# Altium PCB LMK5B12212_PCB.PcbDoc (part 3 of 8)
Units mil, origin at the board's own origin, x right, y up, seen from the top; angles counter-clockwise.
Board outline 7000 x 9161 mil, 8 copper layers (L1-Top Layer (GTL), L2-GND Plane (GP1), L3-Mid-Layer 2 (G1), L4-Mid-Layer 3 (G2), L5-Mid-Layer 4 (G3), L6-Mid-Layer 5 (G4), L7-Mid-Layer 6 (G5), L8-Bottom Layer (GBL)), stack 61.2 mil thick; 469 components, 264 nets, 1268 pads, 1812 vias.

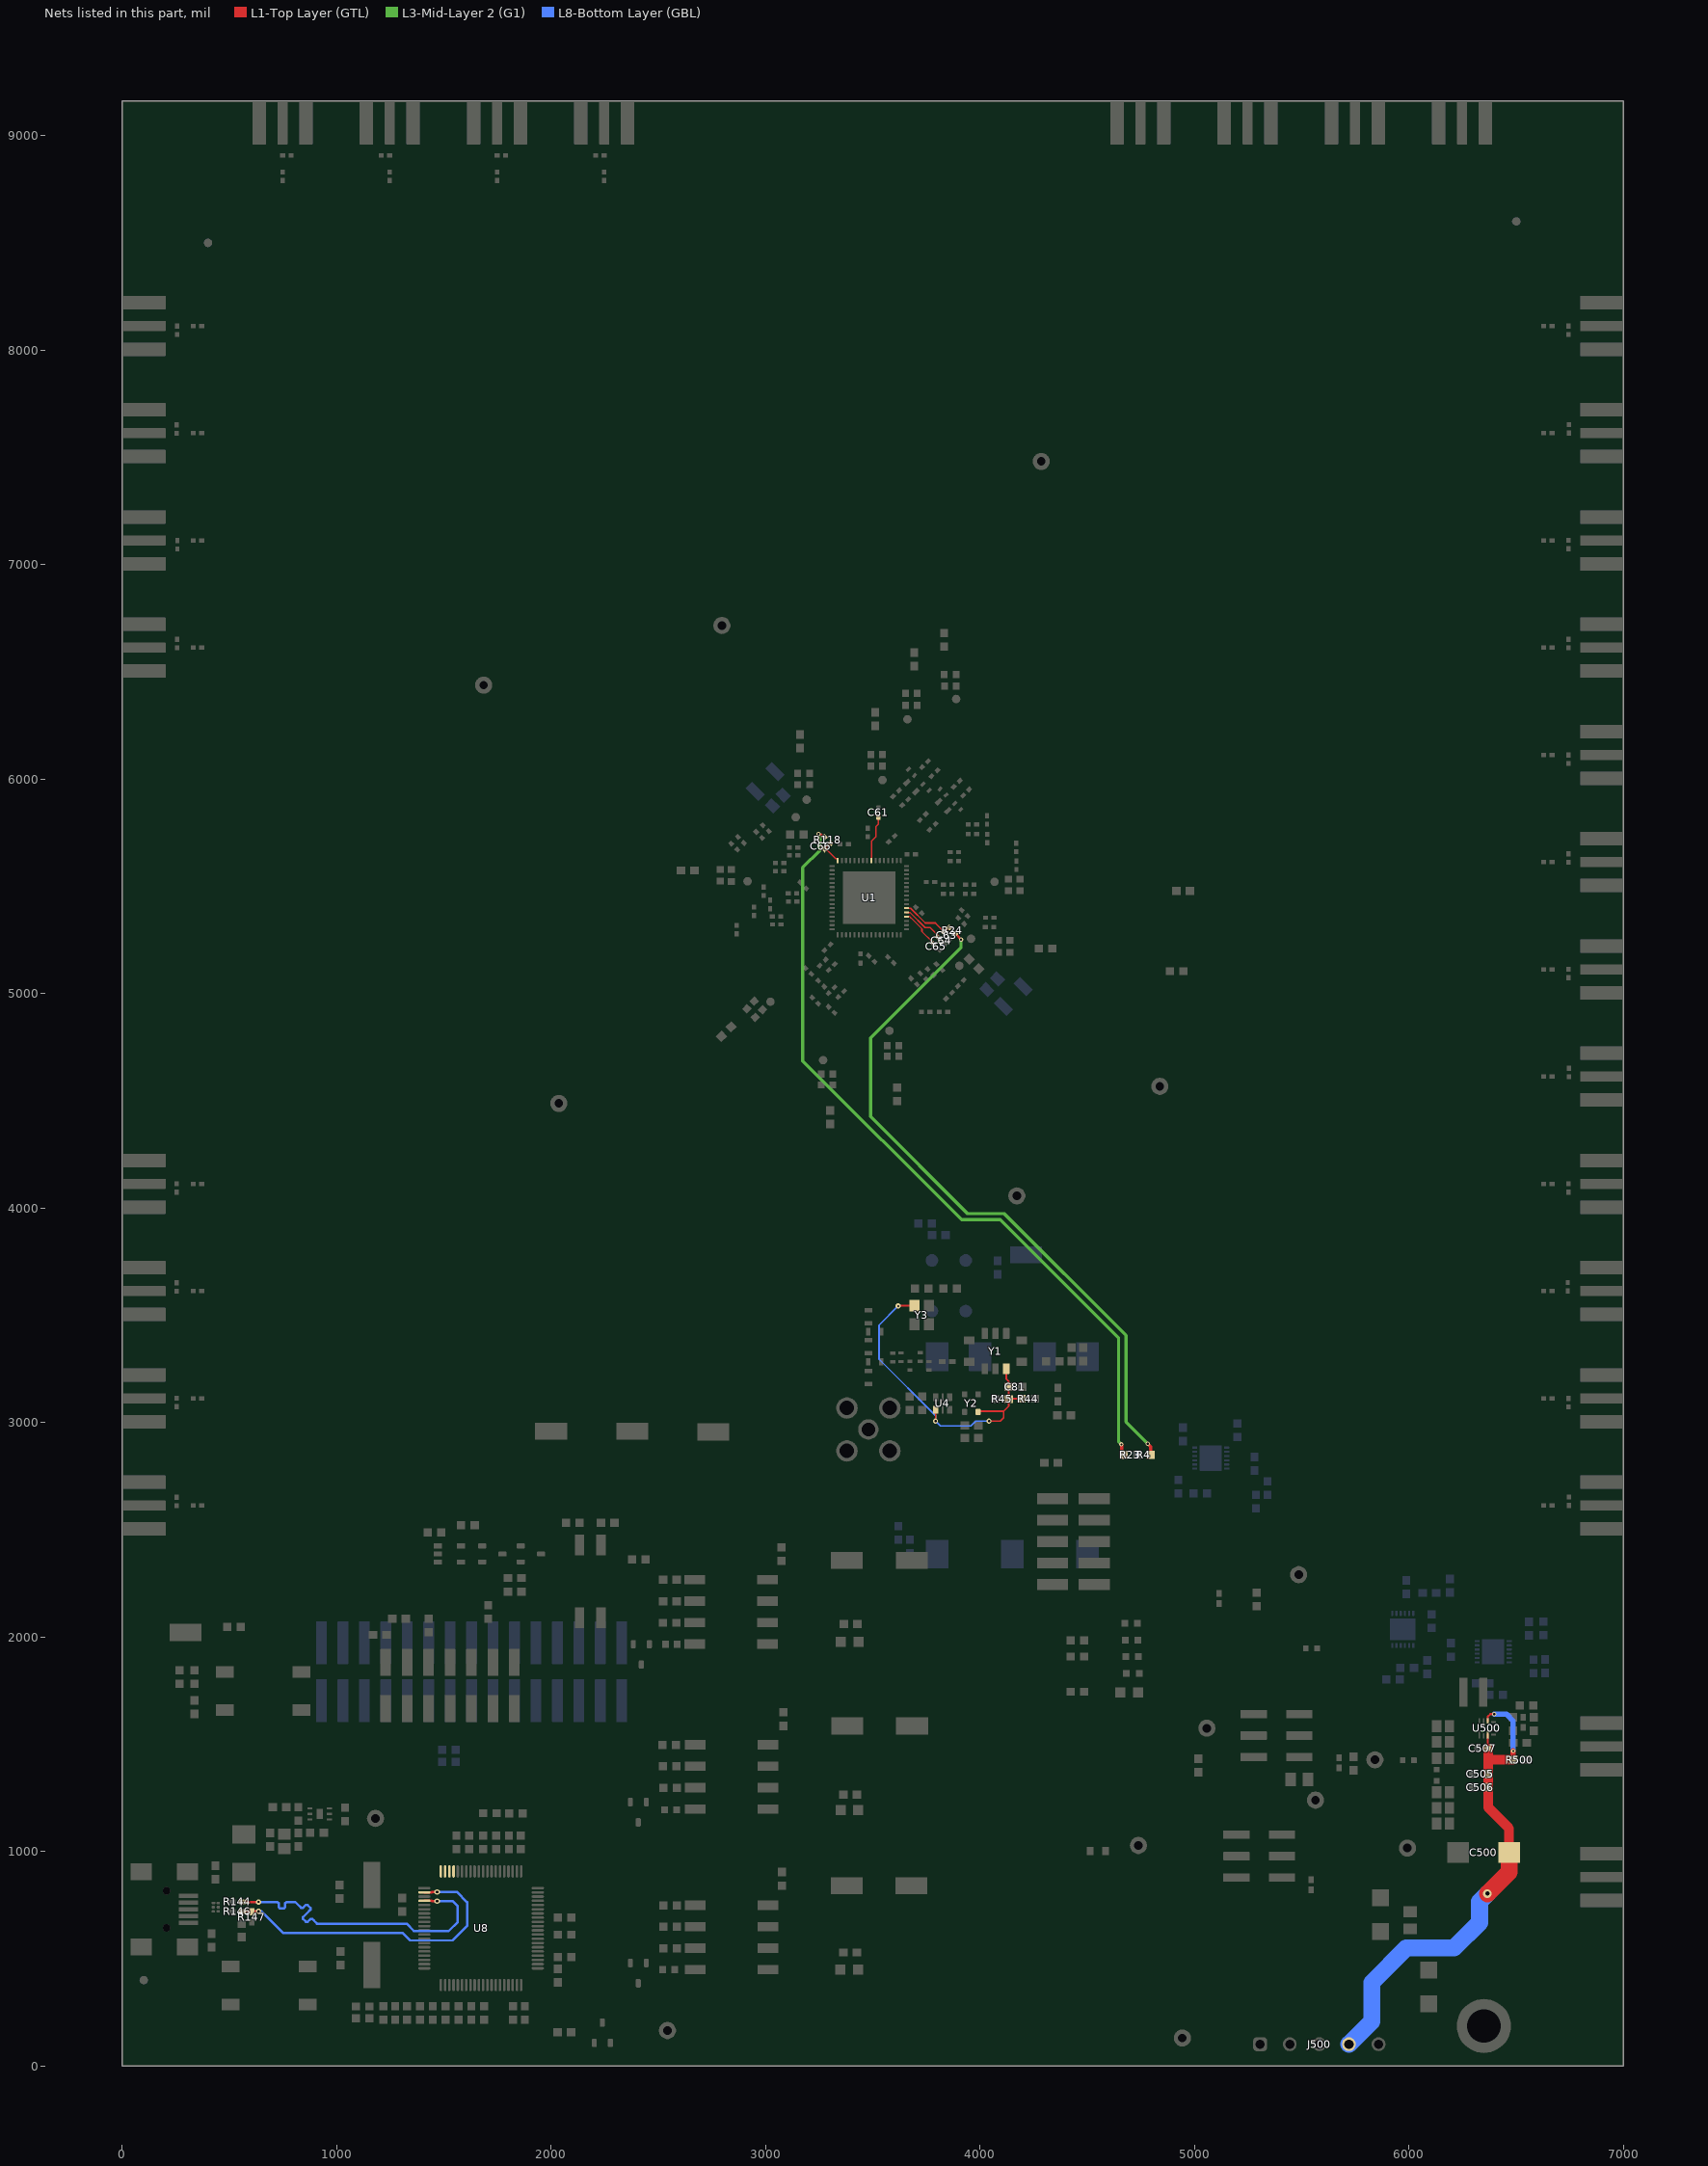
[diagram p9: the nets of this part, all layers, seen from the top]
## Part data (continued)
R144 R146: library part CMP-0026908-3, "RES, 33, 5%, 0.063 W, AEC-Q200 Grade 0, 0402", Manufacturer=Vishay-Dale, PartNumber=CRCW040233R0JNED, Power_W=63mW, Supplier Part Number 1=541-33JCT-ND, TempCo="200 ppm/C", Tolerance_%=5%, Value2=0.063W, Value_Code=33R0, ValueDisplayed=33
R145 R148 R165: library part CMP-0025786-4, "RES, 33 k, 5%, 0.1 W, AEC-Q200 Grade 0, 0603", Manufacturer=Vishay-Dale, PartNumber=CRCW060333K0JNEA, Power_W=100mW, Supplier Part Number 1=541-33KGCT-ND, TempCo="200 ppm/C", Tolerance_%=5%, Value2=0.1W, Value_Code=33k0, ValueDisplayed=33k
R147: library part CMP-0026856-5, "RES, 1.5 k, 5%, 0.063 W, AEC-Q200 Grade 0, 0402", Manufacturer=Vishay-Dale, PartNumber=CRCW04021K50JNED, Power_W=63mW, Supplier Part Number 1=541-1.5KJCT-ND, TempCo="200 ppm/C", Tolerance_%=5%, Value2=0.063W, Value_Code=1k50, ValueDisplayed=1.5k
R149: library part CMP-0025738-4, "RES, 1.2 M, 5%, 0.1 W, AEC-Q200 Grade 0, 0603", Manufacturer=Vishay-Dale, PartNumber=CRCW06031M20JNEA, Power_W=100mW, Supplier Part Number 1=541-1.2MGCT-ND, TempCo="200 ppm/C", Tolerance_%=5%, Value2=0.1W, Value_Code=1M20, ValueDisplayed=1.2M
R159 R160: library part CMP-0025729-4, "RES, 1.0 k, 5%, 0.1 W, AEC-Q200 Grade 0, 0603", Manufacturer=Vishay-Dale, Power_W=100mW, Supplier Part Number 1=541-1.0KGCT-ND, TempCo="200 ppm/C", Tolerance_%=5%, Value2=0.1W, Value_Code=1k00, ValueDisplayed=1.0k
R161 R162 R166: library part CMP-0025823-4, "RES, 510, 5%, 0.1 W, AEC-Q200 Grade 0, 0603", Manufacturer=Vishay-Dale, PartNumber=CRCW0603510RJNEA, Power_W=100mW, Supplier Part Number 1=541-510GCT-ND, TempCo="200 ppm/C", Tolerance_%=5%, Value2=0.1W, Value_Code=510R, ValueDisplayed=510
R201 R202 R203: library part CMP-0025814-4, "RES, 47 k, 5%, 0.1 W, AEC-Q200 Grade 0, 0603", Manufacturer=Vishay-Dale, PartNumber=CRCW060347K0JNEA, Power_W=100mW, Supplier Part Number 1=541-47KGCT-ND, TempCo="200 ppm/C", Tolerance_%=5%, Value2=0.1W, Value_Code=47k0, ValueDisplayed=47k
R206 R207 R208 R209 R210 R211: library part CMP-0025885-5, "RES, 0, 5%, 0.1 W, 0603", Manufacturer=Yageo, Power_W=100mW, Supplier Part Number 1=311-0.0GRCT-ND, TempCo="200 ppm/C", Tolerance_%=5%, Value2=0.1W, Value_Code=0000, ValueDisplayed=0
R501: library part CMP-0023576-3, "RES, 5.60 k, 0.1%, 0.1 W, 0603", Manufacturer="Susumu Co Ltd", Power_W=100mW, Supplier Part Number 1=RG16P5.6KBCT-ND, TempCo="25 ppm/C", Tolerance_%=0.1%, Value2=0.1W, Value_Code=5k60, ValueDisplayed=5.60k
R502: library part CMP-0022097-4, "RES, 18.2 k, 1%, 0.1 W, AEC-Q200 Grade 0, 0603", Manufacturer=Vishay-Dale, Power_W=100mW, Supplier Part Number 1=541-18.2KHCT-ND, TempCo="100 ppm/C", Tolerance_%=1%, Value2=0.1W, Value_Code=18k2, ValueDisplayed=18.2k
R504: library part CMP-0023914-3, "RES, 1.80 k, 0.1%, 0.1 W, 0603", Manufacturer="Yageo America", Power_W=100mW, TempCo="25 ppm/C", Tolerance_%=0.1%, Value2=0.1W, Value_Code=1k80, ValueDisplayed=1.80k
S1 S2 S4: library part CMP-0002176-2, "Switch, SPST 4 Pos, Top Actuated, SMT", CurrentRating_mA=100A, Manufacturer="CTS Electrocomponents", PartNumber=219-4LPST, Supplier Part Number 1=CT2194LPST-ND
S3: library part CMP-0002127-2, "Switch, Slide, SPST 2 poles, SMT", CurrentRating_mA=100A, Manufacturer="CTS Electrocomponents", PartNumber=219-2LPST, Supplier Part Number 1=CT2192LPST-ND
S5 S6: library part CMP-0002134-3, "Switch, Tactile, SPST-NO, 0.05A, 12V, SMT", CurrentRating_mA=50A, Manufacturer="TE Connectivity", PartNumber=FSM4JSMA, Supplier Part Number 1=450-1129-ND
SH1 SH2 SH4 SH5 SH6: library part CMP-0003623-3, "Shunt, 100mil, Gold plated, Black", Alternate Manufacturer=3M, Alternate PartNumber=969102-0000-DA, Manufacturer=Samtec, Supplier Part Number 1=SAM8858-ND
TP1 TP2 TP4 TP5 TP7 TP41 TP501: library part CMP-0055137-1, "Test Point, Miniature, Red, TH", Color=Red, Manufacturer=Keystone, PartNumber=5000, Supplier Part Number 1=36-5000-ND
TP8 TP9 TP10 TP11 TP12 TP13 TP14 TP15 TP16 TP18 TP28 TP29: library part CMP-0003825-1, "1mm Test Point, SMT", Manufacturer=Any, PartNumber=TP_SM_1MM
TP19 TP20 TP21 TP22 TP23 TP24 TP25 TP26: library part CMP-0055138-1, "Test Point, Miniature, Black, TH", Color=Black, Manufacturer=Keystone, PartNumber=5001, Supplier Part Number 1=36-5001-ND
TP30 TP31 TP32 TP33 TP34 TP35 TP36 TP37 TP38 TP39 TP40: library part CMP-0055162-1, "Test Point, Miniature, SMT", Manufacturer=Keystone, PartNumber=5019, Supplier Part Number 1=36-5019TR-ND
U1: library part CMP-0096725-1, "1-DPLL 2-APLL 2-IN 12-OUT Network Synchronizer with JESD204B/C and BAW for Wired Communications", Manufacturer="Texas Instruments", Max Frequency=800MHz, Max Supply Voltage=3.465V, Min Supply Voltage=3.135V, Operating Temperature Range="to +125°C", Part Number=LMK5C22212RGCR
U4: library part CMP-0078850-3, "CDC64XX-2520, DLF0006A (VSON-6)", Alternate Manufacturer="Texas Instruments"
U5: library part CMP-0052046-2, "Single 2-Input Exclusive-OR Gate, DBV0005A (SOT-23-5)", F @ Nom Voltage(Max)(Mhz)=150, Generic Part Number=SN74LVC1G86, ICC @ Nom Voltage(Max)(mA)=0.01, Manufacturer="Texas Instruments", Operating Temperature Range="-40 to 125 C", PartNumber=SN74LVC1G86DBVR, Rating=Catalog, tpd @ Nom Voltage(Max)(ns)=9.9,5.5,5,4, Voltage(Nom)(V)=1.8,2.5,3.3,5
U6: library part CMP-0066010-1, "150-mA Ultra-Low Noise LDO for RF and Analog Circuits Requires No Bypass Capacitor, NGF0006A (WSON-6)", Alternate Manufacturer="Texas Instruments"
U7: library part CMP-0043115-3, "4-Channel ESD Protection Array for High-Speed Data Interfaces, DRY0006A (USON-6)", Breakdown Voltage(Min)(V)=6, IO Capacitance(Typ)(pF)=1.6, IO Leakage Current(nA)=1, Manufacturer="Texas Instruments", Operating Temperature Range="-40 to 85 C", Rating=Catalog
U8: library part CMP-0038965-1, "25 MHz Mixed Signal Microcontroller with 128 KB Flash, 8192 B SRAM and 63 GPIOs, -40 to 85 degC, 80-pin QFP (PN), Green (RoHS & no Sb/Br)", Frequency(MHz)=25, Manufacturer="Texas Instruments", Temp Sensor=Yes
U9 U10 U11: library part CMP-0066007-2, "800-mA Ultra-Low-Noise, High-PSRR LDO, DNT0012B (WSON-12)", Alternate Manufacturer="Texas Instruments"
U500: library part CMP-0860321-2, "3A Low Noise and Low Ripple buck converter, RPU0010A (VQFN-10)", Alternate Manufacturer="Texas Instruments"
Y1: library part CMP-0093851-1, "SMD TCXO 7.0 * 5.0 48.000000MHz", Frequency_Fixed=48MHz, Frequency Stability=0.25ppm, Load Capacitance=15pF, Manufacturer=TXC, Max Supply Current=10mA, Max Supply Voltage=3.63V, Min Supply Voltage=2.97V, Operating Temperature Range="-40°C to +105°C"
Y2: library part CMP-0096255-1, "High-Performance BAW Oscillator, LVCMOS; <1ps, +/- 50ppm; 2.5V/3.3V, -40C to 105C and DLE package", Frequency Stability=50ppm, Frequency_Fixed=48MHz, Load Capacitance=30pF, Manufacturer="Texas Instruments", Max Supply Voltage=3.465V, Min Supply Voltage=2.375V, Operating Temperature Range="-40°C to +105°C", PartNumber=LMK6CE04800DDLF
Y3: library part CMP-0006115-3, "Crystal, Sealed Locked 50 MHz, 15pF, SMD", Frequency_Fixed=50MHz, Frequency Stability=+/-50ppm, Manufacturer="TXC Corporation", Supplier Part Number 1=887-1513-1-ND
Y4: library part CMP-0088752-1, "MERCURY+ 38.88MHz OCXO CMOS Oscillator 2.7 ~ 5V 4-SMD", Frequency_Fixed=38.88MHz, Frequency Stability=0.01ppm, Manufacturer=Rakon, Max Supply Voltage=5V, Min Supply Voltage=2.7V, Operating Temperature Range="-40°C to +95°C"
Y5: library part CMP-0088753-1, "STANDARD OCXO 10MHz Frequency", Frequency_Fixed=10MHz, Manufacturer=Rakon, Max Supply Voltage=3.465V, Min Supply Voltage=3.135V, Operating Temperature Range="-40°C to +85°C"
Y6: library part CMP-0004572-3, "Crystal, 24.000 MHz, 20pF, SMD", Frequency_Fixed=24MHz, Frequency Stability=+/-50ppm, Manufacturer="ECS Inc.", PartNumber=ECS-240-20-5PX-TR, Supplier Part Number 1=XC1255CT-ND
ZZ1: library part CMP-0003616-3
ZZ2: library part CMP-0077236-1
ZZ3: library part CMP-0077237-1
ZZ4: library part CMP-0077238-1
ZZ5 ZZ6 ZZ7: library part CMP-0003615-1, "This Assembly Note will show in the PcbDoc and associated outputs"

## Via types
v1: diameter 20, hole 10, L1-Top Layer (GTL) to L8-Bottom Layer (GBL), tented top, 987 vias
v2: diameter 30, hole 12, L1-Top Layer (GTL) to L8-Bottom Layer (GBL), 407 vias
v3: diameter 25, hole 12, L1-Top Layer (GTL) to L8-Bottom Layer (GBL), tented top, 163 vias
v4: diameter 30, hole 12, L1-Top Layer (GTL) to L8-Bottom Layer (GBL), tented top, 52 vias
v5: diameter 19.68, hole 7.87, L1-Top Layer (GTL) to L8-Bottom Layer (GBL), 47 vias
v6: diameter 20, hole 10, L1-Top Layer (GTL) to L8-Bottom Layer (GBL), 39 vias
v7: diameter 25, hole 10, L1-Top Layer (GTL) to L8-Bottom Layer (GBL), tented top, 35 vias
v8: diameter 25, hole 12, L1-Top Layer (GTL) to L8-Bottom Layer (GBL), 23 vias
v9: diameter 30, hole 10, L1-Top Layer (GTL) to L8-Bottom Layer (GBL), 10 vias
v10: diameter 40, hole 20, L1-Top Layer (GTL) to L8-Bottom Layer (GBL), 10 vias
v11: diameter 18, hole 10, L1-Top Layer (GTL) to L8-Bottom Layer (GBL), tented top, 8 vias
v12: diameter 20, hole 10, L1-Top Layer (GTL) to L8-Bottom Layer (GBL), tented both sides, 6 vias
v13: diameter 39.37, hole 19.68, L1-Top Layer (GTL) to L8-Bottom Layer (GBL), tented top, 6 vias
v14: diameter 50, hole 28, L1-Top Layer (GTL) to L8-Bottom Layer (GBL), 4 vias
v15: diameter 23, hole 10, L1-Top Layer (GTL) to L8-Bottom Layer (GBL), tented top, 4 vias
v16: diameter 25, hole 10, L1-Top Layer (GTL) to L8-Bottom Layer (GBL), 4 vias
v17: diameter 25, hole 12, L1-Top Layer (GTL) to L8-Bottom Layer (GBL), tented both sides, 3 vias
v18: diameter 20/0/0/0/0/0/20 (per signal layer), hole 10, L1-Top Layer (GTL) to L8-Bottom Layer (GBL), tented top, 2 vias
v19: diameter 30, hole 12, L1-Top Layer (GTL) to L8-Bottom Layer (GBL), tented both sides, 1 vias
v20: diameter 25, hole 10, L1-Top Layer (GTL) to L8-Bottom Layer (GBL), tented both sides, 1 vias

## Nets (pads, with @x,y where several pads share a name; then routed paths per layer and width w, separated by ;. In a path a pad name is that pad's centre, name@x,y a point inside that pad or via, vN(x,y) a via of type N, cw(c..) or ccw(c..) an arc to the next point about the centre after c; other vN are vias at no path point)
+12V: C500.1 C505.2 C506.2 C507.1 J500.4 R500.2 U500.1 U500.6 | length 2378.2
  L1-Top Layer (GTL) w10: U500.6@6367.34,1546.44 6367.34,1480.88 C507.1@6367.92,1480.3 ; U500.1@6367.34,1608.45 6367.34,1628.34 6379.3,1640.3 v6(6397.8,1640.3)
  L1-Top Layer (GTL) w25: R500.2@6485.8,1428.3 v12(6485.8,1468)
  L1-Top Layer (GTL) w45: C507.1@6368.22,1480 C505.2@6368.22,1360.5 C506.2@6368.22,1299.4 6368.22,1205.78 6466.69,1107.31 C500.1@6466.69,995.9 ; 6368.42,1427.1 R500.2@6484.6,1427.1
  L1-Top Layer (GTL) w80: v10(6365.6,803.2) 6466.69,904.29 C500.1@6466.69,995.9
  L8-Bottom Layer (GBL) w25: v6(6397.8,1640.3) 6453.4,1640.3 6485.8,1607.9 v12(6485.8,1468)
  L8-Bottom Layer (GBL) w80: J500.4@5719.7,101.2 5826.3,207.8 5826.3,388.7 5987.6,550 6210.1,550 6328.5,668.4 6328.5,766.1 v10(6365.6,803.2)
APLL1_LDO: R23.2 R118.1 | length 3690.2
  L1-Top Layer (GTL) w11: v6(3247.1,5744.1) 3248.82,5742.38 3256.28,5742.38 3268.94,5729.72 R118.1@3275.08,5729.72
  L1-Top Layer (GTL) w15: v6(4658.7,2897.7) 4659.66,2896.74 4659.66,2858.76 R23.2@4669.12,2849.3
  L3-Mid-Layer 2 (G1) w15: v6(3247.1,5744.1) 3247.1,5742.75 3253.81,5736.04 3253.81,5702.16 3254,5701.97 3254,5668.1 3173.35,5587.45 3173.35,4685.75 3914,3945.1 4094.3,3945.1 4646,3393.4 4646,2910.4 v6(4658.7,2897.7)
APLL2_LDO: R4.2 R24.1 | length 3267.9
  L1-Top Layer (GTL) w11: R24.1@3885.32,5276.77 3887.68,5276.77 3887.68,5276.07 3911,5252.75 v6(3911,5251.1)
  L1-Top Layer (GTL) w15: R24.1@3885.32,5276.77 R24.1@3885.32,5280.08 ; v6(4782.1,2900.7) 4795.1,2887.7 R4.2@4795.1,2849.3
  L3-Mid-Layer 2 (G1) w15: v6(3911,5251.1) 3911,5214.5 3489.05,4792.55 3489.05,4425.75 3941.05,3973.75 4111.85,3973.75 4680.2,3405.4 4680.2,3002.6 v6@4788.64,2894.16
C1PLL2: C63.1 R24.2 U1.22 | length 259
  L1-Top Layer (GTL) w8: U1.22@3656.38,5397.64 3657.1,5396.91 3676.29,5396.91 3744.4,5328.8 3791.24,5328.8 C63.1@3831.49,5288.55
  L1-Top Layer (GTL) w15: C63.1@3829.89,5286.81 3851.59,5308.51 3857.59,5308.51 R24.2@3858.98,5307.12
C2PLL2: C64.1 U1.21 | length 195.4
  L1-Top Layer (GTL) w7: U1.21@3656.38,5377.95 3672.8,5377.95 3743.31,5307.44 3767.26,5307.44 C64.1@3806.4,5268.3
C3PLL2: C65.1 U1.20 | length 177.8
  L1-Top Layer (GTL) w7: U1.20@3656.38,5358.27 3671.73,5358.27 3676.92,5353.08 3677.42,5353.08 3728.92,5301.59 3728.92,5288.86 C65.1@3777.73,5240.05
CDIG: C61.1 U1.40 | length 209.8
  L1-Top Layer (GTL) w7: U1.40@3492.99,5620.08 3492.99,5709.98 3515,5731.99 3515,5779.06 3526.25,5790.31 C61.1@3526.25,5816.13
CPLL1: C66.1 R118.2 U1.48 | length 123.7
  L1-Top Layer (GTL) w7: C66.1@3280.59,5675 3327.4,5628.19 3334.29,5628.19 3335.51,5626.97 U1.48@3335.51,5620.08
  L1-Top Layer (GTL) w10: C66.1@3272.88,5673.1 3277.06,5677.28 3278.31,5677.28 R118.2@3302.92,5701.88
D_N: R144.1 U8.64 | length 1464.2
  L1-Top Layer (GTL) w11: R144.1@559.62,765 580.87,765 581.37,764.5 v16(635,764.5) ; U8.64@1407.95,769.8 1441.99,769.8 1444.3,767.49 v3(1468,767.49)
  L8-Bottom Layer (GBL) w11: v16(635,764.5) 713,764.5 722.8,764.5 729,758.3 729,740.35 735.2,734.15 753.8,734.15 760,740.35 760,758.3 766.2,764.5 791,764.5 806.5,764.5 816.28,754.72 833.82,737.18 842.58,737.18 855.28,749.88 864.05,749.88 877.2,736.73 877.2,727.96 860.12,710.88 843.04,693.8 843.04,685.03 856.19,671.88 864.96,671.88 877.66,684.58 886.42,684.58 893,678 908,663 1326,663 1360,629 1522,629 1564,671 1564,745 1541.51,767.49 v3(1468,767.49)
D_P: R146.1 R147.2 U8.62 | length 1464.2
  L1-Top Layer (GTL) w11: R146.1@559.62,720 580.87,720 581.37,720.5 604,720.5 v20(635,720.5) ; U8.62@1407.95,809.17 1441.99,809.17 1444.3,811.49 v3(1468,811.49)
  L8-Bottom Layer (GBL) w11: v20(635,720.5) 649.5,720.5 751,619 1307.77,619 1341.77,585 1540.23,585 1608,652.77 1608,763.23 1559.74,811.49 v3(1468,811.49)
EN_XO: C81.1 R44.2 R45.1 U4.1 Y1.8 Y2.1 Y3.1 | length 1568
  L1-Top Layer (GTL) w8: v7(3618.41,3542.53) 3620.23,3544.35 Y3.1@3693.86,3544.35 ; v15(3792.57,3006.56) 3792.57,3006.24 U4.1@3792.57,3059.17 ; Y2.1@3989.9,3052.51 4109.38,3052.51 ; v15(4041.79,3006.24) 4093.21,3006.24 4109.38,3022.41 4109.38,3052.51 ; Y1.8@4121.72,3244.08 4121.72,3204.42 4132.86,3193.28 R45.1@4132.86,3110.68 ; R44.2@4192.86,3110.68 4135.18,3110.68 R45.1@4133.43,3108.93 4133.43,3076.56 4109.38,3052.51
  L8-Bottom Layer (GBL) w8: v7(3618.41,3542.53) 3529,3453.12 3529,3295.09 3792.57,3031.52 v15(3792.57,3006.56) 3792.57,3006.24 3814.81,2984 3957.24,2984 3979.48,3006.24 v15(4041.79,3006.24)
EXT3.3V_EN: U8.59
EXT3.3V_FAULT: U8.60
EXT5V_EN: U8.57
EXT5V_FAULT: U8.58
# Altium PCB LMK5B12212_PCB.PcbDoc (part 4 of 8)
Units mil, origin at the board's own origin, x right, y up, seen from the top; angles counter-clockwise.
Board outline 7000 x 9161 mil, 8 copper layers (L1-Top Layer (GTL), L2-GND Plane (GP1), L3-Mid-Layer 2 (G1), L4-Mid-Layer 3 (G2), L5-Mid-Layer 4 (G3), L6-Mid-Layer 5 (G4), L7-Mid-Layer 6 (G5), L8-Bottom Layer (GBL)), stack 61.2 mil thick; 469 components, 264 nets, 1268 pads, 1812 vias.

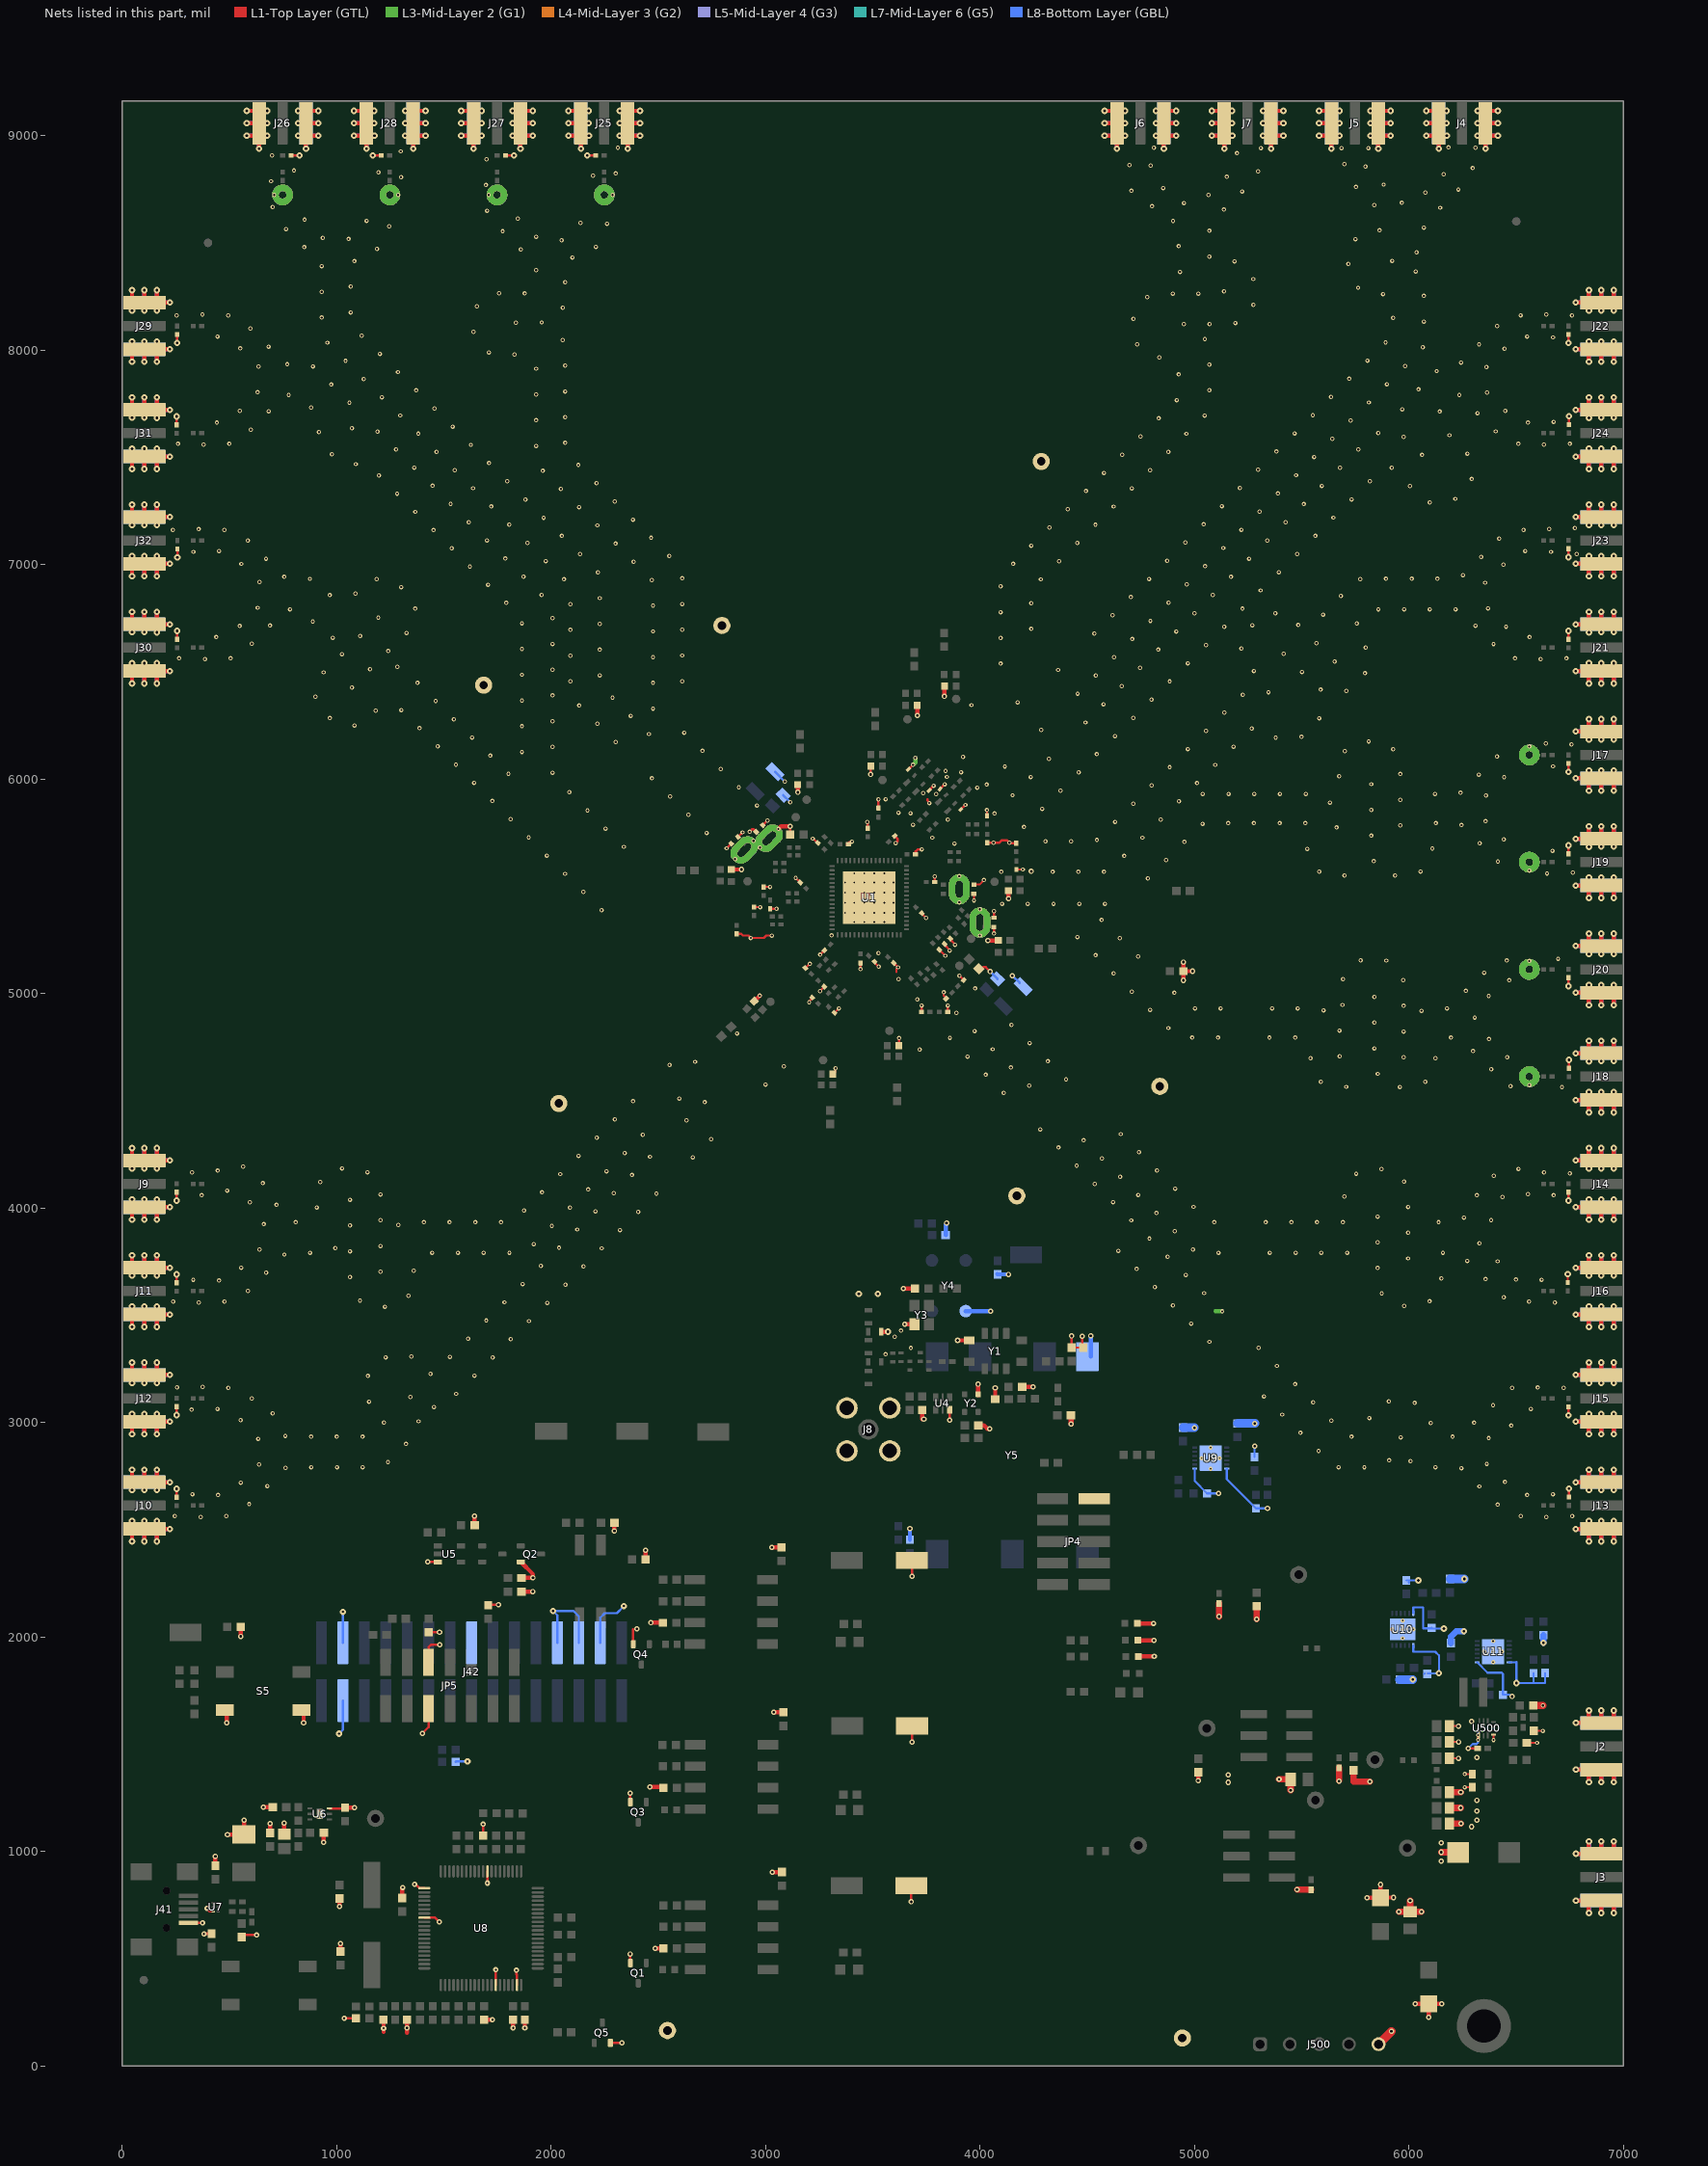
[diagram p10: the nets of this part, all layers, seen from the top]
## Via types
v1: diameter 20, hole 10, L1-Top Layer (GTL) to L8-Bottom Layer (GBL), tented top, 987 vias
v2: diameter 30, hole 12, L1-Top Layer (GTL) to L8-Bottom Layer (GBL), 407 vias
v3: diameter 25, hole 12, L1-Top Layer (GTL) to L8-Bottom Layer (GBL), tented top, 163 vias
v4: diameter 30, hole 12, L1-Top Layer (GTL) to L8-Bottom Layer (GBL), tented top, 52 vias
v5: diameter 19.68, hole 7.87, L1-Top Layer (GTL) to L8-Bottom Layer (GBL), 47 vias
v6: diameter 20, hole 10, L1-Top Layer (GTL) to L8-Bottom Layer (GBL), 39 vias
v7: diameter 25, hole 10, L1-Top Layer (GTL) to L8-Bottom Layer (GBL), tented top, 35 vias
v8: diameter 25, hole 12, L1-Top Layer (GTL) to L8-Bottom Layer (GBL), 23 vias
v9: diameter 30, hole 10, L1-Top Layer (GTL) to L8-Bottom Layer (GBL), 10 vias
v10: diameter 40, hole 20, L1-Top Layer (GTL) to L8-Bottom Layer (GBL), 10 vias
v11: diameter 18, hole 10, L1-Top Layer (GTL) to L8-Bottom Layer (GBL), tented top, 8 vias
v12: diameter 20, hole 10, L1-Top Layer (GTL) to L8-Bottom Layer (GBL), tented both sides, 6 vias
v13: diameter 39.37, hole 19.68, L1-Top Layer (GTL) to L8-Bottom Layer (GBL), tented top, 6 vias
v14: diameter 50, hole 28, L1-Top Layer (GTL) to L8-Bottom Layer (GBL), 4 vias
v15: diameter 23, hole 10, L1-Top Layer (GTL) to L8-Bottom Layer (GBL), tented top, 4 vias
v16: diameter 25, hole 10, L1-Top Layer (GTL) to L8-Bottom Layer (GBL), 4 vias
v17: diameter 25, hole 12, L1-Top Layer (GTL) to L8-Bottom Layer (GBL), tented both sides, 3 vias
v18: diameter 20/0/0/0/0/0/20 (per signal layer), hole 10, L1-Top Layer (GTL) to L8-Bottom Layer (GBL), tented top, 2 vias
v19: diameter 30, hole 12, L1-Top Layer (GTL) to L8-Bottom Layer (GBL), tented both sides, 1 vias
v20: diameter 25, hole 10, L1-Top Layer (GTL) to L8-Bottom Layer (GBL), tented both sides, 1 vias

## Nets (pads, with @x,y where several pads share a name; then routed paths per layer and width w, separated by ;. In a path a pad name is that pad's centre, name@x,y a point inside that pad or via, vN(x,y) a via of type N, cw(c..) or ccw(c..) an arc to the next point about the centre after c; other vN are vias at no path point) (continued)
GND: C1.2 C2.2 C3.2 C6.1 C7.2 C8.2 C9.2 C10.2 C13.2 C21.1 C22.2 C23.2 C24.2 C27.2 C29.2 C30.1 C32.2 C33.1 C35.2 C36.1 C38.2 C39.1 C41.2 C42.1 C44.2 C45.1 C47.2 C48.1 C50.2 C51.1 C53.2 C54.1 C59.2 C60.1 C61.2 C63.2 C64.2 C65.2 C66.2 C72.2 C73.1 C74.2 C75.2 C76.1 C77.2 C78.2 C79.1 C80.2 C81.2 C82.2 C83.2 C84.2 C85.2 C86.2 C87.2 C88.2 C89.1 C90.2 C91.2 C92.2 C93.2 C94.2 C95.2 C96.2 C97.2 C129.1 C130.2 C131.2 C132.1 C133.1 C134.1 C135.2 C136.2 C137.1 C138.1 C139.2 C140.1 C141.1 C142.1 C143.1 C144.1 C154.2 C155.2 C156.2 C500.2 C501.2 C502.2 C503.2 C504.2 C505.1 C506.1 C507.2 C508.2 C509.2 C510.2 C512.2 C513.2 C514.2 C515.2 C516.2 D1.2 D2.2 D3.2 D4.2 D5.2 D11.2 J2.2 J2.3 J2.4 J2.5 J3.2 J3.3 J3.4 J3.5 J4.2 J4.3 J4.4 J4.5 J5.2 J5.3 J5.4 J5.5 J6.2 J6.3 J6.4 J6.5 J7.2 J7.3 J7.4 J7.5 J8.2 J8.3 J8.4 J8.5 J9.2 J9.3 J9.4 J9.5 J10.2 J10.3 J10.4 J10.5 J11.2 J11.3 J11.4 J11.5 J12.2 J12.3 J12.4 J12.5 J13.2 J13.3 J13.4 J13.5 J14.2 J14.3 J14.4 J14.5 J15.2 J15.3 J15.4 J15.5 J16.2 J16.3 J16.4 J16.5 J17.2 J17.3 J17.4 J17.5 J18.2 J18.3 J18.4 J18.5 J19.2 J19.3 J19.4 J19.5 J20.2 J20.3 J20.4 J20.5 J21.2 J21.3 J21.4 J21.5 J22.2 J22.3 J22.4 J22.5 J23.2 J23.3 J23.4 J23.5 J24.2 J24.3 J24.4 J24.5 J25.2 J25.3 J25.4 J25.5 J26.2 J26.3 J26.4 J26.5 J27.2 J27.3 J27.4 J27.5 J28.2 J28.3 J28.4 J28.5 J29.2 J29.3 J29.4 J29.5 J30.2 J30.3 J30.4 J30.5 J31.2 J31.3 J31.4 J31.5 J32.2 J32.3 J32.4 J32.5 J41.5 J42.4 J42.6 J42.8 J42.16 J42.27 J42.28 J500.5 JP4.9 JP5.A03 JP5.B03 Q1.2 Q2.2 Q3.2 Q4.2 Q5.2 R2.1 R5.1 R9.1 R28.1 R32.1 R35.1 R39.1 R42.1 R45.2 R53.1 R62.1 R65.1 R69.1 R72.1 R78.1 R79.1 R82.1 R85.1 R86.1 R88.1 R90.1 R92.1 R94.1 R96.1 R99.1 R101.1 R103.1 R105.1 R109.1 R111.1 R113.1 R115.1 R117.1 R119.1 R121.1 R122.1 R125.1 R127.1 R148.2 R149.1 R167.2 R168.2 R169.2 R170.2 R171.2 R172.2 R173.2 R174.2 R175.2 R176.2 R177.2 R178.2 R179.2 R180.2 R181.2 R182.2 R183.2 R184.2 R185.2 R186.2 R187.2 R188.2 R204.2 R205.2 R502.1 R504.1 S5.3 S5.4 TP19.1 TP20.1 TP21.1 TP22.1 TP23.1 TP24.1 TP25.1 TP26.1 TP32.1 TP35.1 TP39.1 U1.65 U4.3 U5.3 U6.3 U6.7 U7.3 U8.14 U8.19 U8.49 U8.61 U8.68 U9.6 U9.7 U9.13 U10.6 U10.7 U10.13 U11.6 U11.7 U11.13 U500.4 U500.7 Y1.4 Y2.2 Y3.2 Y4.2 Y5.7 | length 75760.6
  L1-Top Layer (GTL) w10: v7(396,735) 396,730 405.68,720.32 U7.3@424.19,720.32 ; R186.2@2864,5278 2886,5278 2894,5270 2919.46,5270 v1(2930.46,5259) 2960,5259 2992,5259 3003,5270 v1(3029,5270) ; R188.2@2944.73,5402.71 v1(2974.27,5402.71) ; R185.2@2991.21,5497 v1(3020.75,5497) ; R187.2@3021,5395 v1(3050.54,5395) ; v1(3139.94,5538.93) C51.1@3161.14,5517.73 ; v1(3203,4958.8) 3204.91,4960.71 3204.91,4965.66 3216.86,4977.61 R170.2@3216.86,4981.14 ; v1(3219.2,5722.1) 3221.91,5722.1 3237.28,5706.73 C66.2@3239.25,5706.73 ; v1(3253.64,5010.36) R169.2@3273.14,5031.86 ; v1(3254.4,5181.04) C33.1@3274.58,5201.22 ; R168.2@3321.14,4909.86 v1(3342.03,4930.75) ; C60.1@3379.69,5695.4 3380.48,5695.4 3391.37,5706.29 3400.59,5706.29 v1(3402.5,5708.2) ; C3.2@3442.3,5143.3 3442.5,5143.1 3442.5,5113.7 v6(3442.7,5113.5) ; v1(3474.04,5799.47) 3476.04,5797.47 C42.1@3476.04,5770.83 ; C48.1@3506.18,5146.28 v1(3527.04,5125.42) ; C39.1@3597.4,5142.27 v1@3616.66,5123.01 ; 3610,5101 3610,5114.35 v1(3617.66,5122.01) ; C54.1@3727,5373.31 3747.89,5352.42 v1(3747.89,5352.18) ; 3754.5,5904.9 3754.5,5899.21 3763,5890.71 v1(3763,5888) ; C45.1@3788.61,5519.89 v1(3788.61,5546.18) ; C65.2@3813.99,5199.91 v1(3837.89,5176.01) ; v1(3830.4,5005.51) 3830.5,5005.41 3830.5,4989.1 3841.16,4978.44 R174.2@3841.16,4976.06 ; v3(3857.53,3011) U4.3@3857.53,3059.17 ; v1(3971.41,5434.16) R204.2@3971.41,5463.49 ; R176.2@3972,5508 3997,5508 v1(4018,5529) ; R178.2@4032,5829 v12(4032,5855) ; v1(4136.82,5702.51) 4138.64,5700.69 R205.2@4168,5700.69 ; R179.2@4169,5578.31 v1(4199.02,5578.31) ; C80.2@4426.24,3349.13 C80.2@4426.24,3349.38 ; v3(4426.24,3403.18) C80.2@4426.24,3349.38 ; v3(4475.99,3402.56) C79.1@4475.99,3349.38 ; C79.1@4480.99,3349.38 C79.1@4475.99,3349.38 ; C501.2@6185.33,1584.4 C501.2@6188.03,1584.4 v8(6230.3,1584.4) ; C503.2@6188.03,1434.1 v8(6230.3,1434.1) ; C502.2@6188.03,1510.6 v8(6230.7,1510.6) ; v6(6259.4,1299.4) C506.1@6295.38,1299.4 ; v6(6259.8,1360.5) C505.1@6295.38,1360.5 ; v17@6276.5,1480.3 C507.2@6320.68,1480.3 ; v6(6322.1,1520.3) v6(6322.1,1542.3) ; v12(6393.92,1519.22) U500.7@6393.92,1544.47 ; C512.2@6549.1,1506.3 v6(6596.7,1506.3) ; R504.1@6581.9,1561.9 v12(6623.8,1561.9) ; C80.2@4426.24,3349.38 C79.1@4475.99,3349.38
  L1-Top Layer (GTL) w11: R79.1@253,2652 v4(253,2690.5) ; v4(254,3034.5) R85.1@254,3073 ; R82.1@254,3652 v4(254,3690.5) ; v4(254,4034.5) R78.1@254,4073 ; R125.1@254,7652 v4(254,7690.5) ; R122.1@255,6652 v4(255,6690.5) ; v4(255,8033.5) R121.1@255,8072 ; v4(257,7033.5) R127.1@257,7072 ; 577.5,610 v7(626,610) ; R115.1@788,8907 v4(826.5,8907) ; U6.3@965.78,1200.18 1034.67,1200.18 C130.2@1039,1204.51 ; v7(1034.71,221.85) C139.2@1089.72,221.85 ; v4(1168.5,8907) R119.1@1207,8907 ; v3(1399.5,1550.7) 1428.36,1579.56 JP5.A03@1428.36,1665.92 ; v3(1424.5,2349.5) U5.3@1471.28,2349.5 ; JP5.B03@1428.36,1880.88 1428.36,1952.36 1439,1963 v3(1480,1963) ; C92.2@1429.04,2022.18 v3(1479.28,2022.18) ; C93.2@1706,2150.43 v3(1753.79,2150.43) ; R117.1@1788,8907 v4(1826.5,8907) ; v4(2168.5,8907) R113.1@2207,8907 ; Q5.2@2275.8,107.08 v3(2329.92,107.08) ; Q1.2@2368.68,479.73 v3(2368.68,521.67) ; Q3.2@2368.69,1230.06 v3(2368.69,1272) ; 2381.1,2036.3 2382,2035.4 2382,1966.95 Q4.2@2382.91,1966.04 ; v1(2818.13,5677.07) R182.2@2839.69,5698.63 ; R184.2@2870.81,5729.74 v1(2892.37,5751.3) ; v1(2924.96,5753.88) 2936.47,5765.4 2943.93,5765.4 R183.2@2955.45,5753.88 ; R181.2@2986.56,5785 v1(3008.12,5806.56) ; C75.2@3114.27,5741.54 v3(3114.27,5779.72) ; R167.2@3184.86,5119.14 v1(3206.77,5138.06) ; C38.2@3313.65,4623.46 3324.28,4634.09 3324.28,4649.58 v1(3326,4651.3) ; v3(3489.58,6021.24) C41.2@3489.58,6060.78 ; C61.2@3526.25,5871.25 v1(3526.25,5905.61) ; C36.1@3601.6,5734.83 3614.61,5721.82 3614.61,5709.51 v1(3606.81,5701.7) ; C47.2@3621.92,4756.58 v1(3621.92,4792.04) ; R35.1@3665.53,6044.9 v1(3687.09,6066.46) ; v3(3679,765) TP32.1@3679,840 ; v3(3682,2282) TP39.1@3682,2357 ; v3(3683,1510) TP35.1@3683,1585 ; C30.1@3699.03,5649.19 3699.03,5661.59 3709.24,5671.81 v1@3728.03,5671.81 ; R171.2@3727.02,4914.81 v1(3727.02,4944.19) ; R39.1@3761.75,5947.25 v1(3783.31,5968.81) ; R32.1@3813.05,5953.9 v1(3834.61,5975.46) ; C64.2@3835.9,5232.64 3835.9,5225.03 3858,5202.94 v1(3858,5200.5) ; R173.2@3849.55,4914.64 v1(3849.55,4944.02) ; C63.2@3867.2,5253.56 3867.2,5245.33 3883,5229.54 v1(3883,5227.1) ; v1(3903.68,5082.9) R172.2@3924.05,5062.53 ; R28.1@3909.77,5857.94 v1(3931.33,5879.5) ; 4014.19,5123.38 4025.9,5123.38 v3(4047.22,5102.07) ; R180.2@4034,5703 v1(4063,5702.63) 4088.63,5702.63 4101,5715 4124.33,5715 v1(4136.82,5702.51) ; v1(4064.49,5279.75) R175.2@4064.49,5309.45 ; R177.2@4064.82,5353.81 v1(4064.82,5383.51) ; R92.1@6740,3653 v4(6740,3691.5) ; R99.1@6743,5652 v4(6743,5690.5) ; R103.1@6743,6652 v4(6743,6690.5) ; v4(6743,8033.5) R105.1@6743,8072 ; v4(6744,3033.5) R90.1@6744,3072 ; v4(6744,4034.5) R88.1@6744,4073 ; v4(6744,5034.5) R101.1@6744,5073 ; v4(6744,6033.5) R94.1@6744,6072 ; v4(6744,7034.5) R109.1@6744,7073 ; R86.1@6745,2653 v4(6745,2691.5) ; R96.1@6745,4652 v4(6745,4690.5) ; R111.1@6745,7653 v4(6745,7691.5)
  L1-Top Layer (GTL) w12: J41.5@308.36,667.01 v7(373.99,667.01) ; v7(381,615) 382.5,616.5 R148.2@416,616.5 ; v7@1367.71,846.85 1385.7,828.86 U8.61@1407.95,828.86 ; U8.68@1407.95,691.06 1458.5,691.06 v7(1477.71,671.85) ; C144.1@1682.71,1073.35 v7(1682.71,1126.85) ; U8.49@1702.24,906.61 v7(1702.24,852.32) v7@1702.71,851.85 ; U8.14@1741.61,377.09 v7@1741.61,448 ; v7(1838,446) 1838,426.56 1840.03,424.53 U8.19@1840.03,377.09
  L1-Top Layer (GTL) w20: v2(45.56,2445.57) J10.2@45.56,2503.44 ; v2@45.56,2542.7 v2(45.56,2540.45) J10.2@45.56,2503.44 ; v2@45.56,2682.3 v2(45.56,2684.55) J10.3@45.56,2721.56 ; v2(45.56,2779.43) J10.3@45.56,2721.56 ; v2(45.56,2945.57) J12.2@45.56,3003.44 ; v2@45.56,3042.7 v2(45.56,3040.45) J12.2@45.56,3003.44 ; v2@45.56,3182.3 v2(45.56,3184.55) J12.3@45.56,3221.56 ; v2(45.56,3279.43) J12.3@45.56,3221.56 ; v2(45.56,3445.57) J11.2@45.56,3503.44 ; v2@45.56,3542.7 v2(45.56,3540.45) J11.2@45.56,3503.44 ; v2@45.56,3682.3 v2(45.56,3684.55) J11.3@45.56,3721.56 ; v2(45.56,3779.43) J11.3@45.56,3721.56 ; v2(45.56,3945.57) J9.2@45.56,4003.44 ; v2@45.56,4042.7 v2(45.56,4040.45) J9.2@45.56,4003.44 ; v2@45.56,4182.3 v2(45.56,4184.55) J9.3@45.56,4221.56 ; v2(45.56,4279.43) J9.3@45.56,4221.56 ; v2(45.56,6445.57) J30.2@45.56,6503.44 ; v2@45.56,6542.7 v2(45.56,6540.45) J30.2@45.56,6503.44 ; v2@45.56,6682.3 v2(45.56,6684.55) J30.3@45.56,6721.56 ; v2(45.56,6779.43) J30.3@45.56,6721.56 ; v2(45.56,6945.57) J32.2@45.56,7003.44 ; v2@45.56,7042.7 v2(45.56,7040.45) J32.2@45.56,7003.44 ; v2@45.56,7182.3 v2(45.56,7184.55) J32.3@45.56,7221.56 ; v2(45.56,7279.43) J32.3@45.56,7221.56 ; v2(45.56,7445.57) J31.2@45.56,7503.44 ; v2@45.56,7542.7 v2(45.56,7540.45) J31.2@45.56,7503.44 ; v2@45.56,7682.3 v2(45.56,7684.55) J31.3@45.56,7721.56 ; v2(45.56,7779.43) J31.3@45.56,7721.56 ; v2(45.56,7945.57) J29.2@45.56,8003.44 ; v2@45.56,8042.7 v2(45.56,8040.45) J29.2@45.56,8003.44 ; v2@45.56,8182.3 v2(45.56,8184.55) J29.3@45.56,8221.56 ; v2(45.56,8279.43) J29.3@45.56,8221.56 ; v2(103.43,2445.57) J10.2@103.43,2503.44 ; v2@103.43,2542.7 v2(103.43,2540.45) J10.2@103.43,2503.44 ; v2@103.43,2682.3 v2(103.43,2684.55) J10.3@103.43,2721.56 ; v2(103.43,2779.43) J10.3@103.43,2721.56 ; v2(103.43,2945.57) J12.2@103.43,3003.44 ; v2@103.43,3042.7 v2(103.43,3040.45) J12.2@103.43,3003.44 ; v2@103.43,3182.3 v2(103.43,3184.55) J12.3@103.43,3221.56 ; v2(103.43,3279.43) J12.3@103.43,3221.56 ; v2(103.43,3445.57) J11.2@103.43,3503.44 ; v2@103.43,3542.7 v2(103.43,3540.45) J11.2@103.43,3503.44 ; v2@103.43,3682.3 v2(103.43,3684.55) J11.3@103.43,3721.56 ; v2(103.43,3779.43) J11.3@103.43,3721.56 ; v2(103.43,3945.57) J9.2@103.43,4003.44 ; v2@103.43,4042.7 v2(103.43,4040.45) J9.2@103.43,4003.44 ; v2@103.43,4182.3 v2(103.43,4184.55) J9.3@103.43,4221.56 ; v2(103.43,4279.43) J9.3@103.43,4221.56 ; v2(103.43,6445.57) J30.2@103.43,6503.44 ; v2@103.43,6542.7 v2(103.43,6540.45) J30.2@103.43,6503.44 ; v2@103.43,6682.3 v2(103.43,6684.55) J30.3@103.43,6721.56 ; v2(103.43,6779.43) J30.3@103.43,6721.56 ; v2(103.43,6945.57) J32.2@103.43,7003.44 ; v2@103.43,7042.7 v2(103.43,7040.45) J32.2@103.43,7003.44 ; v2@103.43,7182.3 v2(103.43,7184.55) J32.3@103.43,7221.56 ; v2(103.43,7279.43) J32.3@103.43,7221.56 ; v2(103.43,7445.57) J31.2@103.43,7503.44 ; v2@103.43,7542.7 v2(103.43,7540.45) J31.2@103.43,7503.44 ; v2@103.43,7682.3 v2(103.43,7684.55) J31.3@103.43,7721.56 ; v2(103.43,7779.43) J31.3@103.43,7721.56 ; v2(103.43,7945.57) J29.2@103.43,8003.44 ; v2@103.43,8042.7 v2(103.43,8040.45) J29.2@103.43,8003.44 ; v2@103.43,8182.3 v2(103.43,8184.55) J29.3@103.43,8221.56 ; v2(103.43,8279.43) J29.3@103.43,8221.56 ; v2@161,2543 v2(161,2540.75) 161,2503.74 J10.2@161.3,2503.44 ; v2@161,2682 v2(161,2684.25) 161,2721.26 J10.3@161.3,2721.56 ; v2@161,3043 v2(161,3040.75) 161,3003.74 J12.2@161.3,3003.44 ; v2@161,3182 v2(161,3184.25) 161,3221.26 J12.3@161.3,3221.56 ; v2@161,3543 v2(161,3540.75) 161,3503.74 J11.2@161.3,3503.44 ; v2@161,3682 v2(161,3684.25) 161,3721.26 J11.3@161.3,3721.56 ; v2@161,4043 v2(161,4040.75) 161,4003.74 J9.2@161.3,4003.44 ; v2@161,4182 v2(161,4184.25) 161,4221.26 J9.3@161.3,4221.56 ; v2@161,6543 v2(161,6540.75) 161,6503.74 J30.2@161.3,6503.44 ; v2@161,6682 v2(161,6684.25) 161,6721.26 J30.3@161.3,6721.56 ; v2@161,7043 v2(161,7040.75) 161,7003.74 J32.2@161.3,7003.44 ; v2@161,7182 v2(161,7184.25) 161,7221.26 J32.3@161.3,7221.56 ; v2@161,7543 v2(161,7540.75) 161,7503.74 J31.2@161.3,7503.44 ; v2@161,7682 v2(161,7684.25) 161,7721.26 J31.3@161.3,7721.56 ; v2@161,8043 v2(161,8040.75) 161,8003.74 J29.2@161.3,8003.44 ; v2@161,8182 v2(161,8184.25) 161,8221.26 J29.3@161.3,8221.56 ; v2(161.3,2445.57) J10.2@161.3,2503.44 ; v2(161.3,2779.43) J10.3@161.3,2721.56 ; v2(161.3,2945.57) J12.2@161.3,3003.44 ; v2(161.3,3279.43) J12.3@161.3,3221.56 ; v2(161.3,3445.57) J11.2@161.3,3503.44 ; v2(161.3,3779.43) J11.3@161.3,3721.56 ; v2(161.3,3945.57) J9.2@161.3,4003.44 ; v2(161.3,4279.43) J9.3@161.3,4221.56 ; v2(161.3,6445.57) J30.2@161.3,6503.44 ; v2(161.3,6779.43) J30.3@161.3,6721.56 ; v2(161.3,6945.57) J32.2@161.3,7003.44 ; v2(161.3,7279.43) J32.3@161.3,7221.56 ; v2(161.3,7445.57) J31.2@161.3,7503.44 ; v2(161.3,7779.43) J31.3@161.3,7721.56 ; v2(161.3,7945.57) J29.2@161.3,8003.44 ; v2(161.3,8279.43) J29.3@161.3,8221.56 ; J10.2@163.5,2503.44 v2(221.37,2503.44) ; J10.3@163.5,2721.56 v2(221.37,2721.56) ; J12.2@163.5,3003.44 v2(221.37,3003.44) ; J12.3@163.5,3221.56 v2(221.37,3221.56) ; J11.2@163.5,3503.44 v2(221.37,3503.44) ; J11.3@163.5,3721.56 v2(221.37,3721.56) ; J9.2@163.5,4003.44 v2(221.37,4003.44) ; J9.3@163.5,4221.56 v2(221.37,4221.56) ; J30.2@163.5,6503.44 v2(221.37,6503.44) ; J30.3@163.5,6721.56 v2(221.37,6721.56) ; J32.2@163.5,7003.44 v2(221.37,7003.44) ; J32.3@163.5,7221.56 v2(221.37,7221.56) ; J31.2@163.5,7503.44 v2(221.37,7503.44) ; J31.3@163.5,7721.56 v2(221.37,7721.56) ; J29.2@163.5,8003.44 v4(221.37,8003.44) ; J29.3@163.5,8221.56 v2(221.37,8221.56) ; C133.1@434.1,933.29 v3(434.1,977.79) ; S5.3@477.76,1659.56 487.29,1650.02 v3(487.29,1600.29) v3@487.29,1597.79 ; v3@486.89,1597.79 v3@486.89,1598.19 ; v3(490.66,1078.66) D11.2@567.86,1078.66 v3(567.86,1145.86) ; v3(552.66,2002.75) C96.2@552.66,2047.25 ; v2(580.57,8999.7) J26.2@638.44,8999.7 ; v2(580.57,9057.57) J26.2@638.44,9057.57 ; v2(580.57,9115.44) J26.2@638.44,9115.44 ; v2(638.44,8939.63) J26.2@638.44,8997.5 ; v3(657.75,1207) C132.1@701.5,1207 ; v2@677.7,9057.57 v2(675.45,9057.57) J26.2@638.44,9057.57 ; v2@677.7,9115.44 v2(675.45,9115.44) J26.2@638.44,9115.44 ; v2@678,9000 v2(675.75,9000) 638.74,9000 J26.2@638.44,8999.7 ; C134.1@689.47,1085.72 v3(689.47,1129.47) ; C131.2@755.13,1079.94 v3(755.13,1131.87) ; v2@817,9000 v2(819.25,9000) 856.26,9000 J26.3@856.56,8999.7 ; v2@817.3,9057.57 v2(819.55,9057.57) J26.3@856.56,9057.57 ; v2@817.3,9115.44 v2(819.55,9115.44) J26.3@856.56,9115.44 ; S5.4@836.02,1659.56 845.56,1650.02 845.56,1603.6 v3@848.47,1600.69 ; v2(856.56,8939.63) J26.3@856.56,8997.5 ; v2(914.43,8999.7) J26.3@856.56,8999.7 ; v2(914.43,9057.57) J26.3@856.56,9057.57 ; v2(914.43,9115.44) J26.3@856.56,9115.44 ; v3(939.46,1042.87) C129.1@939.46,1086.62 ; v7(1012.71,743) C135.2@1012.71,780.35 ; C136.2@1017.71,533.35 v7(1017.71,570.7) ; C130.2@1039,1204.51 v3(1082.75,1204.51) ; v2(1080.57,8999.7) J28.2@1138.44,8999.7 ; v2(1080.57,9057.57) J28.2@1138.44,9057.57 ; v2(1080.57,9115.44) J28.2@1138.44,9115.44 ; v2(1138.44,8939.63) J28.2@1138.44,8997.5 ; v2@1177.7,9057.57 v2(1175.45,9057.57) J28.2@1138.44,9057.57 ; v2@1177.7,9115.44 v2(1175.45,9115.44) J28.2@1138.44,9115.44 ; v2@1178,9000 v2(1175.75,9000) 1138.74,9000 J28.2@1138.44,8999.7 ; C137.1@1217.71,213.35 C137.1@1218.71,214.35 ; C137.1@1217.71,215.35 C137.1@1218.71,214.35 ; 1218.71,158 v7(1218.71,175.77) C137.1@1218.71,214.35 ; C140.1@1305.71,782.35 1305.71,829.85 v7(1307.71,831.85) ; v2@1317,9000 v2(1319.25,9000) 1356.26,9000 J28.3@1356.56,8999.7 ; v2@1317.3,9057.57 v2(1319.55,9057.57) J28.3@1356.56,9057.57 ; v2@1317.3,9115.44 v2(1319.55,9115.44) J28.3@1356.56,9115.44 ; C138.1@1326.71,214.35 C138.1@1327.71,215.35 v7(1327.71,176.77) 1327.71,155 ; v2(1356.56,8939.63) J28.3@1356.56,8997.5 ; v2(1414.43,8999.7) J28.3@1356.56,8999.7 ; v2(1414.43,9057.57) J28.3@1356.56,9057.57 ; v2(1414.43,9115.44) J28.3@1356.56,9115.44 ; v2(1580.57,8999.7) J27.2@1638.44,8999.7 ; v2(1580.57,9057.57) J27.2@1638.44,9057.57 ; v2(1580.57,9115.44) J27.2@1638.44,9115.44 ; v2(1638.44,8939.63) J27.2@1638.44,8997.5 ; C89.1@1642.82,2520.22 v3(1642.82,2564.18) ; v2@1677.7,9057.57 v2(1675.45,9057.57) J27.2@1638.44,9057.57 ; v2@1677.7,9115.44 v2(1675.45,9115.44) J27.2@1638.44,9115.44 ; v2@1678,9000 v2(1675.75,9000) 1638.74,9000 J27.2@1638.44,8999.7 ; C142.1@1687.71,215.35 v7(1726.29,215.35) ; v2@1817,9000 v2(1819.25,9000) 1856.26,9000 J27.3@1856.56,8999.7 ; v2@1817.3,9057.57 v2(1819.55,9057.57) J27.3@1856.56,9057.57 ; v2@1817.3,9115.44 v2(1819.55,9115.44) J27.3@1856.56,9115.44 ; v7(1822.71,176.77) C143.1@1822.71,215.35 ; v2(1856.56,8939.63) J27.3@1856.56,8997.5 ; Q2.2@1858.17,2349.5 1915.05,2292.61 v3(1915.05,2276.57) 1862.4,2276.57 C90.2@1862.03,2276.2 ; R62.1@1862.03,2211.2 1862.4,2211.57 v3(1914.05,2211.56) ; v7(1877.05,176.77) C141.1@1877.05,215.35 ; v2(1914.43,8999.7) J27.3@1856.56,8999.7 ; v2(1914.43,9057.57) J27.3@1856.56,9057.57 ; v2(1914.43,9115.44) J27.3@1856.56,9115.44 ; v2(2080.57,8999.7) 2138.44,8999.7 J25.2@2138.44,9057.57 ; v2(2080.57,9057.57) J25.2@2138.44,9057.57 ; v2(2080.57,9115.44) J25.2@2138.44,9115.44 ; v2(2138.44,8939.63) J25.2@2138.44,8997.5 ; J25.2@2138.74,9000 v2(2175.75,9000) v2@2178,9000 ; v2@2177.7,9057.57 v2(2175.45,9057.57) J25.2@2138.44,9057.57 ; v2@2177.7,9115.44 v2(2175.45,9115.44) J25.2@2138.44,9115.44 ; v3(2294.75,2493.21) R69.1@2294.75,2531.71 ; v2@2317,9000 v2(2319.25,9000) 2356.26,9000 J25.3@2356.56,8999.7 ; v2@2317.3,9057.57 v2(2319.55,9057.57) J25.3@2356.56,9057.57 ; v2@2317.3,9115.44 v2(2319.55,9115.44) J25.3@2356.56,9115.44 ; v2(2356.56,8939.63) J25.3@2356.56,8997.5 ; v2(2414.43,8999.7) J25.3@2356.56,8999.7 ; v2(2414.43,9057.57) J25.3@2356.56,9057.57 ; v2(2414.43,9115.44) J25.3@2356.56,9115.44 ; C94.2@2440.5,2361 v3(2440.5,2403.45) ; v3(2460.55,1300.6) 2517.99,1300.6 R65.1@2522.76,1295.82 ; v3(2464,2066) R72.1@2521.21,2066.05 ; v3(2485.01,548.55) R53.1@2523.52,548.55 ; C50.2@2840.69,5578.3 v3(2887.76,5578.3) ; C32.2@2946.81,4963.91 v1(2972.59,4989.69) ; v3(3029.5,2417.5) C95.2@3074,2417.5 ; v3(3031.5,903.5) C88.2@3076,903.5 ; v3(3038.5,1648.5) C91.2@3083,1648.5 ; v1(3059.48,5767.23) 3071.97,5779.72 v3(3114.27,5779.72) ; v3(3149.57,5938.03) C59.2@3149.57,5973.89 ; R42.1@3539,3423 v4(3570.1,3423) ; v3(3642.84,3624.84) C83.2@3696.14,3624.84 ; v7(3648.46,3457.73) Y3.2@3693.86,3457.73 ; v3(3706.73,6295.69) C35.2@3706.73,6344.14 ; v3@3729.54,3015.46 C87.2@3729.54,3058.21 ; v3(3833.61,6385.22) C29.2@3833.61,6433.67 ; v3(3894.97,3382.66) Y1.4@3946.72,3382.66 ; Y2.2@3989.9,3126.73 v3(3989.9,3178.48) ; C82.2@3991.36,2985.56 4018.44,2985.56 4034,2970 v3(4045,2970) ; v3(4036.32,5247.23) C53.2@4084.77,5247.23 ; R45.2@4070.43,3108.93 v3(4070.43,3160.68) ; v3(4133,5443.04) C44.2@4133,5478.47 ; C81.2@4195.69,3166.46 v3(4247.44,3166.46) ; v2(4580.57,8999.7) 4638.44,8999.7 J6.2@4638.44,9057.57 ; v2(4580.57,9057.57) J6.2@4638.44,9057.57 ; v2(4580.57,9115.44) J6.2@4638.44,9115.44 ; v2(4638.44,8939.63) J6.2@4638.44,8997.5 ; J6.2@4638.74,9000 v2(4675.75,9000) v2@4678,9000 ; v2@4677.7,9057.57 v2(4675.45,9057.57) J6.2@4638.44,9057.57 ; v2@4677.7,9115.44 v2(4675.45,9115.44) J6.2@4638.44,9115.44 ; D5.2@4734.4,2062.98 v7(4808.79,2062.98) ; D3.2@4736.22,1983.98 v7(4810.61,1983.98) ; D4.2@4737.54,1909.24 v7(4811.93,1909.24) ; v2@4817,9000 v2(4819.25,9000) 4856.26,9000 J6.3@4856.56,8999.7 ; v2@4817.3,9057.57 v2(4819.55,9057.57) J6.3@4856.56,9057.57 ; v2@4817.3,9115.44 v2(4819.55,9115.44) J6.3@4856.56,9115.44 ; v2(4856.56,8939.63) J6.3@4856.56,8997.5 ; v2(4914.43,8999.7) J6.3@4856.56,8999.7 ; v2(4914.43,9057.57) J6.3@4856.56,9057.57 ; v2(4914.43,9115.44) J6.3@4856.56,9115.44 ; v3(4947.5,5061.5) C6.1@4947.5,5104 ; v3(4947.5,5146.5) C6.1@4947.5,5104 ; v3(4990,5104) C6.1@4947.5,5104 ; v3@5017.76,1338.08 C21.1@5017.76,1369.18 ; v2(5080.57,8999.7) 5138.44,8999.7 J7.2@5138.44,9057.57 ; v2(5080.57,9057.57) J7.2@5138.44,9057.57 ; v2(5080.57,9115.44) J7.2@5138.44,9115.44 ; v2(5138.44,8939.63) J7.2@5138.44,8997.5 ; J7.2@5138.74,9000 v2(5175.75,9000) v2@5178,9000 ; v2@5177.7,9057.57 v2(5175.45,9057.57) J7.2@5138.44,9057.57 ; v2@5177.7,9115.44 v2(5175.45,9115.44) J7.2@5138.44,9115.44 ; v2@5317,9000 v2(5319.25,9000) 5356.26,9000 J7.3@5356.56,8999.7 ; v2@5317.3,9057.57 v2(5319.55,9057.57) J7.3@5356.56,9057.57 ; v2@5317.3,9115.44 v2(5319.55,9115.44) J7.3@5356.56,9115.44 ; v2(5356.56,8939.63) J7.3@5356.56,8997.5 ; v2(5414.43,8999.7) J7.3@5356.56,8999.7 ; v2(5414.43,9057.57) J7.3@5356.56,9057.57 ; v2(5414.43,9115.44) J7.3@5356.56,9115.44 ; v2(5580.57,8999.7) 5638.44,8999.7 J5.2@5638.44,9057.57 ; v2(5580.57,9057.57) J5.2@5638.44,9057.57 ; v2(5580.57,9115.44) J5.2@5638.44,9115.44 ; v2(5638.44,8939.63) J5.2@5638.44,8997.5 ; J5.2@5638.74,9000 v2(5675.75,9000) v2@5678,9000 ; v8(5673.9,1327) v8@5673.9,1329.2 ; v2@5677.7,9057.57 v2(5675.45,9057.57) J5.2@5638.44,9057.57 ; v2@5677.7,9115.44 v2(5675.45,9115.44) J5.2@5638.44,9115.44 ; v3(5804.66,783.72) D1.2@5866.47,783.72 D1.2@5866.47,785 ; v2@5817,9000 v2(5819.25,9000) 5856.26,9000 J5.3@5856.56,8999.7 ; v2@5817.3,9057.57 v2(5819.55,9057.57) J5.3@5856.56,9057.57 ; v2@5817.3,9115.44 v2(5819.55,9115.44) J5.3@5856.56,9115.44 ; v2(5856.56,8939.63) J5.3@5856.56,8997.5 ; D1.2@5866,785 D1.2@5866.47,785 ; v3(5866.47,845.53) D1.2@5866.47,785 ; v2(5914.43,8999.7) J5.3@5856.56,8999.7 ; v2(5914.43,9057.57) J5.3@5856.56,9057.57 ; v2(5914.43,9115.44) J5.3@5856.56,9115.44 ; v3(5927.81,785) D1.2@5866.47,785 ; v3(6029.53,288.86) D2.2@6091.34,288.86 ; v2(6080.57,8999.7) 6138.44,8999.7 J4.2@6138.44,9057.57 ; v2(6080.57,9057.57) J4.2@6138.44,9057.57 ; v2(6080.57,9115.44) J4.2@6138.44,9115.44 ; v3(6091.34,227.05) D2.2@6091.34,288.86 ; v2(6138.44,8939.63) J4.2@6138.44,8997.5 ; J4.2@6138.74,9000 v2(6175.75,9000) v2@6178,9000 ; v3(6153.15,288.86) D2.2@6091.34,288.86 ; v2@6177.7,9057.57 v2(6175.45,9057.57) J4.2@6138.44,9057.57 ; v2@6177.7,9115.44 v2(6175.45,9115.44) J4.2@6138.44,9115.44 ; v2@6317,9000 v2(6319.25,9000) 6356.26,9000 J4.3@6356.56,8999.7 ; v2@6317.3,9057.57 v2(6319.55,9057.57) J4.3@6356.56,9057.57 ; v2@6317.3,9115.44 v2(6319.55,9115.44) J4.3@6356.56,9115.44 ; v2(6356.56,8939.63) J4.3@6356.56,8997.5 ; v2(6414.43,8999.7) J4.3@6356.56,8999.7 ; v2(6414.43,9057.57) J4.3@6356.56,9057.57 ; v2(6414.43,9115.44) J4.3@6356.56,9115.44 ; v2(6777.83,2503.44) J13.3@6838.7,2503.44 ; v2(6777.83,2721.56) J13.2@6838.7,2721.56 ; v2(6777.83,3003.44) J15.3@6838.7,3003.44 ; v2(6777.83,3221.56) J15.2@6838.7,3221.56 ; v2(6777.83,3503.44) J16.3@6838.7,3503.44 ; v2(6777.83,3721.56) J16.2@6838.7,3721.56 ; v2(6777.83,4003.44) J14.3@6838.7,4003.44 ; v2(6777.83,4221.56) J14.2@6838.7,4221.56 ; v2(6777.83,4503.44) J18.3@6838.7,4503.44 ; v2(6777.83,4721.56) J18.2@6838.7,4721.56 ; v2(6777.83,5003.44) J20.3@6838.7,5003.44 ; v2(6777.83,5221.56) J20.2@6838.7,5221.56 ; v2(6777.83,5503.44) J19.3@6838.7,5503.44 ; v2(6777.83,5721.56) J19.2@6838.7,5721.56 ; v2(6777.83,6003.44) J17.3@6838.7,6003.44 ; v2(6777.83,6221.56) J17.2@6838.7,6221.56 ; v2(6777.83,6503.44) J21.3@6838.7,6503.44 ; v2(6777.83,6721.56) J21.2@6838.7,6721.56 ; v2(6777.83,7003.44) J23.3@6838.7,7003.44 ; v2(6777.83,7221.56) J23.2@6838.7,7221.56 ; v2(6777.83,7503.44) J24.3@6838.7,7503.44 ; v2(6777.83,7721.56) J24.2@6838.7,7721.56 ; v2(6777.83,8003.44) J22.3@6838.7,8003.44 ; v2(6777.83,8221.56) J22.2@6838.7,8221.56 ; v2(6778.63,770.94) J3.3@6836.5,770.94 ; v2(6778.63,989.06) J3.2@6836.5,989.06 ; v2(6778.63,1380.94) J2.3@6836.5,1380.94 ; v2(6778.63,1599.06) J2.2@6836.5,1599.06 ; v2(6838.7,713.07) 6838.7,770.94 J3.3@6896.57,770.94 ; v2(6838.7,1046.93) 6838.7,989.06 J3.2@6896.57,989.06 ; v2(6838.7,1323.07) 6838.7,1380.94 J2.3@6896.57,1380.94 ; v2(6838.7,1656.93) 6838.7,1599.06 J2.2@6896.57,1599.06 ; v2(6838.7,2445.57) J13.3@6838.7,2503.44 ; v2(6838.7,2779.43) J13.2@6838.7,2721.56 ; v2(6838.7,2945.57) J15.3@6838.7,3003.44 ; v2(6838.7,3279.43) J15.2@6838.7,3221.56 ; v2(6838.7,3445.57) J16.3@6838.7,3503.44 ; v2(6838.7,3779.43) J16.2@6838.7,3721.56 ; v2(6838.7,3945.57) J14.3@6838.7,4003.44 ; v2(6838.7,4279.43) J14.2@6838.7,4221.56 ; v2(6838.7,4445.57) J18.3@6838.7,4503.44 ; v2(6838.7,4779.43) J18.2@6838.7,4721.56 ; v2(6838.7,4945.57) J20.3@6838.7,5003.44 ; v2(6838.7,5279.43) J20.2@6838.7,5221.56 ; v2(6838.7,5445.57) J19.3@6838.7,5503.44 ; v2(6838.7,5779.43) J19.2@6838.7,5721.56 ; v2(6838.7,5945.57) J17.3@6838.7,6003.44 ; v2(6838.7,6279.43) J17.2@6838.7,6221.56 ; v2(6838.7,6445.57) J21.3@6838.7,6503.44 ; v2(6838.7,6779.43) J21.2@6838.7,6721.56 ; v2(6838.7,6945.57) J23.3@6838.7,7003.44 ; v2(6838.7,7279.43) J23.2@6838.7,7221.56 ; v2(6838.7,7445.57) J24.3@6838.7,7503.44 ; v2(6838.7,7779.43) J24.2@6838.7,7721.56 ; v2(6838.7,7945.57) J22.3@6838.7,8003.44 ; v2(6838.7,8279.43) J22.2@6838.7,8221.56 ; v2@6839,2543 v2(6839,2540.75) 6839,2503.74 J13.3@6838.7,2503.44 ; v2@6839,2682 v2(6839,2684.25) 6839,2721.26 J13.2@6838.7,2721.56 ; v2@6839,3043 v2(6839,3040.75) 6839,3003.74 J15.3@6838.7,3003.44 ; v2@6839,3182 v2(6839,3184.25) 6839,3221.26 J15.2@6838.7,3221.56 ; v2@6839,3543 v2(6839,3540.75) 6839,3503.74 J16.3@6838.7,3503.44 ; v2@6839,3682 v2(6839,3684.25) 6839,3721.26 J16.2@6838.7,3721.56 ; v2@6839,4043 v2(6839,4040.75) 6839,4003.74 J14.3@6838.7,4003.44 ; v2@6839,4182 v2(6839,4184.25) 6839,4221.26 J14.2@6838.7,4221.56 ; v2@6839,4543 v2(6839,4540.75) 6839,4503.74 J18.3@6838.7,4503.44 ; v2@6839,4682 v2(6839,4684.25) 6839,4721.26 J18.2@6838.7,4721.56 ; v2@6839,5043 v2(6839,5040.75) 6839,5003.74 J20.3@6838.7,5003.44 ; v2@6839,5182 v2(6839,5184.25) 6839,5221.26 J20.2@6838.7,5221.56 ; v2@6839,5543 v2(6839,5540.75) 6839,5503.74 J19.3@6838.7,5503.44 ; v2@6839,5682 v2(6839,5684.25) 6839,5721.26 J19.2@6838.7,5721.56 ; v2@6839,6043 v2(6839,6040.75) 6839,6003.74 J17.3@6838.7,6003.44 ; v2@6839,6182 v2(6839,6184.25) 6839,6221.26 J17.2@6838.7,6221.56 ; v2@6839,6543 v2(6839,6540.75) 6839,6503.74 J21.3@6838.7,6503.44 ; v2@6839,6682 v2(6839,6684.25) 6839,6721.26 J21.2@6838.7,6721.56 ; v2@6839,7043 v2(6839,7040.75) 6839,7003.74 J23.3@6838.7,7003.44 ; v2@6839,7182 v2(6839,7184.25) 6839,7221.26 J23.2@6838.7,7221.56 ; v2@6839,7543 v2(6839,7540.75) 6839,7503.74 J24.3@6838.7,7503.44 ; v2@6839,7682 v2(6839,7684.25) 6839,7721.26 J24.2@6838.7,7721.56 ; v2@6839,8043 v2(6839,8040.75) 6839,8003.74 J22.3@6838.7,8003.44 ; v2@6839,8182 v2(6839,8184.25) 6839,8221.26 J22.2@6838.7,8221.56 ; v2(6896.57,713.07) J3.3@6896.57,770.94 ; v2(6896.57,1046.93) J3.2@6896.57,989.06 ; v2(6896.57,1323.07) J2.3@6896.57,1380.94 ; v2(6896.57,1656.93) J2.2@6896.57,1599.06 ; v2(6896.57,2445.57) J13.3@6896.57,2503.44 ; v2@6896.57,2542.7 v2(6896.57,2540.45) J13.3@6896.57,2503.44 ; v2@6896.57,2682.3 v2(6896.57,2684.55) J13.2@6896.57,2721.56 ; v2(6896.57,2779.43) J13.2@6896.57,2721.56 ; v2(6896.57,2945.57) J15.3@6896.57,3003.44 ; v2@6896.57,3042.7 v2(6896.57,3040.45) J15.3@6896.57,3003.44 ; v2@6896.57,3182.3 v2(6896.57,3184.55) J15.2@6896.57,3221.56 ; v2(6896.57,3279.43) J15.2@6896.57,3221.56 ; v2(6896.57,3445.57) J16.3@6896.57,3503.44 ; v2@6896.57,3542.7 v2(6896.57,3540.45) J16.3@6896.57,3503.44 ; v2@6896.57,3682.3 v2(6896.57,3684.55) J16.2@6896.57,3721.56 ; v2(6896.57,3779.43) J16.2@6896.57,3721.56 ; v2(6896.57,3945.57) J14.3@6896.57,4003.44 ; v2@6896.57,4042.7 v2(6896.57,4040.45) J14.3@6896.57,4003.44 ; v2@6896.57,4182.3 v2(6896.57,4184.55) J14.2@6896.57,4221.56 ; v2(6896.57,4279.43) J14.2@6896.57,4221.56 ; v2(6896.57,4445.57) J18.3@6896.57,4503.44 ; v2@6896.57,4542.7 v2(6896.57,4540.45) J18.3@6896.57,4503.44 ; v2@6896.57,4682.3 v2(6896.57,4684.55) J18.2@6896.57,4721.56 ; v2(6896.57,4779.43) J18.2@6896.57,4721.56 ; v2(6896.57,4945.57) J20.3@6896.57,5003.44 ; v2@6896.57,5042.7 v2(6896.57,5040.45) J20.3@6896.57,5003.44 ; v2@6896.57,5182.3 v2(6896.57,5184.55) J20.2@6896.57,5221.56 ; v2(6896.57,5279.43) J20.2@6896.57,5221.56 ; v2(6896.57,5445.57) J19.3@6896.57,5503.44 ; v2@6896.57,5542.7 v2(6896.57,5540.45) J19.3@6896.57,5503.44 ; v2@6896.57,5682.3 v2(6896.57,5684.55) J19.2@6896.57,5721.56 ; v2(6896.57,5779.43) J19.2@6896.57,5721.56 ; v2(6896.57,5945.57) J17.3@6896.57,6003.44 ; v2@6896.57,6042.7 v2(6896.57,6040.45) J17.3@6896.57,6003.44 ; v2@6896.57,6182.3 v2(6896.57,6184.55) J17.2@6896.57,6221.56 ; v2(6896.57,6279.43) J17.2@6896.57,6221.56 ; v2(6896.57,6445.57) J21.3@6896.57,6503.44 ; v2@6896.57,6542.7 v2(6896.57,6540.45) J21.3@6896.57,6503.44 ; v2@6896.57,6682.3 v2(6896.57,6684.55) J21.2@6896.57,6721.56 ; v2(6896.57,6779.43) J21.2@6896.57,6721.56 ; v2(6896.57,6945.57) J23.3@6896.57,7003.44 ; v2@6896.57,7042.7 v2(6896.57,7040.45) J23.3@6896.57,7003.44 ; v2@6896.57,7182.3 v2(6896.57,7184.55) J23.2@6896.57,7221.56 ; v2(6896.57,7279.43) J23.2@6896.57,7221.56 ; v2(6896.57,7445.57) J24.3@6896.57,7503.44 ; v2@6896.57,7542.7 v2(6896.57,7540.45) J24.3@6896.57,7503.44 ; v2@6896.57,7682.3 v2(6896.57,7684.55) J24.2@6896.57,7721.56 ; v2(6896.57,7779.43) J24.2@6896.57,7721.56 ; v2(6896.57,7945.57) J22.3@6896.57,8003.44 ; v2@6896.57,8042.7 v2(6896.57,8040.45) J22.3@6896.57,8003.44 ; v2@6896.57,8182.3 v2(6896.57,8184.55) J22.2@6896.57,8221.56 ; v2(6896.57,8279.43) J22.2@6896.57,8221.56 ; v2(6954.44,713.07) 6954.44,770.94 J3.3@6896.57,770.94 ; v2(6954.44,1046.93) 6954.44,989.06 J3.2@6896.57,989.06 ; v2(6954.44,1323.07) 6954.44,1380.94 J2.3@6896.57,1380.94 ; v2(6954.44,1656.93) 6954.44,1599.06 J2.2@6896.57,1599.06 ; v2(6954.44,2445.57) J13.3@6954.44,2503.44 ; v2@6954.44,2542.7 v2(6954.44,2540.45) J13.3@6954.44,2503.44 ; v2@6954.44,2682.3 v2(6954.44,2684.55) J13.2@6954.44,2721.56 ; v2(6954.44,2779.43) J13.2@6954.44,2721.56 ; v2(6954.44,2945.57) J15.3@6954.44,3003.44 ; v2@6954.44,3042.7 v2(6954.44,3040.45) J15.3@6954.44,3003.44 ; v2@6954.44,3182.3 v2(6954.44,3184.55) J15.2@6954.44,3221.56 ; v2(6954.44,3279.43) J15.2@6954.44,3221.56 ; v2(6954.44,3445.57) J16.3@6954.44,3503.44 ; v2@6954.44,3542.7 v2(6954.44,3540.45) J16.3@6954.44,3503.44 ; v2@6954.44,3682.3 v2(6954.44,3684.55) J16.2@6954.44,3721.56 ; v2(6954.44,3779.43) J16.2@6954.44,3721.56 ; v2(6954.44,3945.57) J14.3@6954.44,4003.44 ; v2@6954.44,4042.7 v2(6954.44,4040.45) J14.3@6954.44,4003.44 ; v2@6954.44,4182.3 v2(6954.44,4184.55) J14.2@6954.44,4221.56 ; v2(6954.44,4279.43) J14.2@6954.44,4221.56 ; v2(6954.44,4445.57) J18.3@6954.44,4503.44 ; v2@6954.44,4542.7 v2(6954.44,4540.45) J18.3@6954.44,4503.44 ; v2@6954.44,4682.3 v2(6954.44,4684.55) J18.2@6954.44,4721.56 ; v2(6954.44,4779.43) J18.2@6954.44,4721.56 ; v2(6954.44,4945.57) J20.3@6954.44,5003.44 ; v2@6954.44,5042.7 v2(6954.44,5040.45) J20.3@6954.44,5003.44 ; v2@6954.44,5182.3 v2(6954.44,5184.55) J20.2@6954.44,5221.56 ; v2(6954.44,5279.43) J20.2@6954.44,5221.56 ; v2(6954.44,5445.57) J19.3@6954.44,5503.44 ; v2@6954.44,5542.7 v2(6954.44,5540.45) J19.3@6954.44,5503.44 ; v2@6954.44,5682.3 v2(6954.44,5684.55) J19.2@6954.44,5721.56 ; v2(6954.44,5779.43) J19.2@6954.44,5721.56 ; v2(6954.44,5945.57) J17.3@6954.44,6003.44 ; v2@6954.44,6042.7 v2(6954.44,6040.45) J17.3@6954.44,6003.44 ; v2@6954.44,6182.3 v2(6954.44,6184.55) J17.2@6954.44,6221.56 ; v2(6954.44,6279.43) J17.2@6954.44,6221.56 ; v2(6954.44,6445.57) J21.3@6954.44,6503.44 ; v2@6954.44,6542.7 v2(6954.44,6540.45) J21.3@6954.44,6503.44 ; v2@6954.44,6682.3 v2(6954.44,6684.55) J21.2@6954.44,6721.56 ; v2(6954.44,6779.43) J21.2@6954.44,6721.56 ; v2(6954.44,6945.57) J23.3@6954.44,7003.44 ; v2@6954.44,7042.7 v2(6954.44,7040.45) J23.3@6954.44,7003.44 ; v2@6954.44,7182.3 v2(6954.44,7184.55) J23.2@6954.44,7221.56 ; v2(6954.44,7279.43) J23.2@6954.44,7221.56 ; v2(6954.44,7445.57) J24.3@6954.44,7503.44 ; v2@6954.44,7542.7 v2(6954.44,7540.45) J24.3@6954.44,7503.44 ; v2@6954.44,7682.3 v2(6954.44,7684.55) J24.2@6954.44,7721.56 ; v2(6954.44,7779.43) J24.2@6954.44,7721.56 ; v2(6954.44,7945.57) J22.3@6954.44,8003.44 ; v2@6954.44,8042.7 v2(6954.44,8040.45) J22.3@6954.44,8003.44 ; v2@6954.44,8182.3 v2(6954.44,8184.55) J22.2@6954.44,8221.56 ; v2(6954.44,8279.43) J22.2@6954.44,8221.56 ; J10.2@45.56,2503.44 J10.2@103.43,2503.44 ; J10.3@45.56,2721.56 J10.3@103.43,2721.56 ; J12.2@45.56,3003.44 J12.2@103.43,3003.44 ; J12.3@45.56,3221.56 J12.3@103.43,3221.56 ; J11.2@45.56,3503.44 J11.2@103.43,3503.44 ; J11.3@45.56,3721.56 J11.3@103.43,3721.56 ; J9.2@45.56,4003.44 J9.2@103.43,4003.44 ; J9.3@45.56,4221.56 J9.3@103.43,4221.56 ; J30.2@45.56,6503.44 J30.2@103.43,6503.44 ; J30.3@45.56,6721.56 J30.3@103.43,6721.56 ; J32.2@45.56,7003.44 J32.2@103.43,7003.44 ; J32.3@45.56,7221.56 J32.3@103.43,7221.56 ; J31.2@45.56,7503.44 J31.2@103.43,7503.44 ; J31.3@45.56,7721.56 J31.3@103.43,7721.56 ; J29.2@45.56,8003.44 J29.2@103.43,8003.44 ; J29.3@45.56,8221.56 J29.3@103.43,8221.56 ; J10.2@103.43,2503.44 J10.2@161.3,2503.44 ; J10.3@103.43,2721.56 J10.3@161.3,2721.56 ; J12.2@103.43,3003.44 J12.2@161.3,3003.44 ; J12.3@103.43,3221.56 J12.3@161.3,3221.56 ; J11.2@103.43,3503.44 J11.2@161.3,3503.44 ; J11.3@103.43,3721.56 J11.3@161.3,3721.56 ; J9.2@103.43,4003.44 J9.2@161.3,4003.44 ; J9.3@103.43,4221.56 J9.3@161.3,4221.56 ; J30.2@103.43,6503.44 J30.2@161.3,6503.44 ; J30.3@103.43,6721.56 J30.3@161.3,6721.56 ; J32.2@103.43,7003.44 J32.2@161.3,7003.44 ; J32.3@103.43,7221.56 J32.3@161.3,7221.56 ; J31.2@103.43,7503.44 J31.2@161.3,7503.44 ; J31.3@103.43,7721.56 J31.3@161.3,7721.56 ; J29.2@103.43,8003.44 J29.2@161.3,8003.44 ; J29.3@103.43,8221.56 J29.3@161.3,8221.56 ; J26.2@638.44,8999.7 J26.2@638.44,9057.57 ; J26.2@638.44,9057.57 J26.2@638.44,9115.44 ; J26.3@856.56,8999.7 J26.3@856.56,9057.57 ; J26.3@856.56,9057.57 J26.3@856.56,9115.44 ; J28.2@1138.44,8999.7 J28.2@1138.44,9057.57 ; J28.2@1138.44,9057.57 J28.2@1138.44,9115.44 ; J28.3@1356.56,8999.7 J28.3@1356.56,9057.57 ; J28.3@1356.56,9057.57 J28.3@1356.56,9115.44 ; J27.2@1638.44,8999.7 J27.2@1638.44,9057.57 ; J27.2@1638.44,9057.57 J27.2@1638.44,9115.44 ; J27.3@1856.56,8999.7 J27.3@1856.56,9057.57 ; J27.3@1856.56,9057.57 J27.3@1856.56,9115.44 ; J25.2@2138.44,9057.57 J25.2@2138.44,9115.44 ; J25.3@2356.56,8999.7 J25.3@2356.56,9057.57 ; J25.3@2356.56,9057.57 J25.3@2356.56,9115.44 ; J6.2@4638.44,9057.57 J6.2@4638.44,9115.44 ; J6.3@4856.56,8999.7 J6.3@4856.56,9057.57 ; J6.3@4856.56,9057.57 J6.3@4856.56,9115.44 ; J7.2@5138.44,9057.57 J7.2@5138.44,9115.44 ; J7.3@5356.56,8999.7 J7.3@5356.56,9057.57 ; J7.3@5356.56,9057.57 J7.3@5356.56,9115.44 ; J5.2@5638.44,9057.57 J5.2@5638.44,9115.44 ; J5.3@5856.56,8999.7 J5.3@5856.56,9057.57 ; J5.3@5856.56,9057.57 J5.3@5856.56,9115.44 ; J4.2@6138.44,9057.57 J4.2@6138.44,9115.44 ; J4.3@6356.56,8999.7 J4.3@6356.56,9057.57 ; J4.3@6356.56,9057.57 J4.3@6356.56,9115.44 ; J13.3@6838.7,2503.44 J13.3@6896.57,2503.44 ; J13.2@6838.7,2721.56 J13.2@6896.57,2721.56 ; J15.3@6838.7,3003.44 J15.3@6896.57,3003.44 ; J15.2@6838.7,3221.56 J15.2@6896.57,3221.56 ; J16.3@6838.7,3503.44 J16.3@6896.57,3503.44 ; J16.2@6838.7,3721.56 J16.2@6896.57,3721.56 ; J14.3@6838.7,4003.44 J14.3@6896.57,4003.44 ; J14.2@6838.7,4221.56 J14.2@6896.57,4221.56 ; J18.3@6838.7,4503.44 J18.3@6896.57,4503.44 ; J18.2@6838.7,4721.56 J18.2@6896.57,4721.56 ; J20.3@6838.7,5003.44 J20.3@6896.57,5003.44 ; J20.2@6838.7,5221.56 J20.2@6896.57,5221.56 ; J19.3@6838.7,5503.44 J19.3@6896.57,5503.44 ; J19.2@6838.7,5721.56 J19.2@6896.57,5721.56 ; J17.3@6838.7,6003.44 J17.3@6896.57,6003.44 ; J17.2@6838.7,6221.56 J17.2@6896.57,6221.56 ; J21.3@6838.7,6503.44 J21.3@6896.57,6503.44 ; J21.2@6838.7,6721.56 J21.2@6896.57,6721.56 ; J23.3@6838.7,7003.44 J23.3@6896.57,7003.44 ; J23.2@6838.7,7221.56 J23.2@6896.57,7221.56 ; J24.3@6838.7,7503.44 J24.3@6896.57,7503.44 ; J24.2@6838.7,7721.56 J24.2@6896.57,7721.56 ; J22.3@6838.7,8003.44 J22.3@6896.57,8003.44 ; J22.2@6838.7,8221.56 J22.2@6896.57,8221.56 ; J13.3@6896.57,2503.44 J13.3@6954.44,2503.44 ; J13.2@6896.57,2721.56 J13.2@6954.44,2721.56 ; J15.3@6896.57,3003.44 J15.3@6954.44,3003.44 ; J15.2@6896.57,3221.56 J15.2@6954.44,3221.56 ; J16.3@6896.57,3503.44 J16.3@6954.44,3503.44 ; J16.2@6896.57,3721.56 J16.2@6954.44,3721.56 ; J14.3@6896.57,4003.44 J14.3@6954.44,4003.44 ; J14.2@6896.57,4221.56 J14.2@6954.44,4221.56 ; J18.3@6896.57,4503.44 J18.3@6954.44,4503.44 ; J18.2@6896.57,4721.56 J18.2@6954.44,4721.56 ; J20.3@6896.57,5003.44 J20.3@6954.44,5003.44 ; J20.2@6896.57,5221.56 J20.2@6954.44,5221.56 ; J19.3@6896.57,5503.44 J19.3@6954.44,5503.44 ; J19.2@6896.57,5721.56 J19.2@6954.44,5721.56 ; J17.3@6896.57,6003.44 J17.3@6954.44,6003.44 ; J17.2@6896.57,6221.56 J17.2@6954.44,6221.56 ; J21.3@6896.57,6503.44 J21.3@6954.44,6503.44 ; J21.2@6896.57,6721.56 J21.2@6954.44,6721.56 ; J23.3@6896.57,7003.44 J23.3@6954.44,7003.44 ; J23.2@6896.57,7221.56 J23.2@6954.44,7221.56 ; J24.3@6896.57,7503.44 J24.3@6954.44,7503.44 ; J24.2@6896.57,7721.56 J24.2@6954.44,7721.56 ; J22.3@6896.57,8003.44 J22.3@6954.44,8003.44 ; J22.2@6896.57,8221.56 J22.2@6954.44,8221.56
  L1-Top Layer (GTL) w25: v3(4423.76,2992.57) C78.2@4423.76,3032.57
  L1-Top Layer (GTL) w30: v8(5114.2,2095.3) C516.2@5114.2,2156.28 ; v8(5289.4,2082.4) C515.2@5289.4,2143.2 ; v7(5394.02,1336.34) C27.2@5448.12,1336.34 v3(5448.12,1284.22) ; v8@5477.88,821.78 C504.2@5543.6,821.78 ; v8@5673.9,1329.2 C514.2@5673.9,1389.48 ; C513.2@5740.8,1378.6 5740.8,1324.8 v8(5817,1324.8) ; v3(5953.08,718.49) C10.2@6005.2,718.49 ; v3(6005.2,770.61) C10.2@6005.2,718.49 ; v3(6057.32,718.49) C10.2@6005.2,718.49 ; v8(6150.2,996.3) C500.2@6228.51,995.9 ; C510.2@6188.03,1130 v8(6241.6,1130) ; C509.2@6188.03,1202.9 v8(6240.9,1202.9) ; C508.2@6188.03,1276.1 v8(6241.2,1276.1)
  L1-Top Layer (GTL) w35: R502.1@6579.5,1680.8 v12(6623.9,1680.8)
  L1-Top Layer (GTL) w40: J500.5@5857.7,101.2 v8(5917.9,161.4)
  L3-Mid-Layer 2 (G1) w20: v1(3687.09,6066.46) 3697.6,6076.97 v1(3697.6,6098.64) ; 5097.28,3518.08 v1(5128.91,3518.08)
  L3-Mid-Layer 2 (G1) w30: 780.5,8723.67 ccw(c747.5,8723.67) 780.5,8723.67 ; v6@1280.5,8723.67 ccw(c1247.5,8723.67) v6@1280.5,8723.67 ; 1780.5,8723.67 ccw(c1747.5,8723.67) 1780.5,8723.67 ; v6@2280.5,8723.67 ccw(c2247.5,8723.67) v6@2280.5,8723.67 ; 2861.3,5677.02 ccw(c2884.64,5653.69) 2907.97,5630.35 2939.08,5661.47 ccw(c2915.75,5684.8) 2892.42,5708.13 2861.3,5677.02 ; 2977.46,5731.87 ccw(c3000.79,5708.54) 3024.12,5685.21 3055.24,5716.32 ccw(c3031.9,5739.65) 3008.57,5762.99 2977.46,5731.87 ; 3869.84,5464.22 ccw(c3902.84,5464.22) 3935.84,5464.22 3935.84,5508.22 ccw(c3902.84,5508.22) 3869.84,5508.22 3869.84,5464.22 ; 3965.89,5309.45 ccw(c3998.89,5309.45) 4031.89,5309.45 4031.89,5353.45 ccw(c3998.89,5353.45) 3965.89,5353.45 3965.89,5309.45 ; 6593.67,4612.5 ccw(c6560.67,4612.5) 6593.67,4612.5 ; 6593.67,5112.5 ccw(c6560.67,5112.5) 6593.67,5112.5 ; 6593.67,5612.5 ccw(c6560.67,5612.5) 6593.67,5612.5 ; 6593.67,6112.5 ccw(c6560.67,6112.5) 6593.67,6112.5
  L4-Mid-Layer 3 (G2) w30: 780.5,8723.67 ccw(c747.5,8723.67) 780.5,8723.67 ; v6@1280.5,8723.67 ccw(c1247.5,8723.67) v6@1280.5,8723.67 ; 1780.5,8723.67 ccw(c1747.5,8723.67) 1780.5,8723.67 ; v6@2280.5,8723.67 ccw(c2247.5,8723.67) v6@2280.5,8723.67 ; 2861.3,5677.02 ccw(c2884.64,5653.69) 2907.97,5630.35 2939.08,5661.46 ccw(c2915.75,5684.8) 2892.42,5708.13 2861.3,5677.02 ; 2977.45,5731.87 ccw(c3000.79,5708.54) 3024.12,5685.2 3055.24,5716.32 ccw(c3031.9,5739.65) 3008.57,5762.99 2977.45,5731.87 ; 3869.84,5464.22 ccw(c3902.84,5464.22) 3935.84,5464.22 3935.84,5508.22 ccw(c3902.84,5508.22) 3869.84,5508.22 3869.84,5464.22 ; 3965.89,5309.45 ccw(c3998.89,5309.45) 4031.89,5309.45 4031.89,5353.45 ccw(c3998.89,5353.45) 3965.89,5353.45 3965.89,5309.45 ; 6593.67,4612.5 ccw(c6560.67,4612.5) 6593.67,4612.5 ; 6593.67,5112.5 ccw(c6560.67,5112.5) 6593.67,5112.5 ; 6593.67,5612.5 ccw(c6560.67,5612.5) 6593.67,5612.5 ; 6593.67,6112.5 ccw(c6560.67,6112.5) 6593.67,6112.5
  L5-Mid-Layer 4 (G3) w30: 780.5,8723.67 ccw(c747.5,8723.67) 780.5,8723.67 ; v6@1280.5,8723.67 ccw(c1247.5,8723.67) v6@1280.5,8723.67 ; 1780.5,8723.67 ccw(c1747.5,8723.67) 1780.5,8723.67 ; v6@2280.5,8723.67 ccw(c2247.5,8723.67) v6@2280.5,8723.67 ; 2861.3,5677.02 ccw(c2884.64,5653.69) 2907.97,5630.35 2939.08,5661.47 ccw(c2915.75,5684.8) 2892.42,5708.13 2861.3,5677.02 ; 2977.46,5731.87 ccw(c3000.79,5708.54) 3024.12,5685.21 3055.24,5716.32 ccw(c3031.9,5739.65) 3008.57,5762.99 2977.46,5731.87 ; 3869.84,5464.22 ccw(c3902.84,5464.22) 3935.84,5464.22 3935.84,5508.22 ccw(c3902.84,5508.22) 3869.84,5508.22 3869.84,5464.22 ; 3965.89,5309.45 ccw(c3998.89,5309.45) 4031.89,5309.45 4031.89,5353.45 ccw(c3998.89,5353.45) 3965.89,5353.45 3965.89,5309.45 ; 6593.67,4612.5 ccw(c6560.67,4612.5) 6593.67,4612.5 ; 6593.67,5112.5 ccw(c6560.67,5112.5) 6593.67,5112.5 ; 6593.67,5612.5 ccw(c6560.67,5612.5) 6593.67,5612.5 ; 6593.67,6112.5 ccw(c6560.67,6112.5) 6593.67,6112.5
  L7-Mid-Layer 6 (G5) w30: 780.5,8723.67 ccw(c747.5,8723.67) 780.5,8723.67 ; v6@1280.5,8723.67 ccw(c1247.5,8723.67) v6@1280.5,8723.67 ; 1780.5,8723.67 ccw(c1747.5,8723.67) 1780.5,8723.67 ; v6@2280.5,8723.67 ccw(c2247.5,8723.67) v6@2280.5,8723.67 ; 2861.3,5677.02 ccw(c2884.64,5653.69) 2907.97,5630.35 2939.08,5661.47 ccw(c2915.75,5684.8) 2892.42,5708.13 2861.3,5677.02 ; 2977.46,5731.87 ccw(c3000.79,5708.54) 3024.12,5685.21 3055.24,5716.32 ccw(c3031.9,5739.65) 3008.57,5762.99 2977.46,5731.87 ; 3869.84,5464.22 ccw(c3902.84,5464.22) 3935.84,5464.22 3935.84,5508.22 ccw(c3902.84,5508.22) 3869.84,5508.22 3869.84,5464.22 ; 3965.89,5309.45 ccw(c3998.89,5309.45) 4031.89,5309.45 4031.89,5353.45 ccw(c3998.89,5353.45) 3965.89,5353.45 3965.89,5309.45 ; 6593.67,4612.5 ccw(c6560.67,4612.5) 6593.67,4612.5 ; 6593.67,5112.5 ccw(c6560.67,5112.5) 6593.67,5112.5 ; 6593.67,5612.5 ccw(c6560.67,5612.5) 6593.67,5612.5 ; 6593.67,6112.5 ccw(c6560.67,6112.5) 6593.67,6112.5
  L8-Bottom Layer (GBL) w10: v9(1011,1549) 1029,1567 J42.27@1029,1702.96 ; J42.28@1029,1973.04 v9(1029,2117) ; C97.2@1554.5,1418 1556.2,1419.7 v9(1609.9,1419.7) ; J42.8@2029,1973.04 2029,2101 v9(2009,2121) 2104,2121 2129,2096 J42.6@2129,1973.04 ; J42.4@2229,1973.04 2229,2089.63 2250.37,2111 2306,2111 v9(2339,2144) ; v1(3747.89,5352.18) v1@3748.01,5352.06 ; U9.7@5000.26,2784.28 5000.26,2727.24 R9.1@5058.5,2669 v3@5111.99,2669 ; U9.6@5149.87,2784.28 5149.87,2735.64 C156.2@5286,2599.5 v3@5339.5,2599.5 ; C24.2@5280,2839.5 v3(5280,2889) ; C7.2@5987.2,2263.9 v4@6043.36,2263.9 ; C7.2@5999.36,2253.9 C7.2@5999.54,2253.72 ; U10.7@6020.16,1960.6 6020.16,1931.44 6122.16,1931.44 6139.54,1914.06 v4(6139.54,1830.72) R2.1@6087.7,1830.4 ; U10.6@6020.16,2110.2 6020.16,2137.36 6066.16,2137.36 6066.16,2040.44 6103.74,2040.44 C154.2@6105.2,2041.9 ; R2.1@6071.2,1827.9 R2.1@6073.7,1830.4 ; C154.2@6105.46,2038.72 v4(6162.54,2038.72) ; v17(6276.4,1480.4) 6296.8,1500.8 6313.9,1500.8 6322.1,1509 v6(6322.1,1520.3) ; U11.7@6317.4,1882.19 6366.18,1833.4 6432.2,1833.4 6437.7,1827.9 R5.1@6437.7,1730.4 6468.54,1730.4 6476.64,1722.3 v17(6480.7,1722.3) ; v6(6322.1,1542.3) v6(6322.1,1565.3) ; U11.6@6467,1882.19 6501.2,1882.4 v4(6500.54,1784.72) 6570.2,1784.4 6580.2,1784.4 ; C155.2@6580.2,1830.9 6580.2,1784.4 ; C13.2@6634.2,1831.9 6634.2,1784.4 6580.2,1784.4
  L8-Bottom Layer (GBL) w11: C77.2@3043.3,6034.29 v1(3089.17,5988.43) ; C76.1@3081.55,5925.14 v1(3114.99,5891.7) ; v3(4047.22,5102.07) C73.1@4081.26,5068.02 ; v3@4152.02,5082.02 C74.2@4184.62,5049.42
  L8-Bottom Layer (GBL) w15: v1@3687.09,6066.17 v1(3687.09,6066.46) ; v1@3783.31,5968.52 v1(3783.31,5968.81)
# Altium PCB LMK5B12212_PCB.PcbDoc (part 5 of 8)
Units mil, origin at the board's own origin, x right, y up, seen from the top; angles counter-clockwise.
Board outline 7000 x 9161 mil, 8 copper layers (L1-Top Layer (GTL), L2-GND Plane (GP1), L3-Mid-Layer 2 (G1), L4-Mid-Layer 3 (G2), L5-Mid-Layer 4 (G3), L6-Mid-Layer 5 (G4), L7-Mid-Layer 6 (G5), L8-Bottom Layer (GBL)), stack 61.2 mil thick; 469 components, 264 nets, 1268 pads, 1812 vias.

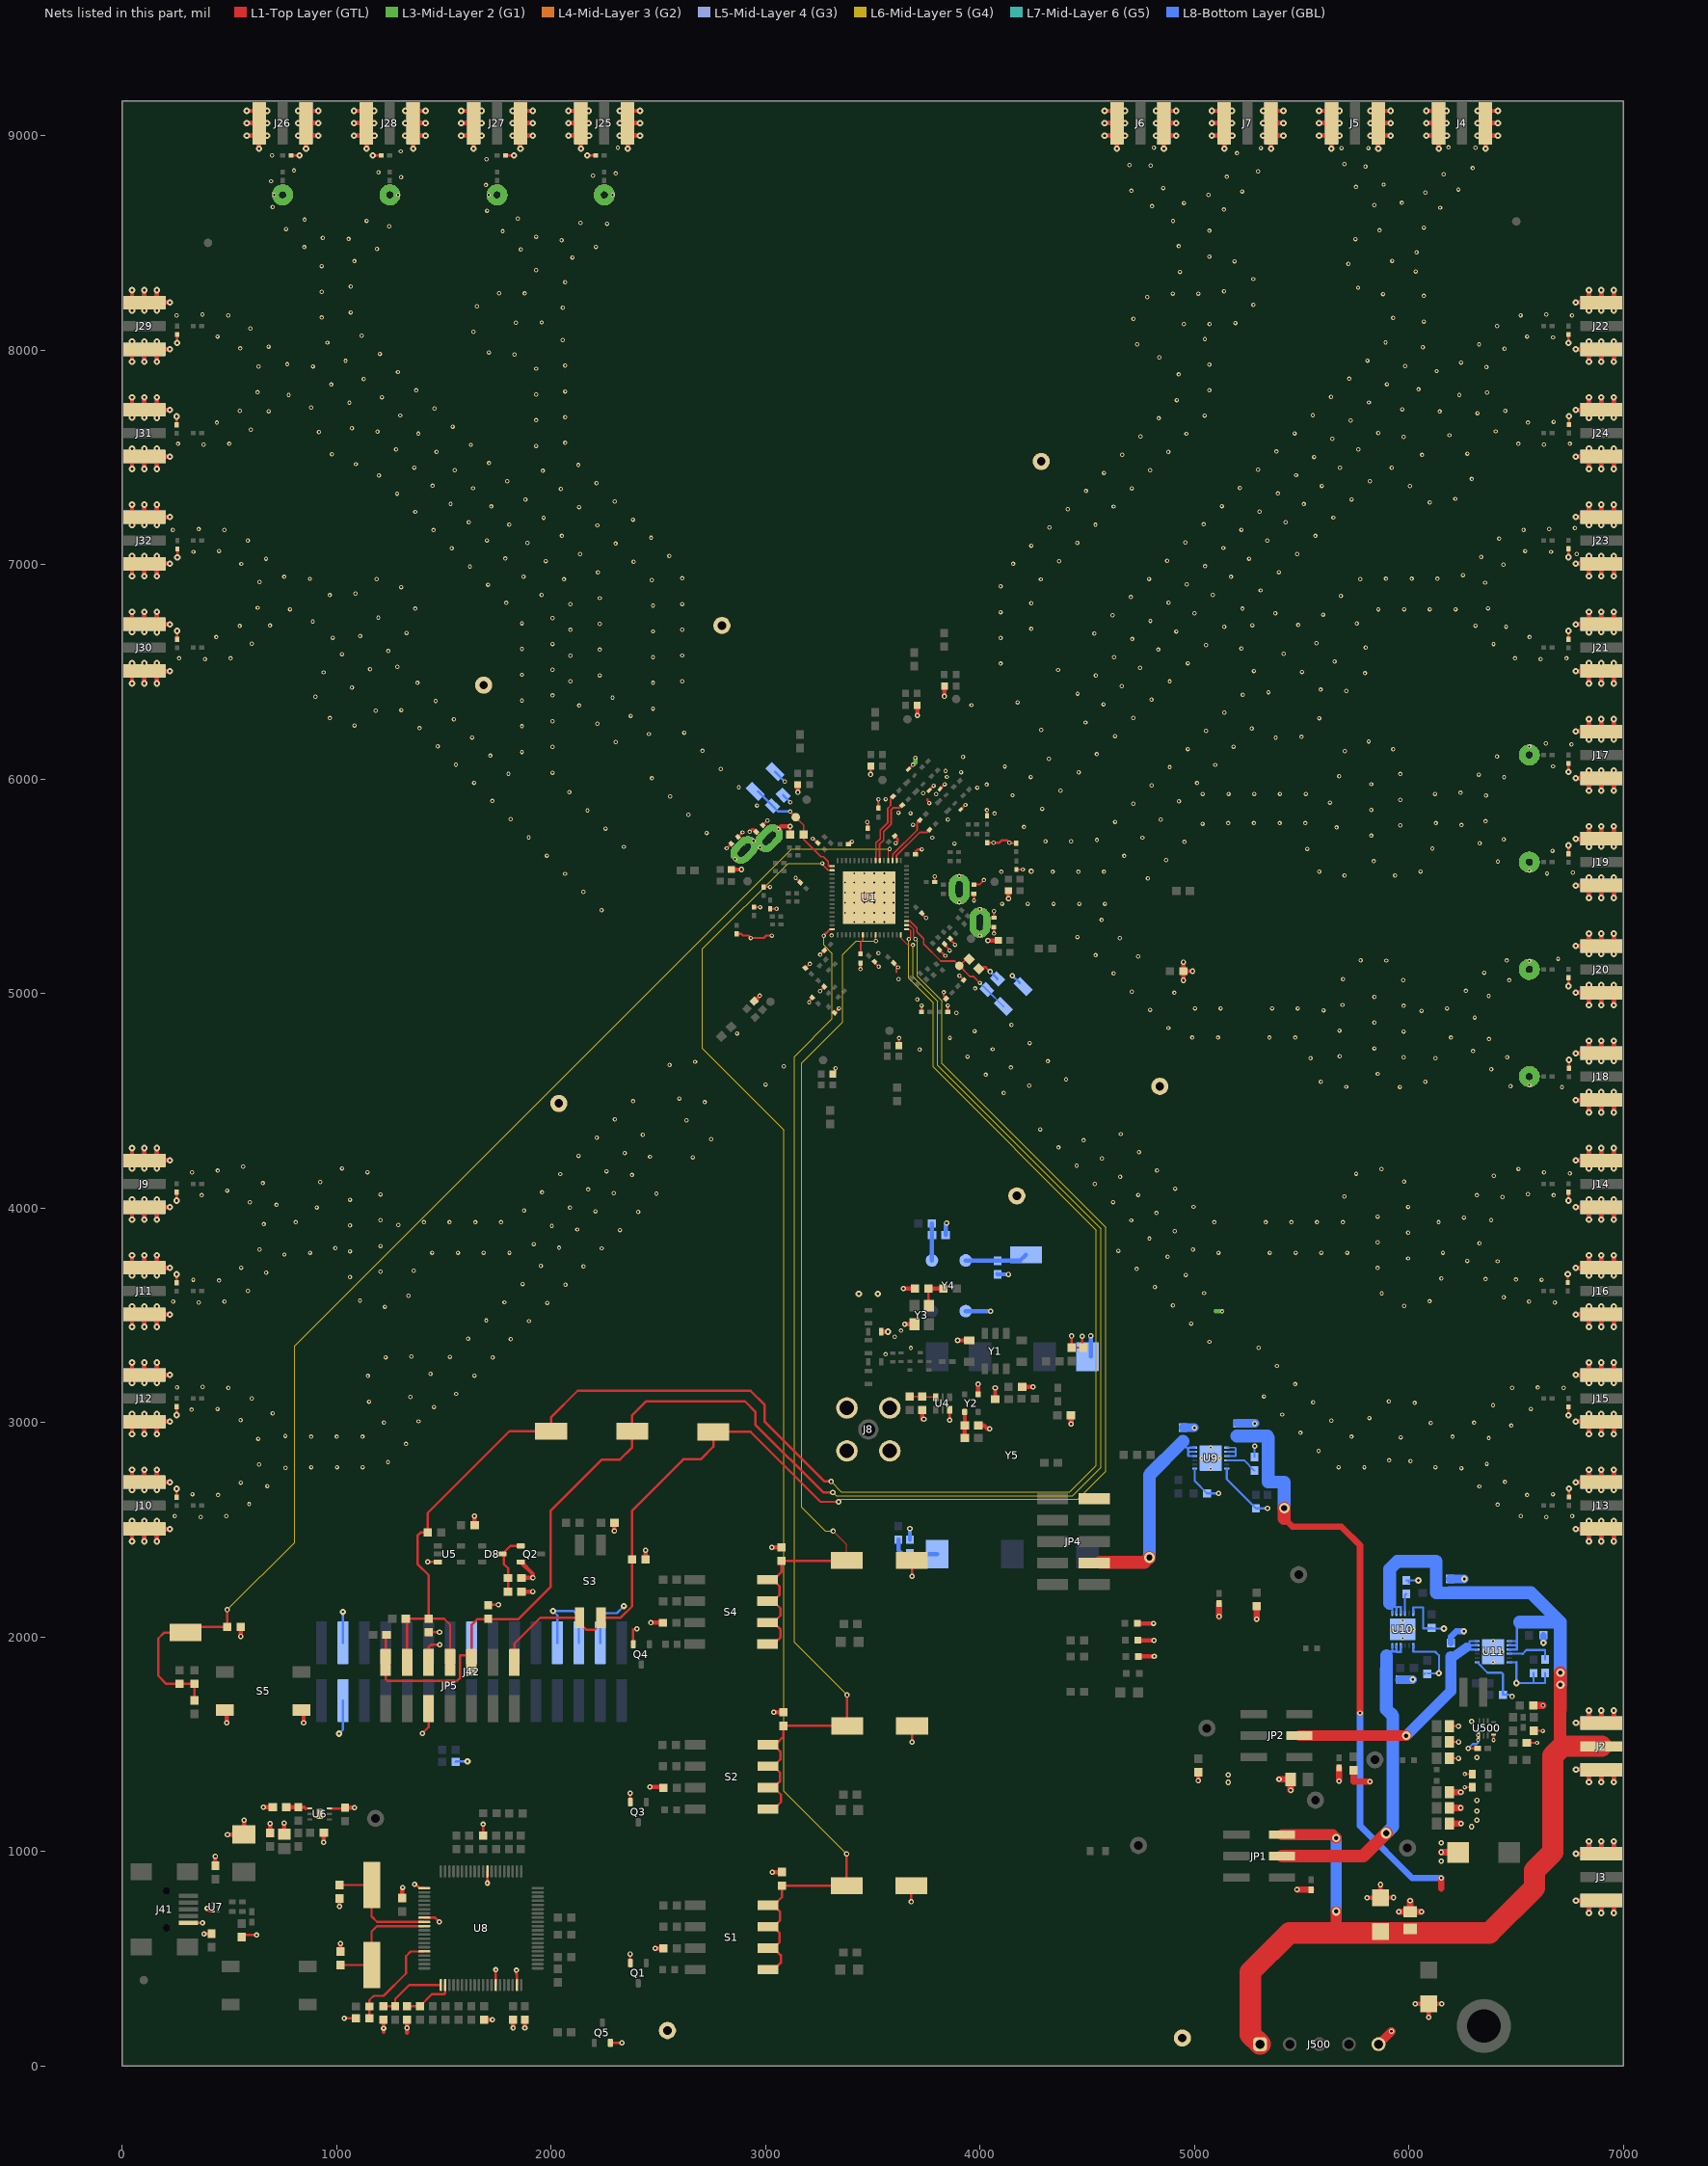
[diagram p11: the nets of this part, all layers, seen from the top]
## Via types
v1: diameter 20, hole 10, L1-Top Layer (GTL) to L8-Bottom Layer (GBL), tented top, 987 vias
v2: diameter 30, hole 12, L1-Top Layer (GTL) to L8-Bottom Layer (GBL), 407 vias
v3: diameter 25, hole 12, L1-Top Layer (GTL) to L8-Bottom Layer (GBL), tented top, 163 vias
v4: diameter 30, hole 12, L1-Top Layer (GTL) to L8-Bottom Layer (GBL), tented top, 52 vias
v5: diameter 19.68, hole 7.87, L1-Top Layer (GTL) to L8-Bottom Layer (GBL), 47 vias
v6: diameter 20, hole 10, L1-Top Layer (GTL) to L8-Bottom Layer (GBL), 39 vias
v7: diameter 25, hole 10, L1-Top Layer (GTL) to L8-Bottom Layer (GBL), tented top, 35 vias
v8: diameter 25, hole 12, L1-Top Layer (GTL) to L8-Bottom Layer (GBL), 23 vias
v9: diameter 30, hole 10, L1-Top Layer (GTL) to L8-Bottom Layer (GBL), 10 vias
v10: diameter 40, hole 20, L1-Top Layer (GTL) to L8-Bottom Layer (GBL), 10 vias
v11: diameter 18, hole 10, L1-Top Layer (GTL) to L8-Bottom Layer (GBL), tented top, 8 vias
v12: diameter 20, hole 10, L1-Top Layer (GTL) to L8-Bottom Layer (GBL), tented both sides, 6 vias
v13: diameter 39.37, hole 19.68, L1-Top Layer (GTL) to L8-Bottom Layer (GBL), tented top, 6 vias
v14: diameter 50, hole 28, L1-Top Layer (GTL) to L8-Bottom Layer (GBL), 4 vias
v15: diameter 23, hole 10, L1-Top Layer (GTL) to L8-Bottom Layer (GBL), tented top, 4 vias
v16: diameter 25, hole 10, L1-Top Layer (GTL) to L8-Bottom Layer (GBL), 4 vias
v17: diameter 25, hole 12, L1-Top Layer (GTL) to L8-Bottom Layer (GBL), tented both sides, 3 vias
v18: diameter 20/0/0/0/0/0/20 (per signal layer), hole 10, L1-Top Layer (GTL) to L8-Bottom Layer (GBL), tented top, 2 vias
v19: diameter 30, hole 12, L1-Top Layer (GTL) to L8-Bottom Layer (GBL), tented both sides, 1 vias
v20: diameter 25, hole 10, L1-Top Layer (GTL) to L8-Bottom Layer (GBL), tented both sides, 1 vias

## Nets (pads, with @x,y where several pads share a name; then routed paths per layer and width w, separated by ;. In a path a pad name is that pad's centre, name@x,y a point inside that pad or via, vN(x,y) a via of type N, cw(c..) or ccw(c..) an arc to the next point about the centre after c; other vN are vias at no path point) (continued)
GND: (continued)
  L8-Bottom Layer (GBL) w20: v2(45.56,2445.57) 45.56,2503.44 J10.4@103.43,2503.44 ; v2(45.56,2779.43) 45.56,2721.56 J10.5@103.43,2721.56 ; v2(45.56,2945.57) 45.56,3003.44 J12.4@103.43,3003.44 ; v2(45.56,3279.43) 45.56,3221.56 J12.5@103.43,3221.56 ; v2(45.56,3445.57) 45.56,3503.44 J11.4@103.43,3503.44 ; v2(45.56,3779.43) 45.56,3721.56 J11.5@103.43,3721.56 ; v2(45.56,3945.57) 45.56,4003.44 J9.4@103.43,4003.44 ; v2(45.56,4279.43) 45.56,4221.56 J9.5@103.43,4221.56 ; v2(45.56,6445.57) 45.56,6503.44 J30.4@103.43,6503.44 ; v2(45.56,6779.43) 45.56,6721.56 J30.5@103.43,6721.56 ; v2(45.56,6945.57) 45.56,7003.44 J32.4@103.43,7003.44 ; v2(45.56,7279.43) 45.56,7221.56 J32.5@103.43,7221.56 ; v2(45.56,7445.57) 45.56,7503.44 J31.4@103.43,7503.44 ; v2(45.56,7779.43) 45.56,7721.56 J31.5@103.43,7721.56 ; v2(45.56,7945.57) 45.56,8003.44 J29.4@103.43,8003.44 ; v2(45.56,8279.43) 45.56,8221.56 J29.5@103.43,8221.56 ; v2(103.43,2445.57) J10.4@103.43,2503.44 ; v2(103.43,2779.43) J10.5@103.43,2721.56 ; v2(103.43,2945.57) J12.4@103.43,3003.44 ; v2(103.43,3279.43) J12.5@103.43,3221.56 ; v2(103.43,3445.57) J11.4@103.43,3503.44 ; v2(103.43,3779.43) J11.5@103.43,3721.56 ; v2(103.43,3945.57) J9.4@103.43,4003.44 ; v2(103.43,4279.43) J9.5@103.43,4221.56 ; v2(103.43,6445.57) J30.4@103.43,6503.44 ; v2(103.43,6779.43) J30.5@103.43,6721.56 ; v2(103.43,6945.57) J32.4@103.43,7003.44 ; v2(103.43,7279.43) J32.5@103.43,7221.56 ; v2(103.43,7445.57) J31.4@103.43,7503.44 ; v2(103.43,7779.43) J31.5@103.43,7721.56 ; v2(103.43,7945.57) J29.4@103.43,8003.44 ; v2(103.43,8279.43) J29.5@103.43,8221.56 ; v2(161.3,2445.57) 161.3,2503.44 J10.4@103.43,2503.44 ; v2(161.3,2779.43) 161.3,2721.56 J10.5@103.43,2721.56 ; v2(161.3,2945.57) 161.3,3003.44 J12.4@103.43,3003.44 ; v2(161.3,3279.43) 161.3,3221.56 J12.5@103.43,3221.56 ; v2(161.3,3445.57) 161.3,3503.44 J11.4@103.43,3503.44 ; v2(161.3,3779.43) 161.3,3721.56 J11.5@103.43,3721.56 ; v2(161.3,3945.57) 161.3,4003.44 J9.4@103.43,4003.44 ; v2(161.3,4279.43) 161.3,4221.56 J9.5@103.43,4221.56 ; v2(161.3,6445.57) 161.3,6503.44 J30.4@103.43,6503.44 ; v2(161.3,6779.43) 161.3,6721.56 J30.5@103.43,6721.56 ; v2(161.3,6945.57) 161.3,7003.44 J32.4@103.43,7003.44 ; v2(161.3,7279.43) 161.3,7221.56 J32.5@103.43,7221.56 ; v2(161.3,7445.57) 161.3,7503.44 J31.4@103.43,7503.44 ; v2(161.3,7779.43) 161.3,7721.56 J31.5@103.43,7721.56 ; v2(161.3,7945.57) 161.3,8003.44 J29.4@103.43,8003.44 ; v2(161.3,8279.43) 161.3,8221.56 J29.5@103.43,8221.56 ; J10.4@161.5,2503.44 v2(221.37,2503.44) v2@222.37,2503.44 ; J10.5@161.5,2721.56 v2(221.37,2721.56) v2@222.37,2721.56 ; J12.4@161.5,3003.44 v2(221.37,3003.44) v2@222.37,3003.44 ; J12.5@161.5,3221.56 v2(221.37,3221.56) v2@222.37,3221.56 ; J11.4@161.5,3503.44 v2(221.37,3503.44) v2@222.37,3503.44 ; J11.5@161.5,3721.56 v2(221.37,3721.56) v2@222.37,3721.56 ; J9.4@161.5,4003.44 v2(221.37,4003.44) v2@222.37,4003.44 ; J9.5@161.5,4221.56 v2(221.37,4221.56) v2@222.37,4221.56 ; J30.4@161.5,6503.44 v2(221.37,6503.44) v2@222.37,6503.44 ; J30.5@161.5,6721.56 v2(221.37,6721.56) v2@222.37,6721.56 ; J32.4@161.5,7003.44 v2(221.37,7003.44) v2@222.37,7003.44 ; J32.5@161.5,7221.56 v2(221.37,7221.56) v2@222.37,7221.56 ; J31.4@161.5,7503.44 v2(221.37,7503.44) v2@222.37,7503.44 ; J31.5@161.5,7721.56 v2(221.37,7721.56) v2@222.37,7721.56 ; J29.4@161.5,8003.44 v4(221.37,8003.44) v4@222.37,8003.44 ; J29.5@161.5,8221.56 v2(221.37,8221.56) v2@222.37,8221.56 ; v2(580.57,8999.7) 638.44,8999.7 J26.4@638.44,9057.57 ; v2(580.57,9057.57) J26.4@638.44,9057.57 ; v2(580.57,9115.44) 638.44,9115.44 J26.4@638.44,9057.57 ; v2@638.44,8938.63 v2(638.44,8939.63) J26.4@638.44,8999.5 ; v2@856.56,8938.63 v2(856.56,8939.63) J26.5@856.56,8999.5 ; v2(914.43,8999.7) 856.56,8999.7 J26.5@856.56,9057.57 ; v2(914.43,9057.57) J26.5@856.56,9057.57 ; v2(914.43,9115.44) 856.56,9115.44 J26.5@856.56,9057.57 ; v2(1080.57,8999.7) 1138.44,8999.7 J28.4@1138.44,9057.57 ; v2(1080.57,9057.57) J28.4@1138.44,9057.57 ; v2(1080.57,9115.44) 1138.44,9115.44 J28.4@1138.44,9057.57 ; v2@1138.44,8938.63 v2(1138.44,8939.63) J28.4@1138.44,8999.5 ; v2@1356.56,8938.63 v2(1356.56,8939.63) J28.5@1356.56,8999.5 ; v2(1414.43,8999.7) 1356.56,8999.7 J28.5@1356.56,9057.57 ; v2(1414.43,9057.57) J28.5@1356.56,9057.57 ; v2(1414.43,9115.44) 1356.56,9115.44 J28.5@1356.56,9057.57 ; v2(1580.57,8999.7) 1638.44,8999.7 J27.4@1638.44,9057.57 ; v2(1580.57,9057.57) J27.4@1638.44,9057.57 ; v2(1580.57,9115.44) 1638.44,9115.44 J27.4@1638.44,9057.57 ; v2@1638.44,8938.63 v2(1638.44,8939.63) J27.4@1638.44,8999.5 ; v2@1856.56,8938.63 v2(1856.56,8939.63) J27.5@1856.56,8999.5 ; v2(1914.43,8999.7) 1856.56,8999.7 J27.5@1856.56,9057.57 ; v2(1914.43,9057.57) J27.5@1856.56,9057.57 ; v2(1914.43,9115.44) 1856.56,9115.44 J27.5@1856.56,9057.57 ; v2(2080.57,8999.7) 2138.44,8999.7 J25.4@2138.44,9057.57 ; v2(2080.57,9057.57) J25.4@2138.44,9057.57 ; v2(2080.57,9115.44) 2138.44,9115.44 J25.4@2138.44,9057.57 ; v2@2138.44,8938.63 v2(2138.44,8939.63) J25.4@2138.44,8999.5 ; v2@2356.56,8938.63 v2(2356.56,8939.63) J25.5@2356.56,8999.5 ; v2(2414.43,8999.7) 2356.56,8999.7 J25.5@2356.56,9057.57 ; v2(2414.43,9057.57) J25.5@2356.56,9057.57 ; v2(2414.43,9115.44) 2356.56,9115.44 J25.5@2356.56,9057.57 ; C85.2@3672.72,2454 v3(3672.72,2505) ; C84.2@3839.05,3873.81 3839.05,3924.19 3843.7,3928.85 v3(3843.7,3930.2) ; Y4.2@3932.95,3519.25 v3(4048.75,3519.25) ; C86.2@4081.38,3690.79 4081.58,3690.6 4132.3,3690.6 v3(4132.5,3690.4) ; Y5.7@4515.56,3306.88 v3(4515.56,3404.44) ; v2(4580.57,8999.7) 4638.44,8999.7 J6.4@4638.44,9057.57 ; v2(4580.57,9057.57) J6.4@4638.44,9057.57 ; v2(4580.57,9115.44) 4638.44,9115.44 J6.4@4638.44,9057.57 ; v2@4638.44,8938.63 v2(4638.44,8939.63) J6.4@4638.44,8999.5 ; v2@4856.56,8938.63 v2(4856.56,8939.63) J6.5@4856.56,8999.5 ; v2(4914.43,8999.7) 4856.56,8999.7 J6.5@4856.56,9057.57 ; v2(4914.43,9057.57) J6.5@4856.56,9057.57 ; v2(4914.43,9115.44) 4856.56,9115.44 J6.5@4856.56,9057.57 ; v2(5080.57,8999.7) 5138.44,8999.7 J7.4@5138.44,9057.57 ; v2(5080.57,9057.57) J7.4@5138.44,9057.57 ; v2(5080.57,9115.44) 5138.44,9115.44 J7.4@5138.44,9057.57 ; v2@5138.44,8938.63 v2(5138.44,8939.63) J7.4@5138.44,8999.5 ; v2@5356.56,8938.63 v2(5356.56,8939.63) J7.5@5356.56,8999.5 ; v2(5414.43,8999.7) 5356.56,8999.7 J7.5@5356.56,9057.57 ; v2(5414.43,9057.57) J7.5@5356.56,9057.57 ; v2(5414.43,9115.44) 5356.56,9115.44 J7.5@5356.56,9057.57 ; v2(5580.57,8999.7) 5638.44,8999.7 J5.4@5638.44,9057.57 ; v2(5580.57,9057.57) J5.4@5638.44,9057.57 ; v2(5580.57,9115.44) 5638.44,9115.44 J5.4@5638.44,9057.57 ; v2@5638.44,8938.63 v2(5638.44,8939.63) J5.4@5638.44,8999.5 ; v2@5856.56,8938.63 v2(5856.56,8939.63) J5.5@5856.56,8999.5 ; v2(5914.43,8999.7) 5856.56,8999.7 J5.5@5856.56,9057.57 ; v2(5914.43,9057.57) J5.5@5856.56,9057.57 ; v2(5914.43,9115.44) 5856.56,9115.44 J5.5@5856.56,9057.57 ; v2(6080.57,8999.7) 6138.44,8999.7 J4.4@6138.44,9057.57 ; v2(6080.57,9057.57) J4.4@6138.44,9057.57 ; v2(6080.57,9115.44) 6138.44,9115.44 J4.4@6138.44,9057.57 ; v2@6138.44,8938.63 v2(6138.44,8939.63) J4.4@6138.44,8999.5 ; v2@6356.56,8938.63 v2(6356.56,8939.63) J4.5@6356.56,8999.5 ; v2(6414.43,8999.7) 6356.56,8999.7 J4.5@6356.56,9057.57 ; v2(6414.43,9057.57) J4.5@6356.56,9057.57 ; v2(6414.43,9115.44) 6356.56,9115.44 J4.5@6356.56,9057.57 ; v2@6775.63,1380.94 v2(6778.63,1380.94) J2.5@6836.5,1380.94 ; v2@6776.23,770.94 v2(6778.63,770.94) J3.5@6837.1,770.94 ; v2@6776.23,989.06 v2(6778.63,989.06) J3.4@6837.1,989.06 ; v2(6777.83,2503.44) J13.5@6838.7,2503.44 ; v2(6777.83,2721.56) J13.4@6838.7,2721.56 ; v2(6777.83,3003.44) J15.5@6838.7,3003.44 ; v2(6777.83,3221.56) J15.4@6838.7,3221.56 ; v2(6777.83,3503.44) J16.5@6838.7,3503.44 ; v2(6777.83,3721.56) J16.4@6838.7,3721.56 ; v2(6777.83,4003.44) J14.5@6838.7,4003.44 ; v2(6777.83,4221.56) J14.4@6838.7,4221.56 ; v2(6777.83,4503.44) J18.5@6838.7,4503.44 ; v2(6777.83,4721.56) J18.4@6838.7,4721.56 ; v2(6777.83,5003.44) J20.5@6838.7,5003.44 ; v2(6777.83,5221.56) J20.4@6838.7,5221.56 ; v2(6777.83,5503.44) J19.5@6838.7,5503.44 ; v2(6777.83,5721.56) J19.4@6838.7,5721.56 ; v2(6777.83,6003.44) J17.5@6838.7,6003.44 ; v2(6777.83,6221.56) J17.4@6838.7,6221.56 ; v2(6777.83,6503.44) J21.5@6838.7,6503.44 ; v2(6777.83,6721.56) J21.4@6838.7,6721.56 ; v2(6777.83,7003.44) J23.5@6838.7,7003.44 ; v2(6777.83,7221.56) J23.4@6838.7,7221.56 ; v2(6777.83,7503.44) J24.5@6838.7,7503.44 ; v2(6777.83,7721.56) J24.4@6838.7,7721.56 ; v2(6777.83,8003.44) J22.5@6838.7,8003.44 ; v2(6777.83,8221.56) J22.4@6838.7,8221.56 ; v2(6778.63,1599.06) J2.4@6836.5,1599.06 ; v2(6838.7,1323.07) 6838.7,1380.94 J2.5@6896.57,1380.94 ; v2(6838.7,1656.93) 6838.7,1599.06 J2.4@6896.57,1599.06 ; v2(6838.7,2445.57) J13.5@6838.7,2503.44 ; v2(6838.7,2779.43) J13.4@6838.7,2721.56 ; v2(6838.7,2945.57) J15.5@6838.7,3003.44 ; v2(6838.7,3279.43) J15.4@6838.7,3221.56 ; v2(6838.7,3445.57) J16.5@6838.7,3503.44 ; v2(6838.7,3779.43) J16.4@6838.7,3721.56 ; v2(6838.7,3945.57) J14.5@6838.7,4003.44 ; v2(6838.7,4279.43) J14.4@6838.7,4221.56 ; v2(6838.7,4445.57) J18.5@6838.7,4503.44 ; v2(6838.7,4779.43) J18.4@6838.7,4721.56 ; v2(6838.7,4945.57) J20.5@6838.7,5003.44 ; v2(6838.7,5279.43) J20.4@6838.7,5221.56 ; v2(6838.7,5445.57) J19.5@6838.7,5503.44 ; v2(6838.7,5779.43) J19.4@6838.7,5721.56 ; v2(6838.7,5945.57) J17.5@6838.7,6003.44 ; v2(6838.7,6279.43) J17.4@6838.7,6221.56 ; v2(6838.7,6445.57) J21.5@6838.7,6503.44 ; v2(6838.7,6779.43) J21.4@6838.7,6721.56 ; v2(6838.7,6945.57) J23.5@6838.7,7003.44 ; v2(6838.7,7279.43) J23.4@6838.7,7221.56 ; v2(6838.7,7445.57) J24.5@6838.7,7503.44 ; v2(6838.7,7779.43) J24.4@6838.7,7721.56 ; v2(6838.7,7945.57) J22.5@6838.7,8003.44 ; v2(6838.7,8279.43) J22.4@6838.7,8221.56 ; v2@6839.3,713.07 6839.3,770.94 J3.5@6896.57,770.94 J3.5@6897.17,770.94 ; v2@6839.3,1046.93 6839.3,989.06 J3.4@6896.57,989.06 J3.4@6897.17,989.06 ; v2(6896.57,1323.07) J2.5@6896.57,1380.94 ; v2(6896.57,1656.93) J2.4@6896.57,1599.06 ; v2(6896.57,2445.57) J13.5@6896.57,2503.44 ; v2(6896.57,2779.43) J13.4@6896.57,2721.56 ; v2(6896.57,2945.57) J15.5@6896.57,3003.44 ; v2(6896.57,3279.43) J15.4@6896.57,3221.56 ; v2(6896.57,3445.57) J16.5@6896.57,3503.44 ; v2(6896.57,3779.43) J16.4@6896.57,3721.56 ; v2(6896.57,3945.57) J14.5@6896.57,4003.44 ; v2(6896.57,4279.43) J14.4@6896.57,4221.56 ; v2(6896.57,4445.57) J18.5@6896.57,4503.44 ; v2(6896.57,4779.43) J18.4@6896.57,4721.56 ; v2(6896.57,4945.57) J20.5@6896.57,5003.44 ; v2(6896.57,5279.43) J20.4@6896.57,5221.56 ; v2(6896.57,5445.57) J19.5@6896.57,5503.44 ; v2(6896.57,5779.43) J19.4@6896.57,5721.56 ; v2(6896.57,5945.57) J17.5@6896.57,6003.44 ; v2(6896.57,6279.43) J17.4@6896.57,6221.56 ; v2(6896.57,6445.57) J21.5@6896.57,6503.44 ; v2(6896.57,6779.43) J21.4@6896.57,6721.56 ; v2(6896.57,6945.57) J23.5@6896.57,7003.44 ; v2(6896.57,7279.43) J23.4@6896.57,7221.56 ; v2(6896.57,7445.57) J24.5@6896.57,7503.44 ; v2(6896.57,7779.43) J24.4@6896.57,7721.56 ; v2(6896.57,7945.57) J22.5@6896.57,8003.44 ; v2(6896.57,8279.43) J22.4@6896.57,8221.56 ; v2@6897.17,713.07 J3.5@6897.17,770.94 ; v2@6897.17,1046.93 J3.4@6897.17,989.06 ; v2(6954.44,1323.07) 6954.44,1380.94 J2.5@6896.57,1380.94 ; v2(6954.44,1656.93) 6954.44,1599.06 J2.4@6896.57,1599.06 ; v2(6954.44,2445.57) 6954.44,2503.44 J13.5@6896.57,2503.44 ; v2(6954.44,2779.43) 6954.44,2721.56 J13.4@6896.57,2721.56 ; v2(6954.44,2945.57) 6954.44,3003.44 J15.5@6896.57,3003.44 ; v2(6954.44,3279.43) 6954.44,3221.56 J15.4@6896.57,3221.56 ; v2(6954.44,3445.57) 6954.44,3503.44 J16.5@6896.57,3503.44 ; v2(6954.44,3779.43) 6954.44,3721.56 J16.4@6896.57,3721.56 ; v2(6954.44,3945.57) 6954.44,4003.44 J14.5@6896.57,4003.44 ; v2(6954.44,4279.43) 6954.44,4221.56 J14.4@6896.57,4221.56 ; v2(6954.44,4445.57) 6954.44,4503.44 J18.5@6896.57,4503.44 ; v2(6954.44,4779.43) 6954.44,4721.56 J18.4@6896.57,4721.56 ; v2(6954.44,4945.57) 6954.44,5003.44 J20.5@6896.57,5003.44 ; v2(6954.44,5279.43) 6954.44,5221.56 J20.4@6896.57,5221.56 ; v2(6954.44,5445.57) 6954.44,5503.44 J19.5@6896.57,5503.44 ; v2(6954.44,5779.43) 6954.44,5721.56 J19.4@6896.57,5721.56 ; v2(6954.44,5945.57) 6954.44,6003.44 J17.5@6896.57,6003.44 ; v2(6954.44,6279.43) 6954.44,6221.56 J17.4@6896.57,6221.56 ; v2(6954.44,6445.57) 6954.44,6503.44 J21.5@6896.57,6503.44 ; v2(6954.44,6779.43) 6954.44,6721.56 J21.4@6896.57,6721.56 ; v2(6954.44,6945.57) 6954.44,7003.44 J23.5@6896.57,7003.44 ; v2(6954.44,7279.43) 6954.44,7221.56 J23.4@6896.57,7221.56 ; v2(6954.44,7445.57) 6954.44,7503.44 J24.5@6896.57,7503.44 ; v2(6954.44,7779.43) 6954.44,7721.56 J24.4@6896.57,7721.56 ; v2(6954.44,7945.57) 6954.44,8003.44 J22.5@6896.57,8003.44 ; v2(6954.44,8279.43) 6954.44,8221.56 J22.4@6896.57,8221.56 ; v2@6955.04,713.07 6955.04,770.94 J3.5@6897.17,770.94 ; v2@6955.04,1046.93 6955.04,989.06 J3.4@6897.17,989.06 ; J13.5@6838.7,2503.44 J13.5@6896.57,2503.44 ; J13.4@6838.7,2721.56 J13.4@6896.57,2721.56 ; J15.5@6838.7,3003.44 J15.5@6896.57,3003.44 ; J15.4@6838.7,3221.56 J15.4@6896.57,3221.56 ; J16.5@6838.7,3503.44 J16.5@6896.57,3503.44 ; J16.4@6838.7,3721.56 J16.4@6896.57,3721.56 ; J14.5@6838.7,4003.44 J14.5@6896.57,4003.44 ; J14.4@6838.7,4221.56 J14.4@6896.57,4221.56 ; J18.5@6838.7,4503.44 J18.5@6896.57,4503.44 ; J18.4@6838.7,4721.56 J18.4@6896.57,4721.56 ; J20.5@6838.7,5003.44 J20.5@6896.57,5003.44 ; J20.4@6838.7,5221.56 J20.4@6896.57,5221.56 ; J19.5@6838.7,5503.44 J19.5@6896.57,5503.44 ; J19.4@6838.7,5721.56 J19.4@6896.57,5721.56 ; J17.5@6838.7,6003.44 J17.5@6896.57,6003.44 ; J17.4@6838.7,6221.56 J17.4@6896.57,6221.56 ; J21.5@6838.7,6503.44 J21.5@6896.57,6503.44 ; J21.4@6838.7,6721.56 J21.4@6896.57,6721.56 ; J23.5@6838.7,7003.44 J23.5@6896.57,7003.44 ; J23.4@6838.7,7221.56 J23.4@6896.57,7221.56 ; J24.5@6838.7,7503.44 J24.5@6896.57,7503.44 ; J24.4@6838.7,7721.56 J24.4@6896.57,7721.56 ; J22.5@6838.7,8003.44 J22.5@6896.57,8003.44 ; J22.4@6838.7,8221.56 J22.4@6896.57,8221.56
  L8-Bottom Layer (GBL) w30: C9.2@6195.2,1970.9 6195.2,2000.4 6221.2,2026.4 v4(6256.2,2026.4) ; v19(6627.2,1972.4) C8.2@6627.2,2008.9 ; 780.5,8723.67 ccw(c747.5,8723.67) 780.5,8723.67 ; v6@1280.5,8723.67 ccw(c1247.5,8723.67) v6@1280.5,8723.67 ; 1780.5,8723.67 ccw(c1747.5,8723.67) 1780.5,8723.67 ; v6@2280.5,8723.67 ccw(c2247.5,8723.67) v6@2280.5,8723.67 ; 2861.3,5677.02 ccw(c2884.64,5653.69) 2907.97,5630.35 2939.08,5661.47 ccw(c2915.75,5684.8) 2892.42,5708.13 2861.3,5677.02 ; 2977.46,5731.87 ccw(c3000.79,5708.54) 3024.12,5685.21 3055.24,5716.32 ccw(c3031.9,5739.65) 3008.57,5762.99 2977.46,5731.87 ; 3869.84,5464.22 ccw(c3902.84,5464.22) 3935.84,5464.22 3935.84,5508.22 ccw(c3902.84,5508.22) 3869.84,5508.22 3869.84,5464.22 ; 3965.89,5309.45 ccw(c3998.89,5309.45) 4031.89,5309.45 4031.89,5353.45 ccw(c3998.89,5353.45) 3965.89,5353.45 3965.89,5309.45 ; 6593.67,4612.5 ccw(c6560.67,4612.5) 6593.67,4612.5 ; 6593.67,5112.5 ccw(c6560.67,5112.5) 6593.67,5112.5 ; 6593.67,5612.5 ccw(c6560.67,5612.5) 6593.67,5612.5 ; 6593.67,6112.5 ccw(c6560.67,6112.5) 6593.67,6112.5
  L8-Bottom Layer (GBL) w40: C23.2@4946,2975.5 v3(4999.5,2975.5) ; C22.2@5200,2995.5 v3@5281,2995.48 ; C2.2@5956.7,1801.4 v4(6017.2,1801.4) ; C1.2@6191.2,2269.9 v4(6257.54,2270.72)
  other v1: 365.34,2559.29 6640.59,2559.48 245.4,2563.18 485.27,2563.17 6520.65,2563.17 6760.53,2563.18 6413.35,2616.9 591.59,2618.83 447.04,2661.82 6550.98,2661.82 327.1,2665.71 6670.92,2665.71 6328.49,2701.75 676.44,2703.68 552.44,2719.19 6447.38,2722.38 6243.64,2786.6 761.29,2788.53 881.26,2791.17 1001.26,2791.17 1121.26,2791.17 5791.67,2791.17 6123.73,2791.17 5671.67,2791.55 637.29,2804.04 6362.53,2807.23 1238.83,2815.24 6007.27,2820.11 5907.16,2823.75 5578.31,2866.94 1323.61,2900.17 634.24,2924 6371.64,2926.88 5961.18,2930.91 880.18,2933.82 1000.18,2933.82 1120.18,2933.82 5731.59,2933.82 6203,2933.82 760.24,2937.52 5493.46,2951.79 6476.58,2985.09 6101.49,2997.82 1220.77,2999.26 6303.95,2998.7 1381.57,3005.24 5638.02,3008.96 551.52,3010.94 5814.75,3020.33 5408.61,3036.64 701.23,3042 323.55,3059.29 443.49,3063.17 6567.7,3063.17 1453.67,3072.23 6391.88,3080.36 6026.02,3091.12 5553.17,3093.81 1151.01,3096.9 5906.22,3098 603.85,3112.13 1343.12,3118.91 5323.75,3121.5 1556.93,3133.37 6480.63,3161.13 494.62,3161.82 6720.61,3161.82 6600.62,3162.72 254.7,3163.87 374.69,3165.71 5468.32,3178.67 1145.01,3216.75 1641.8,3218.2 1437.11,3226.86 5383.46,3263.52 1726.68,3303.03 1227.81,3303.62 1527.48,3305.82 1347.76,3306.96 3559,3318 3677,3347 5298.61,3348.37 5069.19,3376.06 1811.55,3387.86 1612.35,3390.65 3602,3400 3631,3428 4984.34,3460.91 1896.42,3472.69 1697.23,3475.48 1225.16,3539.62 5977.46,3543.17 4899.49,3545.76 1981.3,3557.52 6679.88,3559.47 356.85,3559.55 1782.1,3560.31 236.9,3563.18 476.79,3563.17 6559.94,3563.17 6095.47,3564.93 1108.53,3567.87 6441.68,3583.56 1333.98,3590.2 5872.73,3601.75 5044.05,3602.93 585.89,3613.14 4814.64,3630.61 2066.17,3642.35 1866.98,3645.14 450.93,3661.82 331,3665.71 6498.42,3666.34 6618.41,3665.71 6356.83,3668.41 6150.82,3671.4 1061.6,3678.32 4959.2,3687.78 670.75,3697.99 1204.24,3703.04 1359.24,3707.51 4729.78,3715.47 5853.18,3720.15 554.93,3721.69 2151.05,3727.18 1951.85,3729.97 6413.56,3751.19 6271.98,3753.27 5995.82,3764.83 4874.35,3772.64 755.6,3782.84 875.31,3791.17 1445.27,3791.17 1565.27,3791.17 1685.27,3791.17 1805.27,3791.17 5111.11,3791.17 5351.11,3791.17 5471.11,3791.17 5591.11,3791.17 5711.11,3791.17 6158.12,3791.17 1061.6,3798.32 4644.93,3800.32 4992.07,3806.35 639.79,3806.54 2235.92,3812.02 993.35,3812.76 2036.73,3814.8 1204.24,3823.04 1918.15,3831.89 6328.71,3836.05 5853.18,3840.15 4789.5,3857.49 5995.82,3884.83 4907.25,3891.23 2320.8,3896.85 2121.6,3899.63 2003,3916.74 1061.6,3918.32 1286.75,3920.5 659.44,3924.92 808.26,3933.82 1406.01,3933.82 1526.01,3933.82 1646.01,3933.82 1766.01,3933.82 5091.25,3933.82 5331.25,3933.82 5451.25,3933.82 5571.25,3933.82 5691.25,3933.82 6137.87,3933.82 4704.64,3942.34 1204.24,3943.04 6382.88,3943.12 6255.87,3955.62 5853.18,3960.15 4822.43,3976.11 2405.67,3981.68 2206.48,3984.46 1872.89,3988.37 2087.86,4001.59 906.6,4002.6 4994.85,4005.28 5995.82,4004.83 719.43,4014.5 595.15,4026.24 4619.79,4027.2 1061.6,4038.32 6435.65,4050.9 5698.18,4053.62 370.62,4059.29 6316.05,4059.44 6674.78,4059.29 4737.6,4060.99 1203.94,4063.04 6554.89,4064.37 2490.55,4066.51 2291.35,4069.29 1957.75,4073.22 488.57,4081.39 2172.71,4086.45 4909.98,4090.12 4534.94,4112.05 655.14,4115.82 923.25,4121.44 5976.28,4123.23 4652.78,4145.87 6395.03,4149.79 2376.23,4154.13 2042.6,4158.07 5753.55,4160.08 6749.32,4161.82 325.29,4165.71 6629.38,4165.71 1143.78,4166.87 2257.56,4171.3 444.98,4174.33 4825.12,4174.96 5871.56,4181.82 6510.54,4182.32 1025.14,4184.83 563.47,4193.27 4450.08,4196.9 4567.95,4230.75 2660.3,4236.17 2461.1,4238.96 2127.45,4242.93 2342.41,4256.15 4740.25,4259.8 4365.23,4281.75 4483.13,4315.64 2745.17,4321 2212.3,4327.78 2427.27,4341.01 4655.38,4344.64 4280.38,4366.61 2630.85,4408.62 2297.16,4412.63 2715.72,4493.45 2382.01,4497.48 2596.97,4510.71 4110.67,4536.31 6713.18,4563.18 5706.79,4564.7 5957.88,4564.61 6473.26,4567.64 4228.65,4570.28 2999.8,4575.49 5589.14,4588.32 6075.42,4588.78 4400.78,4599.15 4025.82,4621.16 5854.39,4625.35 6383.06,4646.78 4143.83,4655.16 3084.67,4660.32 2551.72,4667.18 2670.86,4681.57 4315.91,4683.99 5540.42,4697.99 6123.58,4698.69 5974.58,4702.63 6457.31,4702.86 3940.97,4706.02 5676.58,4707.38 6298.2,4731.63 3717.68,4739.42 4059,4740.04 5838.42,4744.28 4231.04,4768.83 6372.45,4787.71 3859.03,4793.69 4989.01,4794.42 5109.01,4794.42 5349.01,4794.42 5469.01,4794.42 6195.94,4794.42 2865.99,4813.79 5974.58,4822.63 3974.18,4824.92 5675.28,4827.37 4877.6,4839.01 4146.18,4853.67 5838.42,4864.28 6306.29,4887.82 3889.35,4909.8 6057.64,4919.71 5601.18,4921.76 4792.75,4923.87 5001.5,4930.58 5121.5,4930.58 5361.5,4930.58 5481.5,4930.58 6177.15,4930.58 5974.58,4942.63 5689.42,4946.69 5838.42,4984.28 6371.63,4988.47 4905.97,5003.19 4707.89,5008.72 6265.07,5012.24 3976.44,5023.34 6466.56,5061.88 5972.3,5062.6 3619.72,5067.13 5692.43,5066.65 4623.04,5093.57 6349.93,5097.09 5893.96,5153.5 6455.67,5153.82 5773.97,5154.69 6695.25,5161.95 4736.26,5172.9 4538.19,5178.42 3526.24,5188.31 4651.41,5257.75 4453.33,5263.28 3998.89,5270.45 3306.94,5270.64 4566.56,5342.61 2234.57,5388.45 3998.89,5392.45 4102.37,5418.14 4222.37,5418.14 4342.37,5418.14 4462.37,5418.14 4582.37,5418.14 3902.84,5425.22 2149.72,5473.3 4782.32,5536.93 3902.84,5547.21 5699.44,5549.79 5935.3,5549.72 2064.86,5558.16 6643.57,5559.87 6763.52,5563.18 4098,5567.62 4338,5567.56 4458,5567.53 4578,5567.52 5580.88,5568.31 6053.78,5568.78 6414.27,5615.57 5835.76,5616.74 4867.18,5621.78 2857.06,5626.11 4672.38,5641.63 1980.01,5643.01 6668.78,5665.71 3728.34,5672.05 5525.42,5674.73 6108.58,5675.54 2973.21,5680.96 2338.83,5683.93 3880.64,5699.04 6329.42,5700.42 4952.03,5706.64 4304.69,5709.44 4424.69,5709.77 2943.33,5712.38 4544.55,5715.53 6441.62,5718.54 4757.23,5726.48 3777.57,5726.55 1895.16,5727.86 5823.42,5736.1 2724.59,5748.57 2253.97,5768.78 5661.58,5773.96 4205.02,5776.26 5959.58,5783.48 6244.57,5785.27 3687.29,5787.05 5036.88,5791.49 5156.85,5794.42 5276.85,5794.42 5396.85,5794.42 5516.85,5794.42 6124.91,5794.42 4629.4,5800.39 6356.77,5803.39 3850,5811 4842.09,5811.33 1810.3,5812.72 2639.74,5833.42 4066.53,5839.51 3675.09,5840.61 3619,5843 2169.12,5853.63 5823.42,5856.1 4289.87,5861.11 2959.81,5876.91 4714.26,5885.24 5631.2,5890.05 4926.94,5896.18 1725.45,5897.57 5959.58,5903.48 3560,5906 2554.89,5918.27 6358.55,5923.38 4151.38,5924.36 3795,5930 5038.25,5930.58 5158.25,5930.58 5278.25,5930.58 5398.25,5930.58 5518.25,5930.58 6120.69,5930.58 3734,5934 6240.58,5935.74 2084.27,5938.49 4374.72,5945.97 3987,5960 2874.95,5961.76 4799.11,5970.09 4030.36,5974.02 5823.42,5976.1 5011.79,5981.04 1640.6,5982.42 2470.04,6003.13 6443.4,6008.23 4236.23,6009.21 3845.26,6009.79 5674.42,6013.27 6325.43,6020.59 5959.58,6023.48 1800.68,6024.08 2006.33,6029.73 4459.57,6030.82 3911,6032 3839,6038 2790.1,6046.62 4883.96,6054.94 4115.21,6058.87 6671.73,6059.29 5096.65,6065.89 1555.75,6067.27 4321.09,6094.07 3920.43,6103.33 6410.29,6105.45 1715.82,6108.93 4544.43,6115.67 1863.68,6126.21 5700.8,6130.33 2705.25,6131.47 5926.03,6138.7 4968.82,6139.8 2006.33,6149.73 5181.5,6150.74 1470.89,6152.13 6757.61,6161.82 6637.67,6165.71 2300.33,6172.83 5811.89,6175.73 5378.32,6192.43 1630.97,6193.78 5498.25,6196.55 4629.28,6200.53 2455.86,6209.85 2620.4,6216.32 5053.67,6224.65 4284.92,6228.58 5266.35,6235.6 1386.04,6236.98 1863.68,6246.21 1082.92,6249.67 2215.48,6257.68 4490.79,6263.77 2006.33,6269.73 1546.12,6278.64 967.97,6284.13 5580.64,6283.79 4714.13,6285.38 2371.01,6294.71 5138.52,6309.5 1181.24,6318.47 1301.19,6321.83 2474.93,6328.33 2130.62,6342.54 3959.92,6344.65 4575.65,6348.63 4174.99,6357.89 1461.26,6363.49 1863.68,6366.21 4798.99,6370.23 2286.15,6379.56 901.08,6383.76 2006.33,6389.73 5225.1,6392.6 4454.62,6398.28 5344.48,6404.75 5707.62,6410.49 5587.78,6416.84 1070.51,6426.95 4660.5,6433.48 1376.41,6448.34 2474.93,6448.33 2089.93,6455.42 4883.84,6455.08 2611.08,6455.96 2226.08,6483.44 4539.47,6483.14 1863.68,6486.21 5794.59,6493.17 939.33,6497.5 5500.44,6499.12 5276.63,6503.73 4363.31,6508.71 2006.33,6509.73 1155.37,6511.8 4745.35,6518.33 1282.48,6523.02 4095.68,6538.17 4968.69,6539.94 5653.02,6548.27 385.04,6559.62 6613.81,6559.51 265.1,6563.18 504.99,6563.17 6493.86,6563.08 6733.75,6563.18 2474.93,6568.33 4624.33,6567.99 2089.93,6575.42 2611.08,6575.96 1024.18,6582.35 5415.58,6583.97 1240.22,6596.66 2226.08,6603.44 4830.2,6603.18 1863.68,6606.21 5218.6,6608.76 5798.07,6613.12 5053.54,6624.79 2006.33,6629.73 6393.94,6629.53 603.89,6631.13 5568.17,6633.12 4709.18,6652.84 4095.68,6658.17 981.26,6659.04 438.73,6661.82 6561.98,6661.78 1109.03,6667.2 4533.02,6678.42 1325.07,6681.51 2474.93,6688.33 4915.06,6688.04 2089.93,6695.42 2611.08,6695.96 4238.33,6699.77 5138.4,6709.64 6452.4,6710.7 546.94,6713.69 6309.52,6714.81 688.74,6715.99 5269.5,6717.43 5483.32,6717.97 2226.08,6723.44 1863.68,6726.21 5756.41,6725.66 888.21,6734.81 4794.03,6737.7 2006.33,6749.73 1193.88,6752.06 4617.87,6763.27 5598.88,6766.79 5376.27,6772.21 4999.91,6772.89 4095.68,6778.17 782.27,6791.17 5856.95,6791.17 5976.95,6791.17 6096.95,6791.17 6216.95,6791.17 1365.96,6794.33 5223.25,6794.5 6367.98,6795.98 631.79,6798.54 2474.93,6808.33 2089.93,6815.42 2611.08,6815.96 4238.33,6819.77 1790.62,6821.4 4878.89,6822.55 2226.08,6843.44 4702.72,6848.12 5682.18,6853.16 967.53,6857.23 1955.38,6858.38 5084.76,6857.74 1087.3,6864.67 5308.1,6879.35 1300.66,6895.01 4095.68,6898.17 1705.76,6906.26 4963.74,6907.4 6355.04,6915.28 639.98,6918.26 2469.63,6928.21 2059.37,6931.47 4283.29,6931.03 1186.55,6932.12 5772.32,6932.38 874.85,6933.45 4787.58,6932.98 5892.31,6933.82 6012.31,6933.82 6132.31,6933.82 2611.08,6935.96 755.19,6942.56 1870.53,6943.23 5169.61,6942.59 6251.1,6950.85 2218.42,6963.19 5392.96,6964.2 1620.91,6991.11 5048.59,6992.25 6439.89,7000.13 555.13,7003.11 4153.72,7003.2 2384.77,7013.06 1974.52,7016.32 4368.14,7015.88 4872.43,7017.83 670.34,7027.42 5254.47,7027.45 1785.67,7028.08 6335.95,7035.7 2550.72,7039.67 2134.46,7048.93 5477.81,7049.05 6781.54,7049.52 331.31,7059.29 6661.93,7059.29 451.24,7063.17 6542,7063.17 1536.06,7075.96 5133.44,7077.11 4238.58,7088.05 2299.92,7097.92 1889.66,7101.17 4452.99,7100.74 4957.28,7102.68 585.49,7112.27 5339.32,7112.3 1700.82,7112.93 6420.81,7120.56 2465.86,7124.52 2049.61,7133.78 5562.66,7133.91 1451.2,7160.82 236.3,7161.82 476.2,7161.82 5218.3,7161.96 6533.49,7161.82 356.25,7165.37 6653.43,7165.52 6773.32,7170.74 4323.43,7172.91 2215.07,7182.77 1804.81,7186.03 4537.85,7185.59 5042.14,7187.53 5424.17,7197.15 1615.97,7197.79 2381.01,7209.38 1964.76,7218.63 5647.51,7218.76 1366.35,7245.67 5303.15,7246.81 4408.28,7257.76 2130.22,7267.62 4622.7,7270.44 1719.96,7270.88 5126.99,7272.39 5509.03,7282.01 1531.12,7282.64 6097.09,7289.6 2296.16,7294.23 1879.9,7303.49 5732.37,7303.61 6215.91,7306.38 1281.5,7330.52 5388,7331.67 4493.13,7342.61 2045.36,7352.48 4707.55,7355.29 1635.1,7355.73 5211.84,7357.24 6004.57,7366.02 1446.26,7367.49 5593.88,7366.86 2211.3,7379.08 1795.05,7388.34 5817.22,7388.46 6292.42,7398.82 1196.65,7415.37 5472.86,7416.52 4577.99,7427.46 1960.51,7437.33 4792.41,7440.15 1550.25,7440.59 5296.69,7442.09 5919.71,7450.87 1361.41,7452.34 5678.73,7451.71 2126.45,7463.94 1088.89,7468.18 1710.2,7473.19 5557.71,7501.37 6061.01,7511.31 4662.84,7512.32 978.06,7514.19 6272.51,7517.16 1465.4,7525.44 4877.26,7525 5381.55,7526.94 1276.56,7537.2 5763.58,7536.56 1929.42,7553.23 1625.34,7558.04 379.35,7559.29 6629.33,7559.29 259.41,7563.18 499.28,7563.17 6509.39,7563.18 6749.26,7563.18 2065.58,7567.35 5642.56,7586.22 5975.06,7595.06 4747.69,7597.17 6188.59,7602.94 1380.55,7610.29 4962.11,7609.85 5466.4,7611.8 5856.36,7612.68 917.38,7617.72 1189.85,7620.15 6404.24,7621 599.76,7628.78 1070.81,7635.3 1540.49,7642.9 440.98,7661.82 6554.87,7661.83 6674.81,7665.71 5727.41,7671.08 1929.42,7673.23 4832.55,7682.02 2065.58,7687.35 1295.69,7695.14 5046.96,7694.71 5551.25,7696.65 6319.39,7705.86 6142.48,7713.73 683.08,7715.14 547.63,7716.83 6448.12,7716.64 5968.16,7723.97 1455.64,7727.75 880.21,7731.81 1059.04,7754.72 5812.27,7755.93 4917.4,7766.87 1210.84,7780 5636.11,7781.5 775.92,7791.17 6234.54,7790.71 1929.42,7793.23 6363.27,7801.49 630.96,7803.19 2065.58,7807.35 1370.79,7812.6 5068.63,7812.73 6044,7816.98 974.19,7839.57 5897.12,7840.78 1125.99,7864.85 5720.96,7866.36 4925.98,7886.57 1285.93,7897.45 6128.85,7901.83 1929.42,7913.23 6360.84,7921.46 635.13,7923.11 888.79,7923.88 5981.97,7925.63 2065.58,7927.35 5068.63,7932.73 769.21,7933.82 6241.98,7941.85 1041.13,7949.7 5805.81,7951.21 4835.87,7965.82 1829.16,7979.17 1201.08,7982.31 1709.57,7989.07 6445.47,8006.54 550.28,8007.97 6064.17,8013.06 681.76,8016 4732.51,8026.79 6326.61,8026.93 956.28,8034.56 5890.66,8036.06 2053.82,8046.77 5048,8050.95 6671.09,8059.29 443.73,8063.17 6551.16,8063.37 1116.23,8067.16 1637.84,8085.28 596.9,8100.85 6411.24,8112 4950.24,8120.55 5070.24,8120.55 5190.11,8126.14 1835.69,8128.17 1955.69,8128.82 6068.83,8132.97 4715.05,8145.51 5926.18,8150.69 929.42,8151.51 253.67,8161.82 493.55,8161.82 6520.28,8162.11 6760.17,8161.82 373.61,8165.71 6640.23,8165.57 1065.58,8175.95 2054.17,8197.38 1653.14,8204.3 5274.76,8211.19 4779.14,8246.96 6068.83,8252.97 5878.89,8260.98 4898.04,8263.19 5018.04,8263.19 1756.96,8264.48 1876.96,8264.33 929.42,8271.51 5137.54,8274.14 5762.63,8290.69 1065.58,8295.95 2065.58,8316.84 5273.66,8331.19 4931.9,8364.52 6031.37,8366.97 1929.42,8372.25 929.42,8391.51 5717.48,8401.88 5186.52,8413.69 1081.98,8414.82 5921.83,8415.98 2099.19,8432.03 5068.63,8436.08 6034.94,8456.05 1858.67,8469.17 1187.7,8471.6 848.09,8479.75 2208.71,8481.08 4925.98,8484.38 2048.38,8511.55 5750.33,8517.29 1054.86,8518.02 934.97,8523.2 1929.6,8528.57 1773.82,8554.03 5068.63,8556.08 5862.99,8558.62 763.24,8564.6 6068.83,8571.16 1244.47,8577.32 2260.28,8589.44 2136.97,8592.5 4899.68,8601.46 1139.71,8602.88 850.12,8608.05 1844.74,8613.42 1701.42,8649.73 5136.38,8655.12 6145.08,8663.82 701.42,8667.45 4801.89,8671.01 5837.79,8675.95 4950.97,8686.03 5966.58,8686.67 5065.04,8723.29 6076.52,8734.77 5221.23,8739.97 4705.6,8742.63 6229.93,8748.67 4853.18,8755.58 5752.72,8760.58 1695.46,8769.58 5881.72,8771.52 694.29,8787.24 1300.12,8806.63 5149.89,8808.14 2194.86,8813.54 6161.37,8819.62 2300.71,8823.64 1194.29,8828.59 5296.49,8833.44 800.71,8837.25 6296.82,8848.3 5796.82,8856.33 4795.1,8860.59 4696.46,8862.28 5698.18,8867.47 1698.18,8889.55 698.18,8907.18 5198.18,8918 1298.52,8926.62 2310.84,8943.21
  other v3: 5156.24,1322.03 5016.76,1329.61 5156.24,1357.03 845.56,1600.29 2400.2,2038.4 5340,2599 5112.5,2668.5 5281,2994.98 3737.8,3015.7 4150.49,5082.02 4238.63,5569.45
  other v4: 6043.54,2263.72 3523.37,3598.98 3434.65,3599.56
  other v5: 6392.2,1882.19 6350.86,1931.4 6392.2,1931.4 6433.54,1931.4 6392.2,1980.61 5970.95,1994.06 5921.73,2035.4 5970.95,2035.4 6020.16,2035.4 5970.95,2076.74 5075.06,2784.28 5033.72,2833.49 5075.06,2833.49 5116.4,2833.49 5075.06,2882.7 3412.87,5333.66 3459.72,5333.66 3506.57,5333.66 3553.43,5333.66 3369.96,5376.57 3412.87,5376.57 3459.72,5376.57 3506.57,5376.57 3553.43,5376.57 3596.34,5376.57 3369.96,5423.43 3412.87,5423.43 3459.72,5423.43 3506.57,5423.43 3553.43,5423.43 3596.34,5423.43 3369.96,5470.28 3412.87,5470.28 3459.72,5470.28 3506.57,5470.28 3553.43,5470.28 3596.34,5470.28 3369.96,5517.13 3412.87,5517.13 3459.72,5517.13 3506.57,5517.13 3553.43,5517.13 3596.34,5517.13 3412.87,5560.04 3459.72,5560.04 3506.57,5560.04 3553.43,5560.04
  other v6: 6560.67,4573.5 3706.5,4972.3 6560.67,5151.49 6560.67,5573.5 6560.67,6151.49 708.51,8723.67 1286.5,8723.67 1708.51,8723.67 2286.5,8723.67 5309,8942 5685,8942 5810,8942 4810,8943 6310,8943 6184,8945
  other v7: 1742,448 1362.71,846.85
  other v8: 5477.36,822.3 6150.8,954.4 6149.7,1039.5 6291.8,1115.2 6317.1,1145.6 6317.1,1188.9 6317.1,1238.7 6316.1,1437.9 6291.2,1606.9
IN0_N: R31.2 U1.35 | length 241.5
  L1-Top Layer (GTL) w8: U1.35@3591.42,5620.08 3591.42,5635.89 3593.26,5637.73 3593.26,5649.07 3706.78,5762.59 3706.78,5796.53
  L1-Top Layer (GTL) w11: 3706.78,5796.53 R31.2@3719.02,5808.77
IN0_P: R27.2 U1.34 | length 228.4
  L1-Top Layer (GTL) w8: U1.34@3611.1,5620.08 3611.1,5635.89 3609.26,5637.73 3609.26,5642.45 3718.2,5751.39 3752.14,5751.39
  L1-Top Layer (GTL) w11: 3752.14,5751.39 R27.2@3764.38,5763.63
IN1_N: R38.2 U1.38 | length 320.1
  L1-Top Layer (GTL) w8: U1.38@3532.36,5620.08 3532.36,5635.89 3530.52,5637.73 3530.52,5695.52 3550,5715 3550,5754 3584.69,5788.69 3584.69,5856.21 3594.76,5866.29 3625.51,5866.29 R38.2@3636.69,5877.47
IN1_P: R34.2 U1.39 | length 332.5
  L1-Top Layer (GTL) w8: U1.39@3512.68,5620.08 3512.68,5635.89 3514.52,5637.73 3514.52,5702.15 3534,5721.63 3534,5760.63 3568.69,5795.31 3568.69,5862.84 3582.81,5876.96 3582.81,5907.71 R34.2@3593.99,5918.89
LDO1: C2.1 JP1.3 U10.10 U10.11 U10.12 | length 1539.8
  L1-Top Layer (GTL) w60: JP1.3@5408,978 5787,978 v14(5893.7,1084.7)
  L8-Bottom Layer (GBL) w10: 5890.2,1932.4 5891.3,1933.5 5921.73,1933.5 U10.12@5921.73,1960.6 ; 5920.42,1932.18 5941.42,1932.18 U10.11@5941.42,1960.6 ; 5943.3,1930.3 5961.1,1930.3 U10.10@5961.1,1960.6
  L8-Bottom Layer (GBL) w60: v14(5893.7,1084.7) 5924.55,1115.55 5924.55,1632.05 5893.7,1662.9 C2.1@5893.7,1801.4 5895.2,1912.4
LDO2: C9.1 JP2.3 U11.10 U11.11 U11.12 | length 1191
  L1-Top Layer (GTL) w50: JP2.3@5489,1539.3 v10(5986.55,1539.3)
  L8-Bottom Layer (GBL) w10: C9.1@6195.2,1907.9 C9.1@6212.7,1907.9 ; 6283.04,1959.61 6283.04,1941.24 U11.10@6317.4,1941.24 ; U11.11@6317.4,1960.93 6281.73,1960.93 6282.2,1961.4 6282.2,1980.61 U11.12@6317.4,1980.61
  L8-Bottom Layer (GBL) w45: C9.1@6204.2,1906.4 6267.2,1951.4
  L8-Bottom Layer (GBL) w50: v10(5986.55,1539.3) 6195.2,1747.95 C9.1@6195.2,1907.9
LDO3: C23.1 JP4.3 U9.10 U9.11 U9.12 | length 1023.8
  L1-Top Layer (GTL) w60: JP4.3@4560.3,2347.6 4766.7,2347.6 v14(4789.4,2370.3)
  L8-Bottom Layer (GBL) w10: C23.1@4933,2911.5 4939,2905.5 4965.5,2879 4970,2879 ; U9.10@5000.26,2843.33 4970.33,2843.33 4970,2843.66 4970,2863 ; U9.11@5000.26,2863.02 4970.02,2863.02 ; U9.12@5000.26,2882.7 4973.7,2882.7 4970,2879 ; 4970,2863 4970,2879
  L8-Bottom Layer (GBL) w60: v14(4789.4,2370.3) 4789.4,2755.9 4939,2905.5 C23.1@4946,2912.5
LDO3_IN: C1.1 C8.1 C10.1 C22.1 D1.1 J2.1 J500.1 JP1.5 R201.1 R202.1 R203.1 U9.1 U9.2 U9.3 U10.1 U10.2 U10.3 U11.1 U11.2 U11.3 | length 8840.7
  L1-Top Layer (GTL) w30: 5418,2553 5456.8,2514.2 5684.6,2514.2 5771.58,2427.22 v8(5771.58,1645.42) ; 6150.14,827.24 v3(6150.14,875.54)
  L1-Top Layer (GTL) w50: JP1.5@5408,1078 5644.5,1078 v10(5660.2,1062.3) ; 5660.2,623.9 v10(5660.2,720.5)
  L1-Top Layer (GTL) w60: 5418,2553 v14(5418,2601) ; 6704,1471.9 v10(6705.7,1833.4)
  L1-Top Layer (GTL) w100: J500.1@5305.7,101.2 5260,146.9 5260,437.53 5442.65,620.18 6375.18,620.18 6585,830 6585,910.4 6670.81,996.21 6670.81,1445.8 6715.01,1490 J2.1@6896.57,1490 J2.1@6897.17,1490
  L8-Bottom Layer (GBL) w8: U9.3@5149.87,2843.33 5192.33,2843.33 5192.33,2879.33 5188.96,2882.7 U9.1@5149.87,2882.7 ; U9.2@5149.87,2863.02 5191.35,2863.02
  L8-Bottom Layer (GBL) w10: 5899.67,2139.93 5921.73,2139.93 ; U10.1@5921.73,2110.2 5921.73,2139.93 ; U10.2@5941.42,2110.2 5941.42,2140.18 5941.2,2140.4 5922.2,2140.4 5921.73,2139.93 ; 5942.1,2139.5 5961.1,2139.5 U10.3@5961.1,2110.2 ; U11.3@6467,1941.24 6503.2,1941.4 6503.2,1961.4 ; U11.2@6467,1960.93 6503.2,1961.4 ; U11.1@6467,1980.61 6503.2,1980.4 ; 6503.2,2069.4 6503.2,1980.4 ; 6503.2,1961.4 6503.2,1980.4
  L8-Bottom Layer (GBL) w30: v8(5771.58,1645.42) 5771.58,1119.34 6015.38,875.54 v3(6150.14,875.54)
  L8-Bottom Layer (GBL) w50: v10(5660.2,720.5) v10(5660.2,1062.3)
  L8-Bottom Layer (GBL) w60: C22.1@5197.5,2936.5 5340,2936.5 5340,2932.5 ; 5343.5,2929.01 5343.5,2722 5418,2722 v14(5418,2601) ; 5910.2,2157.4 5910.2,2316.33 5945.77,2351.9 6126.7,2351.9 R201.1@6126.7,2205.4 C1.1@6189.7,2205.4 ; C1.1@6191.2,2206.9 6568.7,2206.9 6705.7,2069.9 ; 6515.2,2069.4 6559.21,2069.68 6594.2,2069.9 6705.7,2069.9 ; v10(6705.7,1776.9) v10(6705.7,1833.4) 6705.7,2069.9
LF1: C75.1 C76.2 C77.1 TP29.1 U1.49 | length 538.7
  L1-Top Layer (GTL) w8: TP29.1@3140.18,5822.1 3177.27,5785.01 C75.1@3177.27,5741.54 3177.27,5718.77 3258.4,5637.64 3268.38,5637.64 3291.53,5614.49 3291.53,5597.6 3294.64,5594.49 U1.49@3309.92,5594.49
  L1-Top Layer (GTL) w11: v1(3114.06,5848.22) TP29.1@3140.18,5822.1
  L8-Bottom Layer (GBL) w11: C77.1@2964.04,5942.43 C76.2@3031.45,5875.02 3058.25,5848.22 v1(3114.06,5848.22)
LF2: C72.1 C73.2 C74.1 TP28.1 U1.19 | length 700.6
  L1-Top Layer (GTL) w8: U1.19@3656.38,5338.58 3671.42,5338.58 3705.54,5304.46 3705.54,5286.65 3736.59,5255.6 3736.59,5231.18 3816.32,5151.45 3881.02,5151.45 TP28.1@3903.24,5129.23 ; C72.1@3949.03,5160.07 3934.08,5160.07 TP28.1@3903.24,5129.23 ; v1(3998.59,5049.9) 3969.65,5078.84 3953.63,5078.84 TP28.1@3903.24,5129.23
  L8-Bottom Layer (GBL) w8: v1(3998.59,5049.9) 4030.86,5017.63 C74.1@4108.53,4939.96
LMKGPIO0: C88.1 S1.5 S1.6 S1.7 S1.8 TP31.1 U1.50 | length 6324
  L1-Top Layer (GTL) w8: v1(3263.86,5607.21) 3263.86,5601.97 3291.03,5574.8 U1.50@3309.92,5574.8
  L1-Top Layer (GTL) w11: S1.5@3010.2,448.55 3037.94,448.55 3070.7,481.31 3070.7,515.81 3037.96,548.55 S1.6@3036.94,548.55 ; S1.6@3010.2,548.55 S1.6@3036.94,548.55 ; S1.7@3010.2,648.55 S1.7@3035.96,648.55 ; S1.8@3010.2,748.55 S1.8@3035.96,748.55 ; S1.8@3036.7,748.55 S1.8@3035.96,748.55 ; S1.8@3038.1,748.55 3076.1,786.55 C88.1@3076.1,837.5 ; C88.1@3076,840.5 TP31.1@3377.5,840.5 ; TP31.1@3378,840 v3(3378,988) ; S1.7@3035.96,648.55 3065.7,618.81 3065.7,577.31 S1.6@3036.94,548.55 ; S1.7@3035.96,648.55 3036.44,648.55 3067.7,679.81 3067.7,716.81 S1.8@3035.96,748.55
  L6-Mid-Layer 5 (G4) w5: v1(3263.86,5607.21) 3105.21,5607.21 2706,5208 2706,4743 3085,4364 3085,1281 v3(3378,988)
LMKGPIO1: C91.1 S2.5 S2.6 S2.7 S2.8 TP33.1 U1.64 | length 4813.5
  L1-Top Layer (GTL) w11: S2.5@3010.8,1197.55 3038.54,1197.55 3071.3,1230.31 3071.3,1264.81 3038.55,1297.55 S2.6@3037.54,1297.55 ; S2.6@3010.8,1297.55 S2.6@3037.54,1297.55 ; S2.7@3010.8,1397.55 S2.7@3036.55,1397.55 ; S2.8@3010.8,1497.55 S2.8@3036.55,1497.55 ; S2.8@3037.3,1497.55 S2.8@3036.55,1497.55 ; S2.8@3044.9,1497.55 3082.9,1535.55 C91.1@3082.9,1586.5 ; C91.1@3083,1585.5 3379.5,1585.5 3380,1586.01 v3(3380,1729) ; v18(3270.9,5269.61) 3300.5,5299.21 U1.64@3309.92,5299.21 ; S2.7@3036.55,1397.55 3037.04,1397.55 3068.3,1428.81 3068.3,1465.81 S2.8@3036.55,1497.55 ; S2.7@3036.55,1397.55 3066.3,1367.81 3066.3,1326.31 S2.6@3037.54,1297.55
  L6-Mid-Layer 5 (G4) w5: v18(3270.9,5269.61) 3270.9,5226.1 3310,5187 3310,4882 3134,4706 3134,1975 v3(3380,1729)
LMKGPIO2: C95.1 S4.5 S4.6 S4.7 S4.8 TP38.1 U1.10 | length 4120.1
  L1-Top Layer (GTL) w5: v3(3315,2493) 3378,2430 TP38.1@3378,2357
  L1-Top Layer (GTL) w7: U1.10@3512.68,5273.62 3512.68,5246.1 v1(3514.43,5244.35)
  L1-Top Layer (GTL) w11: S4.5@3008.39,1966.55 3037.39,1966.55 3069.89,1999.05 3069.89,2033.55 3036.89,2066.55 S4.6@3035.89,2066.55 ; S4.6@3008.39,2066.55 S4.6@3035.89,2066.55 ; S4.7@3008.39,2166.55 S4.7@3035.39,2166.55 ; S4.8@3008.39,2266.55 S4.8@3034.89,2266.55 ; C95.1@3074,2354.5 C95.1@3074.29,2354.5 ; TP38.1@3375.5,2354.5 C95.1@3074.29,2354.5 ; S4.8@3034.89,2266.55 3064.89,2236.55 3064.89,2195.55 3035.89,2166.55 S4.7@3035.39,2166.55 ; S4.8@3034.89,2266.55 3036.29,2266.55 3074.29,2304.55 C95.1@3074.29,2354.5 ; S4.7@3035.39,2166.55 3069.89,2132.05 3069.89,2100.55 S4.6@3035.89,2066.55
  L6-Mid-Layer 5 (G4) w5: v3(3315,2493) 3279,2493 3169,2603 3169,4675 3360,4866 3360,5182 3422.35,5244.35 v1(3514.43,5244.35)
LMKPDN: C96.1 R75.2 R76.2 R77.1 TP40.1 U1.36 | length 6009.8
  L1-Top Layer (GTL) w5: U1.36@3571.73,5620.08 3571.73,5667.14 v1(3578.17,5673.58)
  L1-Top Layer (GTL) w11: R76.2@337.14,1704.22 R77.1@337.14,1781.22 R75.2@267.14,1781.22 205.78,1781.22 168,1819 168,1993 195.61,2020.61 TP40.1@294.81,2020.61 321.45,2047.25 C96.1@489.66,2047.25 v3(489.66,2126.66)
  L6-Mid-Layer 5 (G4) w5: v3(489.66,2126.66) 804,2441 804,3357 3120.58,5673.58 v1(3578.17,5673.58)
LMKSCK: C92.1 JP5.B02 JP5.B04 R60.1 R61.1 TP34.1 U1.17 | length 7708.3
  L1-Top Layer (GTL) w7: U1.17@3656.38,5299.21 3670.48,5299.21 3676.32,5293.37 3676.32,5262.45 v1(3667.74,5253.87)
  L1-Top Layer (GTL) w10: C92.1@1429.04,2085.18 1500.82,2085.18 1528.36,2057.64 JP5.B04@1528.36,1880.88
  L1-Top Layer (GTL) w11: JP5.B02@1328.36,1880.88 1328.36,2079.14 1334.4,2085.18 C92.1@1429.04,2085.18 1429.04,2286.96 1378,2338 1378,2474 1390.9,2486.9 R61.1@1423.91,2486.9 1423.91,2576.91 1806,2959 TP34.1@2000,2959 2000,3025 2123,3148 2929,3148 2996,3081 2996,3003 3274.5,2724.5 v3(3304.5,2724.5) ; R60.1@1332.11,2090.66 R60.1@1332.69,2091.24
  L6-Mid-Layer 5 (G4) w5: v3(3304.5,2724.5) 3353,2676 4418,2676 4542,2800 4542,3897 3782,4657 3782,4958 3667.74,5072.26 v1(3667.74,5253.87)
LMKSCS_ADD: C94.1 JP5.B07 S3.1 S3.2 TP37.1 U1.18 | length 6768.3
  L1-Top Layer (GTL) w7: U1.18@3656.38,5318.9 3670.6,5318.9 3690.32,5299.17 3690.32,5262 v1(3698.69,5253.63)
  L1-Top Layer (GTL) w11: JP5.B07@1828.36,1880.88 1828.36,1968.36 1950.22,2090.22 S3.1@2131.76,2090.22 S3.1@2131.76,2065.23 ; S3.1@2131.76,2064.73 S3.1@2131.76,2065.23 ; v3(3340,2630) 3256,2630 2930,2956 TP37.1@2756,2956 2756,2887 2697,2828 2616,2828 2377.5,2589.5 C94.1@2377.5,2361 2377.5,2143.5 2324.22,2090.22 S3.2@2231.76,2090.22 2231.76,2062.73 2201.76,2032.73 2164.26,2032.73 S3.1@2131.76,2065.23
  L6-Mid-Layer 5 (G4) w5: v3(3340,2630) 3352,2642 4455,2642 4586,2773 4586,3910 3823,4673 3823,4965 3707,5081 3707,5245.32 v1(3698.69,5253.63)
LMKSDIO: C93.1 JP5.B01 JP5.B05 R59.1 TP36.1 U1.16 | length 7721.3
  L1-Top Layer (GTL) w5: U1.16@3630.79,5273.62 3630.79,5257.47 3662.62,5225.64 v1(3686.71,5225.64)
  L1-Top Layer (GTL) w11: R59.1@1232.5,2010 1228.36,2005.86 JP5.B01@1228.36,1880.88 1228.36,1802.64 1236,1795 1561,1795 1574,1808 1574,1915 JP5.B05@1628.36,1915 ; JP5.B05@1628.36,1880.88 JP5.B05@1628.36,1915 ; JP5.B05@1630,1915 JP5.B05@1628.36,1915 ; v3(3313,2674) 3268,2674 2952,2990 2952,3050 2903,3099 2443,3099 2378,3034 TP36.1@2378,2959 2378,2884 2321,2827 2236,2827 1998,2589 1998,2234 1847.49,2083.49 1704.79,2083.49 1656.49,2083.49 1628.36,2055.36 JP5.B05@1628.36,1915
  L6-Mid-Layer 5 (G4) w5: v3(3313,2674) 3329,2658 4432,2658 4564,2790 4564,3902 3801,4665 3801,4964 3686.71,5078.29 v1(3686.71,5225.64)
NetC3_1: C3.1 U1.7 | length 94.6
  L1-Top Layer (GTL) w8: C3.1@3443.39,5183.3 3443.39,5239.81 3453.62,5250.05 U1.7@3453.62,5273.62
NetC7_1: C7.1 U10.4 | length 93.6
  L8-Bottom Layer (GBL) w10: U10.4@5980.79,2110.2 5981.07,2110.49 5981.07,2174.02 5980.79,2174.3 5980.79,2194.49 C7.1@5987.2,2200.9
NetC13_1: C13.1 U11.4 | length 217.7
  L8-Bottom Layer (GBL) w10: U11.4@6467,1921.56 6530.2,1921.4 6547.2,1938.4 6634.2,1938.4 C13.1@6634.2,1894.9
NetC24_1: C24.1 U9.4 | length 149.1
  L8-Bottom Layer (GBL) w8: U9.4@5149.87,2823.65 5230.86,2823.65 C24.1@5279,2775.5
NetC82_1: C82.1 R207.2 Y2.4 | length 127
  L1-Top Layer (GTL) w20: R207.2@3928.5,2927 3928.5,2985.7 3928.88,2986.07 Y2.4@3928.88,3053.89
NetC83_1: C83.1 R208.1 Y3.4 | length 148.3
  L1-Top Layer (GTL) w10: Y3.4@3759.14,3546 C83.1@3759.14,3624.84
  L1-Top Layer (GTL) w20: C83.1@3759.14,3624.84 R208.1@3828.56,3624.84
NetC84_1: C84.1 R209.2 Y4.4 | length 171.6
  L8-Bottom Layer (GBL) w20: Y4.4@3775.47,3755.47 R209.2@3775.47,3927.03
NetC85_1: C85.1 R210.2 Y5.3 | length 237.3
  L8-Bottom Layer (GBL) w20: R210.2@3619.07,2453.5 3619.07,2404.93 3638.38,2385.62 Y5.3@3799.78,2385.62
NetC86_1: C86.1 TP30.1 Y4.1 | length 291.7
  L8-Bottom Layer (GBL) w20: Y4.1@3932.95,3755.47 4187.67,3755.47 TP30.1@4213.84,3781.64
NetC87_1: C87.1 R211.2 U4.6 | length 122.5
  L1-Top Layer (GTL) w8: R211.2@3671,3120.5 3730.25,3120.5 3732.52,3118.23 U4.6@3792.57,3118.23
NetC90_1: C90.1 D8.3 Q2.1 R62.2 | length 279.6
  L1-Top Layer (GTL) w11: D8.3@1772.65,2386.9 1810.05,2424.3 Q2.1@1858.17,2424.3 ; D8.3@1778.91,2380.65 1778.91,2340.29 1798.55,2320.65 C90.1@1798.55,2275.2 R62.2@1798.55,2210.2
NetC132_2: C132.2 R145.2 U6.4 | length 110.2
  L1-Top Layer (GTL) w10: 856.09,1200.18 U6.4@875.22,1200.18
  L1-Top Layer (GTL) w15: R145.2@821.09,1206.68 849.6,1206.68 856.09,1200.18
  L1-Top Layer (GTL) w20: C132.2@767.16,1206.09 R145.2@820.5,1206.09
NetC135_1: C135.1 U8.69 Y6.1 | length 553
  L1-Top Layer (GTL) w10: C135.1@1012.71,843.35 1162.2,843.35 Y6.1@1162.71,843.86 1162.71,696.85 1188.18,671.38 U8.69@1407.95,671.38
NetC136_1: C136.1 U8.70 Y6.2 | length 559
  L1-Top Layer (GTL) w10: C136.1@1016.21,469.84 Y6.2@1162.71,469.84 1162.71,626.85 1187.55,651.69 U8.70@1407.95,651.69
NetC137_2: C137.2 R161.1 U8.1 | length 328.5
  L1-Top Layer (GTL) w10: C137.2@1217.71,278.35 R161.1@1272.71,278.35 1272.71,311.85 1337.95,377.09 U8.1@1485.7,377.09
NetC138_2: C138.2 R162.1 U8.2 | length 240.9
  L1-Top Layer (GTL) w10: C138.2@1327.71,278.35 R162.1@1387.71,278.35 1443.41,334.05 1500.41,334.05 1505.39,339.03 U8.2@1505.39,377.09
NetC139_1: C139.1 R165.2 U8.76 | length 483.9
  L1-Top Layer (GTL) w10: C139.1@1151.21,220.35 C139.1@1152.71,221.85 R165.2@1152.71,276.85 1152.71,306.85 1172.71,326.85 1218.96,326.85 1322.71,430.6 1322.71,511.85 1344.44,533.58 U8.76@1407.95,533.58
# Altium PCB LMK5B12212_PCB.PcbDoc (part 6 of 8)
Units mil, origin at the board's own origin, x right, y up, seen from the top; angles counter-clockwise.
Board outline 7000 x 9161 mil, 8 copper layers (L1-Top Layer (GTL), L2-GND Plane (GP1), L3-Mid-Layer 2 (G1), L4-Mid-Layer 3 (G2), L5-Mid-Layer 4 (G3), L6-Mid-Layer 5 (G4), L7-Mid-Layer 6 (G5), L8-Bottom Layer (GBL)), stack 61.2 mil thick; 469 components, 264 nets, 1268 pads, 1812 vias.

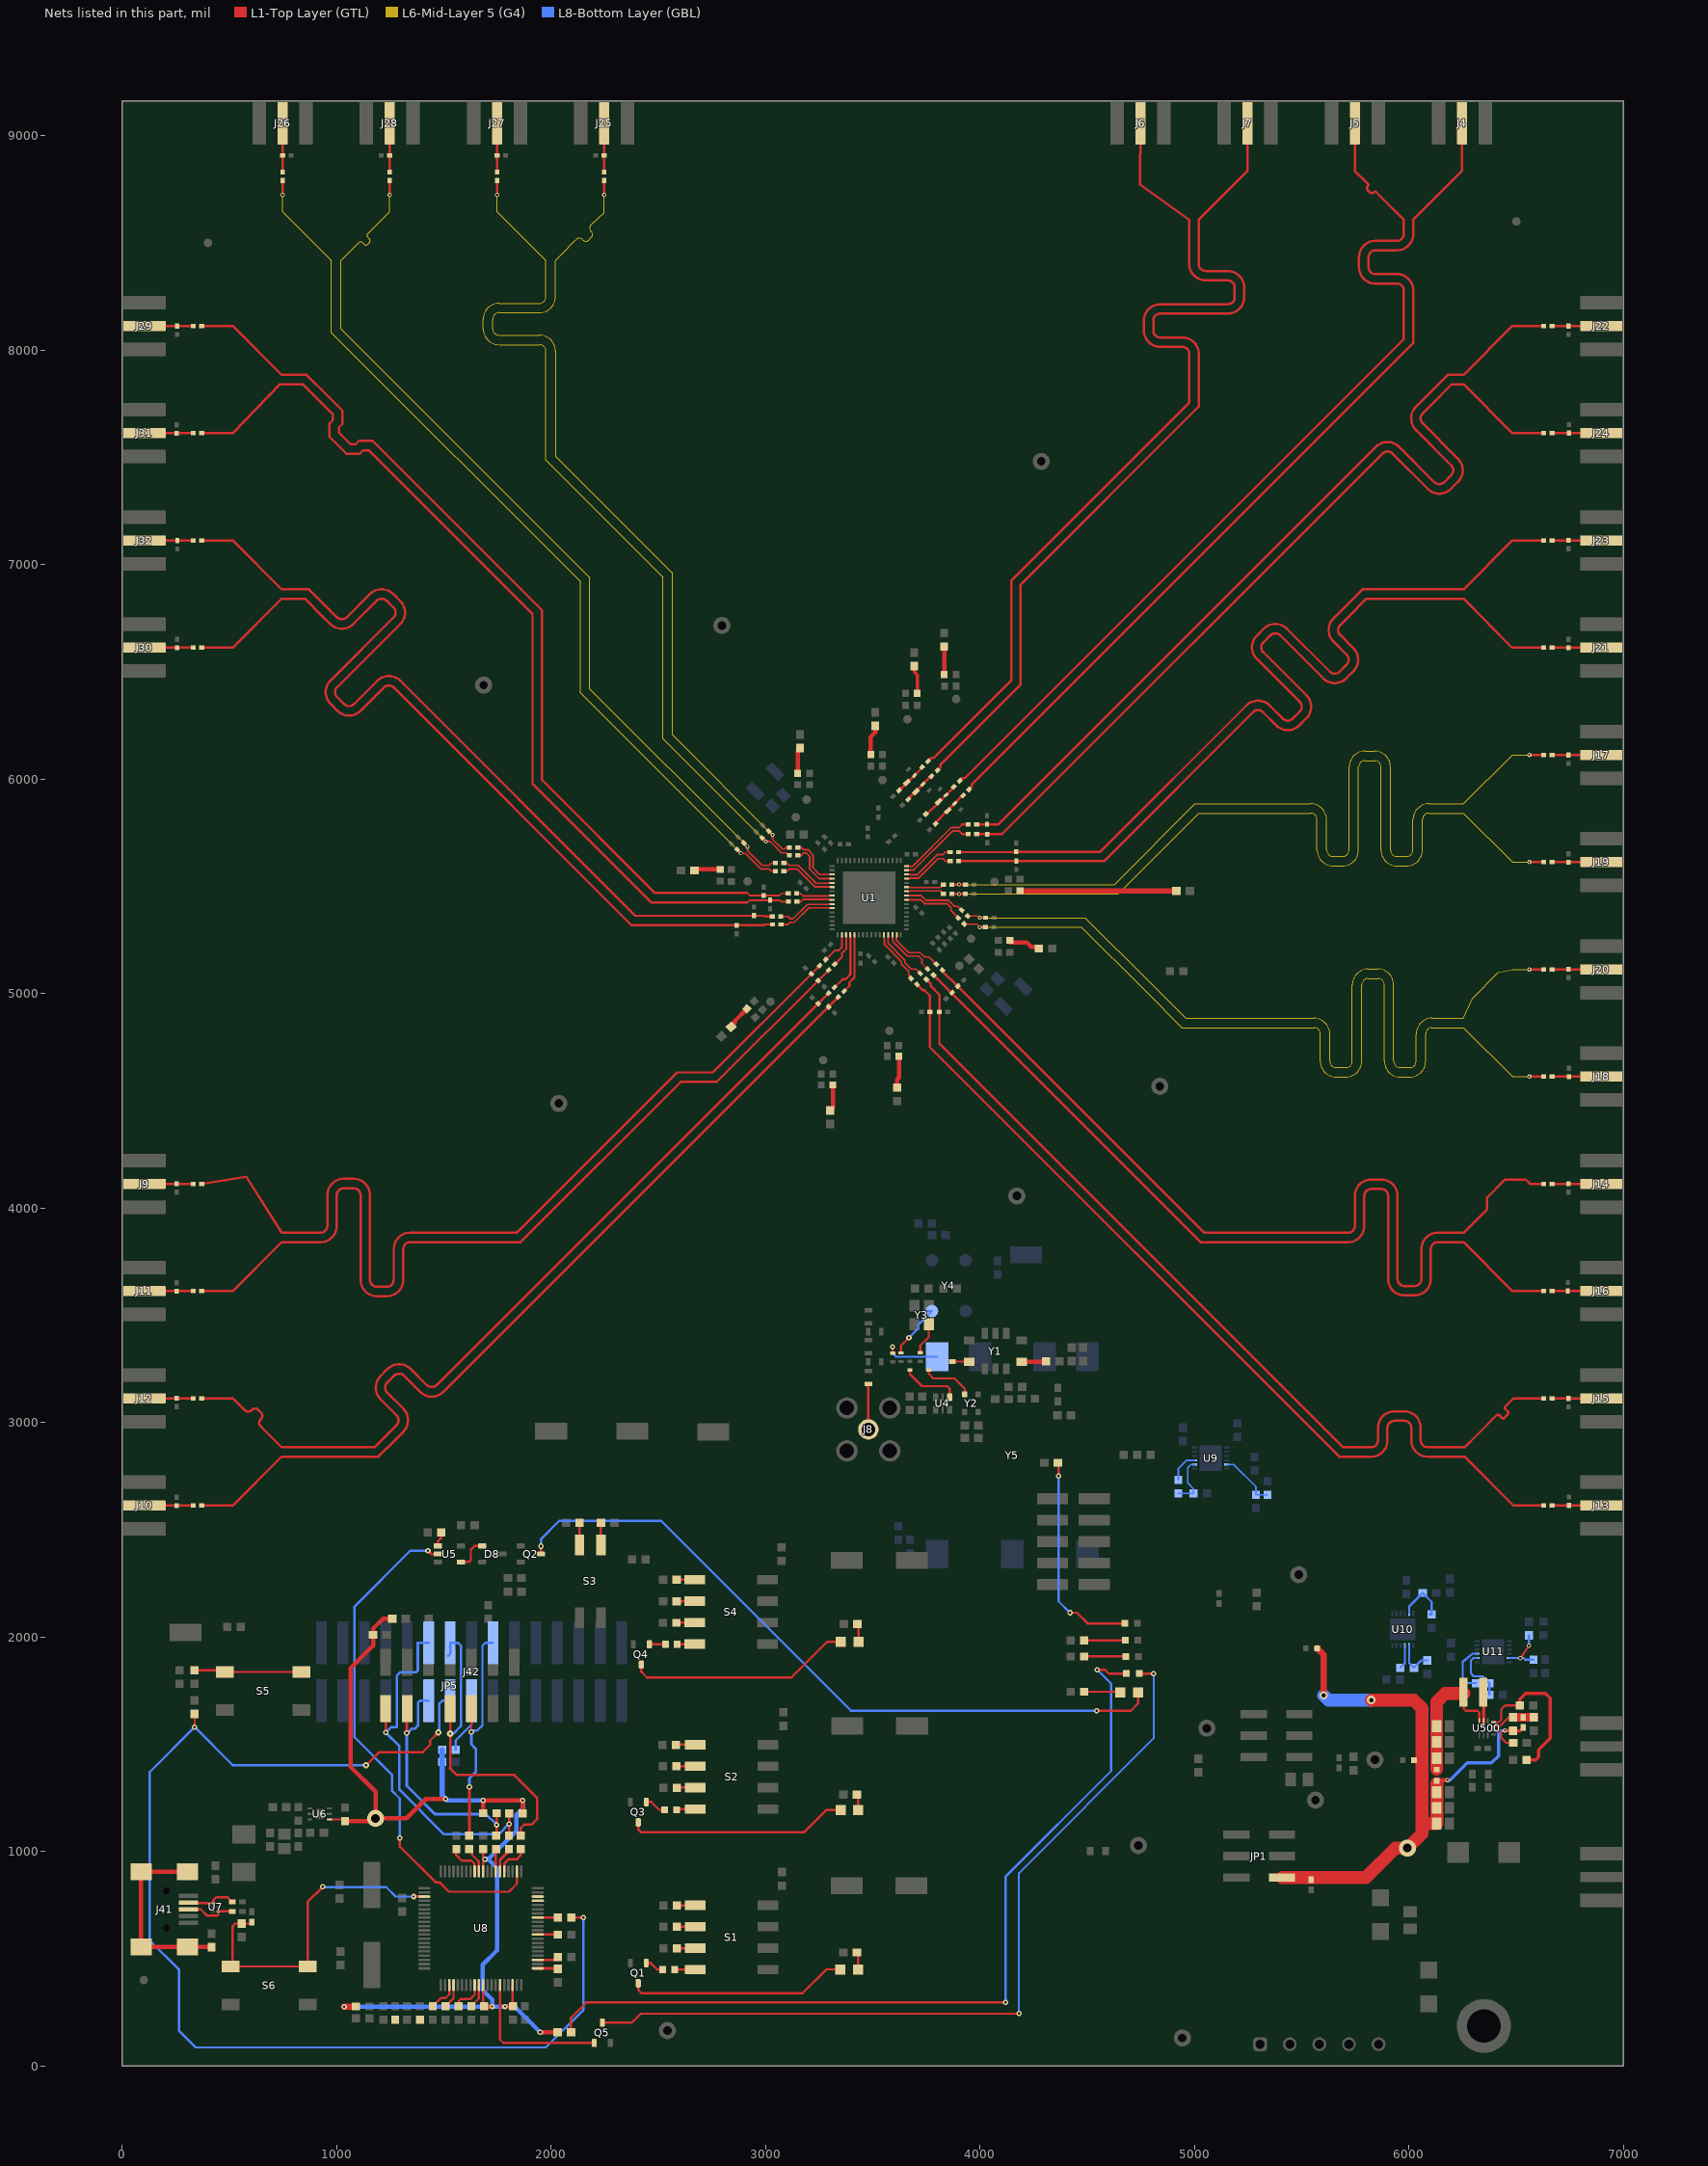
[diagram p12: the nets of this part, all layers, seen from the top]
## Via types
v1: diameter 20, hole 10, L1-Top Layer (GTL) to L8-Bottom Layer (GBL), tented top, 987 vias
v2: diameter 30, hole 12, L1-Top Layer (GTL) to L8-Bottom Layer (GBL), 407 vias
v3: diameter 25, hole 12, L1-Top Layer (GTL) to L8-Bottom Layer (GBL), tented top, 163 vias
v4: diameter 30, hole 12, L1-Top Layer (GTL) to L8-Bottom Layer (GBL), tented top, 52 vias
v5: diameter 19.68, hole 7.87, L1-Top Layer (GTL) to L8-Bottom Layer (GBL), 47 vias
v6: diameter 20, hole 10, L1-Top Layer (GTL) to L8-Bottom Layer (GBL), 39 vias
v7: diameter 25, hole 10, L1-Top Layer (GTL) to L8-Bottom Layer (GBL), tented top, 35 vias
v8: diameter 25, hole 12, L1-Top Layer (GTL) to L8-Bottom Layer (GBL), 23 vias
v9: diameter 30, hole 10, L1-Top Layer (GTL) to L8-Bottom Layer (GBL), 10 vias
v10: diameter 40, hole 20, L1-Top Layer (GTL) to L8-Bottom Layer (GBL), 10 vias
v11: diameter 18, hole 10, L1-Top Layer (GTL) to L8-Bottom Layer (GBL), tented top, 8 vias
v12: diameter 20, hole 10, L1-Top Layer (GTL) to L8-Bottom Layer (GBL), tented both sides, 6 vias
v13: diameter 39.37, hole 19.68, L1-Top Layer (GTL) to L8-Bottom Layer (GBL), tented top, 6 vias
v14: diameter 50, hole 28, L1-Top Layer (GTL) to L8-Bottom Layer (GBL), 4 vias
v15: diameter 23, hole 10, L1-Top Layer (GTL) to L8-Bottom Layer (GBL), tented top, 4 vias
v16: diameter 25, hole 10, L1-Top Layer (GTL) to L8-Bottom Layer (GBL), 4 vias
v17: diameter 25, hole 12, L1-Top Layer (GTL) to L8-Bottom Layer (GBL), tented both sides, 3 vias
v18: diameter 20/0/0/0/0/0/20 (per signal layer), hole 10, L1-Top Layer (GTL) to L8-Bottom Layer (GBL), tented top, 2 vias
v19: diameter 30, hole 12, L1-Top Layer (GTL) to L8-Bottom Layer (GBL), tented both sides, 1 vias
v20: diameter 25, hole 10, L1-Top Layer (GTL) to L8-Bottom Layer (GBL), tented both sides, 1 vias

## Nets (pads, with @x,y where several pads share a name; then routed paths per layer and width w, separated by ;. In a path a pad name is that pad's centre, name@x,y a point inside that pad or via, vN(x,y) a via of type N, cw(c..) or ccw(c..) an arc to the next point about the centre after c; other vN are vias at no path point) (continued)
NetC154_1: C154.1 R201.2 U10.5 | length 249.1
  L8-Bottom Layer (GBL) w10: U10.5@6000.47,2110.2 6000.47,2142.17 R201.2@6063.7,2205.4 6105.2,2163.9 C154.1@6105.2,2104.9 C154.1@6095.21,2104.9
NetC155_1: C155.1 R202.2 U11.5 | length 236.5
  L1-Top Layer (GTL) w10: v6(6519.2,1900.4) v6(6559.2,1959.4)
  L8-Bottom Layer (GBL) w10: U11.5@6467,1901.87 6519.19,1902.29 6533.2,1902.4 6541.7,1893.9 C155.1@6580.2,1893.9 ; v6(6559.2,1959.4) R202.2@6559.2,2007.9
NetC156_1: C156.1 R203.2 U9.5 | length 265.4
  L8-Bottom Layer (GBL) w8: U9.5@5149.87,2803.96 5182.04,2803.96 5286,2700 C156.1@5286,2662.5 ; C156.1@5291.32,2662.5 R203.2@5340,2662.5
NetC501_1: C501.1 C502.1 C503.1 L500.1 L501.2 U500.3 | length 644.5
  L1-Top Layer (GTL) w10: L501.2@6255.75,1736.2 6255.75,1665.05 6265.2,1655.6 6318.8,1655.6 6327.97,1646.43 U500.3@6327.97,1608.45
  L1-Top Layer (GTL) w60: L500.1@6128.97,1384.43 C503.1@6128.97,1434.1 C502.1@6128.97,1510.6 C501.1@6128.97,1584.4 6128.97,1696.77 6168.4,1736.2 L501.2@6255.75,1736.2
NetC504_1: C504.1 C508.1 C509.1 C510.1 C511.1 JP1.1 L500.2 L502.1 L503.1 R501.2 TP1.1 | length 2851.6
  L1-Top Layer (GTL) w10: R501.2@6482.9,1564.1 R501.2@6485.1,1561.9
  L1-Top Layer (GTL) w15: v12(6447.4,1564.1) R501.2@6482.9,1564.1 ; R501.2@6485.1,1561.9 6516.93,1561.9 C511.1@6532.6,1577.58
  L1-Top Layer (GTL) w20: L500.2@6129.2,1328.63 6133.57,1333 v6(6179.4,1333)
  L1-Top Layer (GTL) w30: L503.1@5571.47,1947.3 5601.99,1916.79 v10(5601.99,1727.51)
  L1-Top Layer (GTL) w60: JP1.1@5408,878 5798.4,878 5935.9,1015.5 TP1.1@5992.6,1015.5 6059.69,1082.59 6059.69,1668.11 6022.6,1705.2 5823.58,1705.2 v10(5823.58,1705.8) ; 6060.79,1130 C510.1@6128.97,1130 ; C510.1@6129.2,1130.23 L500.2@6129.2,1317.2
  L8-Bottom Layer (GBL) w15: v6(6179.4,1333) 6179.4,1331.5 6191.5,1331.5 6272.4,1412.4 6385,1412.4 6417.6,1445 6417.6,1551.9 6428.37,1562.67 6445.97,1562.67 v12(6447.4,1564.1)
  L8-Bottom Layer (GBL) w60: v10(5601.99,1727.51) v10@5614,1715.5 ; 5623.7,1705.8 v10(5823.58,1705.8)
NetC511_2: C511.2 R501.1 R504.2 U500.9 | length 205
  L1-Top Layer (GTL) w10: U500.9@6393.92,1583.84 6423.68,1583.84 6464.74,1624.9 R501.1@6485.1,1624.9
  L1-Top Layer (GTL) w40: R501.1@6485.1,1624.9 R504.2@6581.9,1624.9
NetC512_1: C512.1 U500.8 | length 130.5
  L1-Top Layer (GTL) w10: U500.8@6393.92,1563.4 U500.8@6393.92,1564.16 6418.94,1564.16 6429.6,1553.5 6429.6,1530.3 6453.6,1506.3 C512.1@6486.1,1506.3
NetD3_1: D3.1 R13.2 | length 191.5
  L1-Top Layer (GTL) w11: R13.2@4485.65,1983.98 D3.1@4677.16,1983.98
NetD4_1: D4.1 R14.2 | length 192.8
  L1-Top Layer (GTL) w11: R14.2@4485.65,1909.24 D4.1@4678.48,1909.24
NetD5_1: D5.1 R15.2 | length 999
  L1-Top Layer (GTL) w11: R15.2@4362.77,2811.59 4366.09,2808.28 v3(4366.09,2750.4) ; v3(4418.9,2113.1) 4451.4,2113.1 4501.52,2062.98 D5.1@4675.34,2062.98
  L8-Bottom Layer (GBL) w11: v3@4365.9,2750.4 4365.9,2166.1 v3(4418.9,2113.1)
NetD6_1: D6.1 R54.1 | length 166.5
  L1-Top Layer (GTL) w11: R54.1@4484.86,1744.56 D6.1@4651.33,1744.56
NetD6_2: D6.2 Q2.3 | length 3322.3
  L1-Top Layer (GTL) w11: Q2.3@1952.65,2386.9 v3(1952.65,2423.2) ; v3(4544,1655.78) 4702.78,1655.78 4736.9,1689.9 D6.2@4736.9,1741.67
  L8-Bottom Layer (GBL) w11: v3(1952.65,2423.2) 1952.65,2456.65 2038,2542 2512,2542 3398.22,1655.78 v3(4544,1655.78)
NetD7_1: D7.1 R56.1 | length 81.7
  L1-Top Layer (GTL) w10: R56.1@3425.01,529.08 3431.34,522.75 D7.1@3431.34,450
NetD7_2: D7.2 Q1.3 | length 1026.1
  L1-Top Layer (GTL) w11: Q1.3@2406.08,385.25 2406.08,353.92 2421,339 3172,339 3283,450 D7.2@3348.66,450
NetD8_1: D8.1 U5.4 | length 157.7
  L1-Top Layer (GTL) w11: U5.4@1579.54,2349.5 1615.95,2349.5 1625.41,2358.96 1625.41,2406.9 1642.81,2424.3 D8.1@1678.17,2424.3
NetD9_1: D9.1 R67.1 | length 75.8
  L1-Top Layer (GTL) w11: R67.1@3425.01,1265.08 3431.85,1258.24 D9.1@3431.85,1192.08
NetD9_2: D9.2 Q3.3 | length 1024
  L1-Top Layer (GTL) w11: Q3.3@2406.09,1135.57 2406.09,1101.91 2418,1090 3180,1090 3282.08,1192.08 D9.2@3349.17,1192.08
NetD10_1: D10.1 R74.1 | length 83.8
  L1-Top Layer (GTL) w11: R74.1@3427.51,2059.81 3432.34,2054.98 D10.1@3432.34,1978
NetD10_2: D10.2 Q4.3 | length 1043.4
  L1-Top Layer (GTL) w11: Q4.3@2420.31,1871.56 2420.31,1837.69 2447,1811 3120,1811 3287,1978 D10.2@3349.66,1978
NetD12_1: D12.1 R166.1 | length 4048.8
  L1-Top Layer (GTL) w11: R166.1@2092.5,157 2092.5,224.5 2164,296 v3(4118,296) ; v3(4546,1847) 4583,1847 4601.15,1828.85 D12.1@4682.57,1828.85
  L8-Bottom Layer (GBL) w11: v3(4118,296) 4118,882 4611,1375 4611,1782 v3(4546,1847)
NetD12_2: D12.2 Q5.3 | length 3872.3
  L1-Top Layer (GTL) w10: Q5.3@2238.4,201.56 2375.56,201.56 2417,243 v3@4181,243 ; D12.2@4741.63,1828.85 v3(4809.15,1828.85)
  L8-Bottom Layer (GBL) w10: v3(4181,244) 4181,899 4809.15,1527.15 v3(4809.15,1828.85)
NetFB1_1: FB1.1 R11.1 | length 131.5
  L1-Top Layer (GTL) w20: FB1.1@3832.31,6486.34 3832.31,6537.7 ; 3832.36,6537.83 R11.1@3832.36,6618.01
NetFB2_1: FB2.1 R12.1 | length 113.9
  L1-Top Layer (GTL) w20: R12.1@2839.03,4844.49 2856.45,4861.91 2856.45,4872.69 FB2.1@2911.97,4928.21
NetFB3_1: FB3.1 R16.1 | length 119.8
  L1-Top Layer (GTL) w15: R16.1@3693.18,6526.9 3693.18,6498.19 3706.73,6484.64 FB3.1@3706.73,6412.68
NetFB4_1: FB4.1 R17.1 | length 125.3
  L1-Top Layer (GTL) w20: R17.1@3301.03,4454.67 3313.65,4467.29 FB4.1@3313.65,4573.78 FB4.1@3313.65,4574.78
NetFB5_1: FB5.1 R18.1 | length 142.9
  L1-Top Layer (GTL) w20: FB5.1@3489.58,6113.87 3489.58,6166.96 3489.58,6195.81 3511.08,6217.31 R18.1@3511.08,6247.83
NetFB6_1: FB6.1 R19.1 | length 730.2
  L1-Top Layer (GTL) w25: FB6.1@4185.81,5478.47 R19.1@4916,5478.47
NetFB7_1: FB7.1 R20.1 | length 148.7
  L1-Top Layer (GTL) w20: R20.1@3612.65,4561.77 3612.65,4599.65 3621.92,4608.92 3621.92,4656.73 FB7.1@3621.92,4706.65
NetFB8_1: FB8.1 R21.1 | length 124.7
  L1-Top Layer (GTL) w10: R21.1@2667.99,5573.42 R21.1@2673.02,5578.45
  L1-Top Layer (GTL) w20: R21.1@2670,5578.45 FB8.1@2787.53,5578.45
NetFB9_1: FB9.1 R22.1 | length 146.9
  L1-Top Layer (GTL) w20: FB9.1@4138.22,5238.51 4217.28,5238.51 4237.48,5218.31 4265.14,5218.31 R22.1@4273.34,5210.12
NetFB11_1: FB11.1 R25.1 | length 122.7
  L1-Top Layer (GTL) w11: R25.1@3149.57,6133.77 R25.1@3160.02,6144.22
  L1-Top Layer (GTL) w20: FB11.1@3149.57,6025.89 3149.57,6077.89 R25.1@3149.57,6133.77
NetJ41_2: J41.2 R144.2 U7.1 | length 232.3
  L1-Top Layer (GTL) w11: J41.2@308.36,761.5 310.17,759.69 U7.1@425.17,759.69 425.17,773.17 438,786 491.38,786 R144.2@512.38,765
NetJ41_3: J41.3 R146.2 U7.4 | length 232.9
  L1-Top Layer (GTL) w11: J41.3@308.36,730 366,730 396,700 441,700 447.81,706.81 U7.4@447.81,720.32 512.06,720.32 R146.2@512.38,720
NetJ41_6: J41.6 J41.7 J41.8 J41.9 R148.1 | length 895.6
  L1-Top Layer (GTL) w20: J41.9@304.43,905.2 J41.8@87.89,905.2 J41.7@87.89,554.8 J41.6@304.43,554.8 414.7,554.8 R148.1@416,553.5
NetJ42_15: J42.15 R212.1 | length 260.8
  L8-Bottom Layer (GBL) w11: R212.1@1554.5,1473 1554.5,1517.5 1629,1592 J42.15@1629,1702.96
NetL501_1: L501.1 U500.2 | length 133.2
  L1-Top Layer (GTL) w15: U500.2@6347.66,1601.56 L501.1@6347.66,1734.8
NetQ1_1: Q1.1 R55.2 | length 89.7
  L1-Top Layer (GTL) w11: Q1.1@2443.48,479.73 2464.27,479.73 2495,449 R55.2@2520.44,449
NetQ3_1: Q3.1 R66.2 | length 100.9
  L1-Top Layer (GTL) w11: Q3.1@2443.49,1230.06 2466.94,1230.06 2503,1194 R66.2@2529.44,1194
NetQ4_1: Q4.1 R73.2 | length 77.3
  L1-Top Layer (GTL) w11: Q4.1@2457.71,1966.04 2457.95,1965.8 R73.2@2534.93,1965.8
NetQ5_1: Q5.1 U8.15 | length 700.6
  L1-Top Layer (GTL) w10: U8.15@1761.29,377.09 1761.34,377.04 1761.34,122.66 1776.92,107.08 Q5.1@2201,107.08
NetR1_1: R1.1 R2.2 U10.8 | length 190.2
  L8-Bottom Layer (GBL) w10: U10.8@6000.47,1960.6 6000.47,1878.62 R1.1@6022.7,1856.4 6057.19,1890.9 R2.2@6085.2,1890.9
NetR1_2: R1.2 U10.9 | length 112.9
  L8-Bottom Layer (GBL) w10: R1.2@5959.7,1856.4 5980.79,1877.49 U10.9@5980.79,1960.6
NetR3_1: R3.1 R5.2 U11.8 | length 252.9
  L8-Bottom Layer (GBL) w10: U11.8@6317.4,1901.87 6300.67,1901.87 6288.2,1889.4 6288.2,1830.4 6302.2,1816.4 6342.7,1816.4 R3.1@6374.7,1784.4 R5.2@6374.7,1730.4
NetR3_2: R3.2 U11.9 | length 226.2
  L8-Bottom Layer (GBL) w10: R3.2@6311.7,1784.4 6276.2,1784.4 6250.2,1810.4 6250.2,1883.4 6296.32,1921.56 U11.9@6317.4,1921.56
NetR8_1: R8.1 R9.2 U9.8 | length 240.8
  L8-Bottom Layer (GBL) w8: R8.1@4924.5,2669 R9.2@4995.5,2669 4995.5,2690.5 4968,2718 4968,2789 4982.96,2803.96 U9.8@5000.26,2803.96
NetR8_2: R8.2 U9.9 | length 143.8
  L8-Bottom Layer (GBL) w8: R8.2@4924,2732.5 4924,2783.38 4964.27,2823.65 U9.9@5000.26,2823.65
NetR46_2: R46.2 Y2.3 | length 244.5
  L1-Top Layer (GTL) w10: R46.2@3760.85,3243.89 3760.85,3226.07 3781.92,3205 3880.46,3205 3928.88,3156.58 Y2.3@3928.88,3126.73
NetR47_2: R47.2 Y3.3 | length 149.5
  L1-Top Layer (GTL) w10: R47.2@3720.85,3324.78 3720.85,3358.85 3760.85,3398.85 Y3.3@3760.78,3457.73
NetR48_2: R48.2 Y4.3 | length 280.7
  L1-Top Layer (GTL) w10: R48.2@3631.08,3324.13 3631.08,3358.08 v7(3668,3395)
  L8-Bottom Layer (GBL) w10: v7(3668,3395) 3711.08,3438.08 3711.08,3454.86 Y4.3@3775.47,3519.25 Y4.3@3749.68,3519.25
NetR49_2: R49.2 Y5.4 | length 273.6
  L1-Top Layer (GTL) w10: R49.2@3592.08,3322.71 v15(3592.08,3352.39)
  L8-Bottom Layer (GBL) w10: v15(3592.08,3352.39) 3592.08,3322.71 3607.91,3306.88 Y5.4@3799.78,3306.88
NetR50_2: R50.2 U4.4 | length 271.6
  L1-Top Layer (GTL) w10: R50.2@3672.76,3244.22 3672.76,3227.36 3672.76,3225.24 3729,3169 3847,3169 3857.53,3158.47 U4.4@3857.53,3118.23
NetR51_2: R51.2 S1.1 | length 84.7
  L1-Top Layer (GTL) w11: R51.2@2586.51,748.55 S1.1@2671.2,748.55
NetR52_2: R52.2 S1.2 | length 84.7
  L1-Top Layer (GTL) w11: R52.2@2586.51,648.55 S1.2@2671.2,648.55
NetR53_2: R53.2 S1.3 | length 84.7
  L1-Top Layer (GTL) w11: R53.2@2586.51,548.55 S1.3@2671.2,548.55
NetR55_1: R55.1 S1.4 | length 98.8
  L1-Top Layer (GTL) w11: R55.1@2572.36,448.55 S1.4@2671.2,448.55
NetR63_2: R63.2 S2.1 | length 84.7
  L1-Top Layer (GTL) w11: R63.2@2587.11,1497.55 S2.1@2671.8,1497.55
NetR64_2: R64.2 S2.2 | length 84.7
  L1-Top Layer (GTL) w11: R64.2@2587.11,1397.55 S2.2@2671.8,1397.55
NetR65_2: R65.2 S2.3 | length 84.7
  L1-Top Layer (GTL) w11: R65.2@2587.11,1297.55 S2.3@2671.8,1297.55
NetR66_1: R66.1 S2.4 | length 96.5
  L1-Top Layer (GTL) w11: R66.1@2575.33,1197.55 S2.4@2671.8,1197.55
NetR68_2: R68.2 S3.4 | length 102.5
  L1-Top Layer (GTL) w11: S3.4@2131.76,2429.2 R68.2@2131.76,2531.71
NetR69_2: R69.2 S3.3 | length 102.5
  L1-Top Layer (GTL) w11: S3.3@2231.76,2429.2 R69.2@2231.76,2531.71
NetR70_2: R70.2 S4.1 | length 84.7
  L1-Top Layer (GTL) w11: R70.2@2584.7,2266.55 2585.94,2266.55 S4.1@2669.39,2266.55
NetR71_1: R71.1 S4.2 | length 84.7
  L1-Top Layer (GTL) w11: R71.1@2584.7,2166.55 S4.2@2669.39,2166.55
NetR72_2: R72.2 S4.3 | length 84.7
  L1-Top Layer (GTL) w11: R72.2@2584.7,2066.55 S4.3@2669.39,2066.55
NetR73_1: R73.1 S4.4 | length 102.5
  L1-Top Layer (GTL) w11: R73.1@2587.7,1966.55 S4.4@2669.39,1966.55 S4.4@2690.2,1966.55
NetR77_2: R77.2 S5.1 S5.2 | length 504.1
  L1-Top Layer (GTL) w11: R77.2@337.14,1842.72 R77.2@338.64,1844.22 ; R77.2@337.14,1844.22 R77.2@338.64,1844.22 ; S5.2@836.02,1836.72 S5.1@477.76,1836.72 470.26,1844.22 R77.2@338.64,1844.22
NetR150_1: R150.1 U8.21 | length 95
  L1-Top Layer (GTL) w12: U8.21@1937.47,454.84 2028.22,454.84 R150.1@2031.21,451.85
NetR151_1: R151.1 U8.29 | length 93.9
  L1-Top Layer (GTL) w12: U8.29@1937.47,612.32 2030.74,612.32 R151.1@2031.21,611.85
NetR152_1: R152.1 U8.23 | length 94.8
  L1-Top Layer (GTL) w12: U8.23@1937.47,494.21 2028.58,494.21 R152.1@2031.21,496.85
NetR153_1: R153.1 U8.33 | length 93
  L1-Top Layer (GTL) w12: U8.33@1937.47,691.06 R153.1@2030.43,691.06
NetR154_1: R154.1 U8.45 | length 157.7
  L1-Top Layer (GTL) w12: U8.45@1780.98,906.61 1780.98,942.96 1801.29,963.27 1839.13,963.27 1857.71,981.85 R154.1@1857.71,1010.35
NetR155_2: R155.2 U8.46 | length 120.9
  L1-Top Layer (GTL) w12: U8.46@1761.29,906.61 1761.29,960.43 1802.71,1001.85 R155.2@1802.71,1010.35
NetR156_2: R156.2 U8.47 | length 104.2
  L1-Top Layer (GTL) w12: U8.47@1741.61,906.61 1741.61,1009.25 R156.2@1742.71,1010.35
NetR157_1: R157.1 U8.51 | length 122.4
  L1-Top Layer (GTL) w11: R157.1@1617.71,1010.35 1630.98,997.08 1630.98,983.58 1644.25,970.31 1644.25,970.05 1662.87,951.43 U8.51@1662.87,906.61
NetR158_1: R158.1 U8.52 | length 165.5
  L1-Top Layer (GTL) w11: R158.1@1557.71,1010.35 1557.71,981.85 1582.71,956.85 1627.71,956.85 1643.18,941.38 U8.52@1643.18,906.61
NetR159_1: R159.1 U8.9 | length 156.4
  L1-Top Layer (GTL) w10: R159.1@1567.71,278.35 1567.71,301.85 1577.71,311.85 1622.71,311.85 1643.18,332.32 U8.9@1643.18,377.09
NetR160_1: R160.1 U8.10 | length 113.3
  L1-Top Layer (GTL) w10: R160.1@1627.71,278.35 1662.87,313.5 U8.10@1662.87,377.09
NetR163_1: R163.1 U8.3 | length 143.4
  L1-Top Layer (GTL) w10: R163.1@1447.71,278.35 1486.21,316.85 1507.71,316.85 1525.07,334.21 U8.3@1525.07,377.09
NetR164_1: R164.1 U8.4 | length 114.1
  L1-Top Layer (GTL) w10: R164.1@1507.71,278.35 1544.76,315.39 U8.4@1544.76,377.09
NetR206_2: R206.2 Y1.9 | length 108.4
  L1-Top Layer (GTL) w20: Y1.9@4196.72,3282.66 R206.2@4305.16,3282.66
NetR500_1: R500.1 R502.2 U500.10 | length 733.1
  L1-Top Layer (GTL) w10: U500.10@6393.92,1603.53 6419.33,1603.53 6429.6,1613.8 6429.6,1662.3 6448.1,1680.8 R502.2@6516.5,1680.8
  L1-Top Layer (GTL) w15: R502.2@6516.5,1680.8 6516.5,1710.3 6543.1,1736.9 6635.9,1736.9 6658.1,1714.7 6658.1,1527.1 6604.4,1473.4 6604.4,1440.5 6591,1427.1 R500.1@6547.6,1427.1
OUT0_A_N: R10.2 R128.1 R169.1 | length 4396.6
  L1-Top Layer (GTL) w11: 384,3612.5 515.5,3612.5 743.5,3840.5 831.75,3840.5 860,3840.5 923.67,3840.5 ccw(c923.67,3916.75) 999.92,3916.75 999.92,4059.8 cw(c1032.17,4059.8) 1032.17,4092.05 1078.67,4092.05 cw(c1078.67,4059.8) 1110.92,4059.8 1110.92,3665.2 ccw(c1187.17,3665.2) 1187.17,3588.95 1233.67,3588.95 ccw(c1233.67,3665.2) 1309.92,3665.2 1309.92,3808.25 cw(c1342.17,3808.25) 1342.17,3840.5 1857,3840.5 2604.76,4588.25 2772.27,4588.25 3244.86,5060.14 3246.14,5060.14 R10.2@3294.08,5109.08
OUT0_A_P: R6.2 R132.1 R167.1 | length 4410
  L1-Top Layer (GTL) w11: R132.1@370.68,4112.5 577.82,4145.61 743.5,3884.5 860,3884.5 923.67,3884.5 ccw(c923.67,3916.75) 955.92,3916.75 955.92,4059.8 cw(c1032.17,4059.8) 1032.17,4136.05 1078.67,4136.05 cw(c1078.67,4059.8) 1154.92,4059.8 1154.92,3665.2 ccw(c1187.17,3665.2) 1187.17,3632.95 1233.67,3632.95 ccw(c1233.67,3665.2) 1265.92,3665.2 1265.92,3808.25 cw(c1342.17,3808.25) 1342.17,3884.5 1838.78,3884.5 2586.53,4632.25 2754.05,4632.25 3213.14,5090.86 3252.08,5129.8 R6.2@3252.08,5130.08
OUT0_N: R10.1 U1.3 | length 158
  L1-Top Layer (GTL) w9: R10.1@3321.92,5136.92 3355.7,5170.7 3355.7,5187.7 3374.88,5206.88 ; 3374.88,5207.51 U1.3@3374.88,5273.62
OUT0_P: R6.1 U1.2 | length 158
  L1-Top Layer (GTL) w9: R6.1@3279.92,5157.92 3323,5201 3342,5201 3355.2,5214.2 U1.2@3355.2,5273.62
OUT1_A_N: C100.2 R80.2 R170.1 | length 4274.6
  L1-Top Layer (GTL) w11: C100.2@381,3112.5 515.5,3112.5 565,3063 571.47,3056.53 ccw(c586.57,3071.63) 601.66,3056.53 603.85,3058.72 cw(c618.95,3043.62) 634.05,3058.72 646.99,3045.78 cw(c631.89,3030.68) 646.99,3015.59 644.8,3013.4 ccw(c659.89,2998.3) 644.8,2983.2 649,2979 743.5,2884.5 854.75,2884.5 1176.1,2884.5 1243.24,2951.64 ; 1243.08,2951.82 1279.03,2987.76 ccw(c1256.25,3010.56) 1288.48,3010.56 ccw(c1256.25,3010.56) 1279.05,3033.34 1203.97,3108.45 cw(c1257.99,3162.44) 1204,3216.45 1236.92,3249.35 cw(c1290.91,3195.34) 1344.92,3249.33 1419.99,3174.22 ccw(c1442.79,3197) 1465.57,3174.2 3245.14,4952.86 R80.2@3293.36,5001.08
OUT1_A_P: C98.2 R7.2 R168.1 | length 4271.7
  L1-Top Layer (GTL) w11: 384,2612.5 515.5,2612.5 743.5,2840.5 854.75,2840.5 1194.33,2840.5 1274.35,2920.53 ; 1274.28,2920.6 1310.24,2956.54 ccw(c1256.25,3010.56) 1332.62,3010.56 ccw(c1256.25,3010.56) 1310.26,3064.54 1235.19,3139.65 cw(c1257.99,3162.44) 1235.2,3185.23 1268.12,3218.13 cw(c1290.91,3195.34) 1313.7,3218.12 1388.77,3143.01 ccw(c1442.79,3197) 1496.78,3142.98 3292.86,4938.14 R7.2@3337.72,4983
OUT1_N: R80.1 U1.4 | length 283.1
  L1-Top Layer (GTL) w11: R80.1@3320.92,5028.92 3360,5067 3373.02,5067 3394.57,5088.55 3394.57,5178.7 U1.4@3394.57,5273.62
OUT1_P: R7.1 U1.5 | length 282.7
  L1-Top Layer (GTL) w11: R7.1@3365.92,5010.92 3390.5,5035.5 3390.5,5038.48 3390.5,5051.5 3414.25,5075.25 3414.25,5080.4 3414.25,5186.85 U1.5@3414.25,5273.62
OUT2_A_N: C103.2 R84.2 R173.1 | length 4295.3
  L1-Top Layer (GTL) w11: R84.2@3748.92,5066.08 3771,5044 3771,5034 3806.77,4997.04 3810,4993.81 3810,4980.3 3810,4948.7 ; R173.1@3809.71,4914.64 3809.71,4767.52 5692.73,2884.5 5823.25,2884.5 ccw(c5823.25,2916.75) 5855.5,2916.75 5855.5,2975.42 cw(c5931.75,2975.42) 5931.75,3051.67 5978.25,3051.67 cw(c5978.25,2975.42) 6054.5,2975.42 6054.5,2916.75 ccw(c6086.75,2916.75) 6086.75,2884.5 6259.5,2884.5 6318.5,2943.5 6408.72,3033.71 cw(c6414.51,3027.91) 6420.31,3033.71 6432.34,3021.69 ccw(c6438.14,3027.48) 6443.94,3021.69 6461.33,3039.08 ccw(c6455.53,3044.88) 6461.33,3050.68 6449.3,3062.7 cw(c6455.1,3068.5) 6449.3,3074.3 6458,3083 6487.5,3112.5 6614,3112.5 ; R173.1@3809.86,4914.64 3810,4914.77 3810,4947.72
OUT2_A_P: C101.2 R81.2 R171.1 | length 4297.3
  L1-Top Layer (GTL) w11: R81.2@3705.66,5042.34 3733,5015 3741,5015 3766,4990 3765.91,4914.81 3765.71,4749.29 5674.51,2840.5 5823.25,2840.5 ccw(c5823.25,2916.75) 5899.5,2916.75 5899.5,2975.42 cw(c5931.75,2975.42) 5931.75,3007.67 5978.25,3007.67 cw(c5978.25,2975.42) 6010.5,2975.42 6010.5,2916.75 ccw(c6086.75,2916.75) 6086.75,2840.5 6184.5,2840.5 6259.5,2840.5 6487.5,2612.5 6614,2612.5
OUT2_N: R84.1 U1.13 | length 255.4
  L1-Top Layer (GTL) w8: U1.13@3571.73,5273.62 3571.73,5257.81 3569.94,5256.02 3569.94,5234.69 3649.5,5155.13 3649.5,5143.13 3678.53,5114.1 3700.9,5114.1 ; 3700.81,5114.19 R84.1@3720.49,5094.51
OUT2_P: R81.1 U1.12 | length 255.4
  L1-Top Layer (GTL) w8: U1.12@3552.05,5273.62 3552.05,5255.56 3553.94,5253.66 3553.94,5228.06 3633.5,5148.5 3633.5,5136.59 ; 3633.5,5136.5 3666.64,5103.36 3666.64,5081.36 R81.1@3677.82,5070.18
OUT3_A_N: C104.2 R87.2 R174.1 | length 5950.6
  L1-Top Layer (GTL) w11: R87.2@3782.92,5086.08 R174.1@3865.22,5003.72 ; C104.2@6625.37,3612.5 6482.5,3612.5 6254.5,3840.5 6133.75,3840.5 ccw(c6133.75,3808.25) 6101.5,3808.25 6101.5,3668.58 cw(c6025.25,3668.58) 6025.25,3592.33 5978.75,3592.33 cw(c5978.75,3668.58) 5902.5,3668.58 5902.5,4056.42 ccw(c5870.25,4056.42) 5870.25,4088.67 5823.75,4088.67 ccw(c5823.75,4056.42) 5791.5,4056.42 5791.5,3916.75 cw(c5715.25,3916.75) 5715.25,3840.5 5027.68,3840.5 ; R174.1@3865.22,5003.72 5027.68,3840.5 ; R174.1@3865.22,5003.72 5027.68,3840.5
OUT3_A_P: C102.2 R83.2 R172.1 | length 4306.1
  L1-Top Layer (GTL) w11: R83.2@3822.62,5105 3895.77,5034.25 5045.91,3884.5 5715.25,3884.5 ccw(c5715.25,3916.75) 5747.5,3916.75 5747.5,4056.42 cw(c5823.75,4056.42) 5823.75,4132.67 5870.25,4132.67 cw(c5870.25,4056.42) 5946.5,4056.42 5946.5,3668.58 ccw(c5978.75,3668.58) 5978.75,3636.33 6025.25,3636.33 ccw(c6025.25,3668.58) 6057.5,3668.58 6057.5,3808.25 cw(c6133.75,3808.25) 6133.75,3884.5 6254.5,3884.5 6364,3994 6364,4049 6448,4133 6543.5,4133 6564,4112.5 C102.2@6627.31,4112.5
OUT3_N: R87.1 U1.14 | length 257.7
  L1-Top Layer (GTL) w8: U1.14@3591.42,5273.62 3591.42,5257.81 3593.26,5255.97 3593.26,5242.9 ; 3593.26,5242.79 3661.14,5174.91 3713.07,5174.91 3728.98,5159.02 3728.98,5140.02 R87.1@3755,5114
OUT3_P: R83.1 U1.15 | length 257.7
  L1-Top Layer (GTL) w8: U1.15@3611.1,5273.62 3611.1,5257.81 3609.26,5255.97 3609.26,5249.42 3667.77,5190.91 3719.7,5190.91 3740.59,5170 3761,5170 R83.1@3795,5136
OUT4_A_N: C107.2 R93.2 R204.1 | length 4320.7
  L1-Top Layer (GTL) w11: R93.2@3866.91,5464.22 v11(3902.84,5464.22) 3931,5464.99 R204.1@3931.31,5465 ; v6(6560.67,5612.5) C107.2@6617,5612.5
  L6-Mid-Layer 5 (G4) w5: v11(3902.84,5464.22) 4644.45,5464.22 5020.73,5840.5 5541.35,5840.5 cw(c5541.35,5810.35) 5571.5,5810.35 5571.5,5669.5 ccw(c5645.65,5669.5) 5645.65,5595.35 5690.35,5595.35 ccw(c5690.35,5669.5) 5764.5,5669.5 5764.5,6055.5 cw(c5794.65,6055.5) 5794.65,6085.65 5839.35,6085.65 cw(c5839.35,6055.5) 5869.5,6055.5 5869.5,5669.5 ccw(c5943.65,5669.5) 5943.65,5595.35 5988.35,5595.35 ccw(c5988.35,5669.5) 6062.5,5669.5 6062.5,5810.35 cw(c6092.65,5810.35) 6092.65,5840.5 6200,5840.5 6254.5,5840.5 6482.5,5612.5 v6(6560.67,5612.5)
OUT4_A_P: C105.2 R89.2 R176.1 | length 4320.7
  L1-Top Layer (GTL) w11: R89.2@3867.91,5508.22 v11(3902.84,5508.22) 3932,5508 R176.1@3932.31,5508 ; v6(6560.67,6112.5) C105.2@6617,6112.5
  L6-Mid-Layer 5 (G4) w5: v11(3902.84,5508.22) 4626.22,5508.22 5002.5,5884.5 5541.35,5884.5 cw(c5541.35,5810.35) 5615.5,5810.35 5615.5,5669.5 ccw(c5645.65,5669.5) 5645.65,5639.35 5690.35,5639.35 ccw(c5690.35,5669.5) 5720.5,5669.5 5720.5,6055.5 cw(c5794.65,6055.5) 5794.65,6129.65 5839.35,6129.65 cw(c5839.35,6055.5) 5913.5,6055.5 5913.5,5669.5 ccw(c5943.65,5669.5) 5943.65,5639.35 5988.35,5639.35 ccw(c5988.35,5669.5) 6018.5,5669.5 6018.5,5810.35 cw(c6092.65,5810.35) 6092.65,5884.5 6200,5884.5 6254.5,5884.5 6482.5,6112.5 v6(6560.67,6112.5)
OUT4_N: R93.1 U1.26 | length 178.3
  L1-Top Layer (GTL) w8: U1.26@3656.38,5476.38 3672.19,5476.38 3674.03,5478.22 3815.21,5478.22 ; 3815.09,5478.22 R93.1@3828.31,5465
OUT4_P: R89.1 U1.27 | length 178.3
  L1-Top Layer (GTL) w8: U1.27@3656.38,5496.06 3672.19,5496.06 3674.03,5494.22 3814.42,5494.22 ; 3814.54,5494.22 R89.1@3828.31,5508
OUT5_A_N: C108.2 R95.2 R177.1 | length 4207.6
  L1-Top Layer (GTL) w8: R95.2@3941.92,5361.08 3991.26,5361.08 v11(3998.89,5353.45)
  L1-Top Layer (GTL) w11: v11(3998.89,5353.45) R177.1@4022.45,5353.45 ; v6(6560.67,5112.5) C108.2@6617,5112.5
  L6-Mid-Layer 5 (G4) w5: v11@3998.89,5353.45 4490.55,5353.45 4795.89,5048.11 4959.5,4884.5 5556.35,4884.5 cw(c5556.35,4810.35) 5630.5,4810.35 5630.5,4684.9 ccw(c5660.65,4684.9) 5660.65,4654.75 5705.35,4654.75 ccw(c5705.35,4684.9) 5735.5,4684.9 5735.5,5040.1 cw(c5809.65,5040.1) 5809.65,5114.25 5854.35,5114.25 cw(c5854.35,5040.1) 5928.5,5040.1 5928.5,4684.9 ccw(c5958.65,4684.9) 5958.65,4654.75 6003.35,4654.75 ccw(c6003.35,4684.9) 6033.5,4684.9 6033.5,4810.35 cw(c6107.65,4810.35) 6107.65,4884.5 6155.65,4884.5 6254.5,4884.5 6295.27,4977.27 6416.05,5098.05 6482.5,5112.5 v6(6560.67,5112.5)
OUT5_A_P: C106.2 R91.2 R175.1 | length 4212.3
  L1-Top Layer (GTL) w8: R91.2@3926.55,5323.45 3984.89,5323.45 v11(3998.89,5309.45)
  L1-Top Layer (GTL) w11: v11(3998.89,5309.45) R175.1@4022.45,5309.45 ; v6(6560.67,4612.5) C106.2@6617,4612.5
  L6-Mid-Layer 5 (G4) w5: v11(3998.89,5309.45) 4472.32,5309.45 4764.78,5017 4941.28,4840.5 5556.35,4840.5 cw(c5556.35,4810.35) 5586.5,4810.35 5586.5,4684.9 ccw(c5660.65,4684.9) 5660.65,4610.75 5705.35,4610.75 ccw(c5705.35,4684.9) 5779.5,4684.9 5779.5,5040.1 cw(c5809.65,5040.1) 5809.65,5070.25 5854.35,5070.25 cw(c5854.35,5040.1) 5884.5,5040.1 5884.5,4684.9 ccw(c5958.65,4684.9) 5958.65,4610.75 6003.35,4610.75 ccw(c6003.35,4684.9) 6077.5,4684.9 6077.5,4810.35 cw(c6107.65,4810.35) 6107.65,4840.5 6160,4840.5 ; 6155.65,4840.5 6254.5,4840.5 6482.5,4612.5 v6(6560.67,4612.5)
OUT5_N: R95.1 U1.25 | length 284.8
  L1-Top Layer (GTL) w8: U1.25@3656.38,5456.69 3725.27,5456.69 3746.96,5435 3851.63,5435 3880.41,5406.22 3895.83,5406.22 ; 3896.83,5406.17 R95.1@3914.08,5388.92
OUT5_P: R91.1 U1.24 | length 284.8
  L1-Top Layer (GTL) w8: U1.24@3656.38,5437.01 3722.33,5437.01 3740.33,5419 3844.94,5419 ; 3845,5419 3865,5399 3865,5386 R91.1@3898.05,5351.95
OUT6_A_N: C111.2 R100.2 R205.1 | length 4304.4
  L1-Top Layer (GTL) w11: R100.2@3899.69,5659 4168,5659.74 4559.59,5660.82 5242.04,6343.26 cw(c5295.95,6289.34) 5349.87,6343.26 5411.63,6281.5 ccw(c5434.43,6304.31) 5457.23,6281.51 5490.11,6314.39 ccw(c5467.31,6337.19) 5499.56,6337.19 ccw(c5467.31,6337.19) 5490.11,6359.99 5289.88,6560.23 cw(c5343.8,6614.14) 5289.88,6668.06 5322.76,6700.94 cw(c5376.68,6647.02) 5430.6,6700.94 5630.83,6500.71 ccw(c5653.63,6523.51) 5676.44,6500.71 5709.32,6533.59 ccw(c5686.51,6556.39) 5718.76,6556.39 ccw(c5686.51,6556.39) 5709.32,6579.2 5647.56,6640.95 cw(c5701.48,6694.87) 5647.56,6748.79 5683.45,6784.67 5783.27,6884.5 6170.5,6884.5 6254.5,6884.5 6482.5,7112.5 6614,7112.5
OUT6_A_P: C109.2 R97.2 R179.1 | length 4318.4
  L1-Top Layer (GTL) w11: R97.2@3899.69,5617 4577.82,5616.82 5273.15,6312.15 cw(c5295.95,6289.34) 5318.76,6312.15 5380.51,6250.39 ccw(c5434.43,6304.31) 5488.35,6250.39 5521.23,6283.27 ccw(c5467.31,6337.19) 5543.56,6337.19 ccw(c5467.31,6337.19) 5521.23,6391.11 5320.99,6591.34 cw(c5343.8,6614.14) 5320.99,6636.95 5353.87,6669.83 cw(c5376.68,6647.02) 5399.48,6669.83 5599.72,6469.6 ccw(c5653.63,6523.51) 5707.55,6469.6 5740.43,6502.48 ccw(c5686.51,6556.39) 5762.76,6556.39 ccw(c5686.51,6556.39) 5740.43,6610.31 5678.67,6672.07 cw(c5701.48,6694.87) 5678.67,6717.67 5714.56,6753.56 5801.5,6840.5 6170.5,6840.5 6254.5,6840.5 6480.3,6612.4 C109.2@6627.31,6612.5
OUT6_N: R100.1 U1.30 | length 248.1
  L1-Top Layer (GTL) w8: U1.30@3656.38,5555.12 3672.19,5555.12 3674.03,5553.28 3705.28,5553.28 3799.69,5647.69 3826.69,5647.69 3838,5659 R100.1@3859.9,5659
OUT6_P: R97.1 U1.29 | length 248.1
  L1-Top Layer (GTL) w8: U1.29@3656.38,5535.43 3672.19,5535.43 3674.03,5537.28 3711.9,5537.28 3803.63,5629 3826,5629 3838,5617 R97.1@3860.73,5617
OUT7_A_N: C112.2 R102.2 R180.1 | length 4183.4
  L1-Top Layer (GTL) w11: R102.2@3983.69,5743.73 4032,5743.73 4102.73,5743.73 5876.87,7517.87 cw(c5899.67,7495.06) 5922.48,7517.87 6087.31,7353.03 ccw(c6141.23,7406.95) 6195.14,7353.03 6228.02,7385.91 ccw(c6174.11,7439.83) 6250.36,7439.83 ccw(c6174.11,7439.83) 6228.02,7493.75 6063.19,7658.58 cw(c6085.99,7681.39) 6063.19,7704.19 6099.08,7740.08 6199.5,7840.5 6254.5,7840.5 6482.5,7612.5 6614,7612.5
OUT7_A_P: C110.2 R98.2 R178.1 | length 4178.7
  L1-Top Layer (GTL) w11: R98.2@3983.69,5789 R178.1@4027.35,5789 ; R178.1@4032,5789 4085.77,5789 5845.75,7548.98 cw(c5899.67,7495.06) 5953.59,7548.98 6118.42,7384.14 ccw(c6141.23,7406.95) 6164.03,7384.14 6196.91,7417.03 ccw(c6174.11,7439.83) 6206.36,7439.83 ccw(c6174.11,7439.83) 6196.91,7462.63 6032.08,7627.47 cw(c6085.99,7681.39) 6032.08,7735.3 6067.96,7771.19 6181.28,7884.5 6254.5,7884.5 6481.7,8112.9 6614,8112.5
OUT7_N: R102.1 U1.31 | length 369.5
  L1-Top Layer (GTL) w8: U1.31@3656.38,5574.8 3672.19,5574.8 3674.03,5576.65 3690.79,5576.65 3871.87,5757.73 3902.64,5757.73 3916.64,5743.73
  L1-Top Layer (GTL) w11: 3916.64,5743.73 R102.1@3944.31,5743.73
OUT7_P: R98.1 U1.32 | length 369.5
  L1-Top Layer (GTL) w8: U1.32@3656.38,5594.49 3672.19,5594.49 3674.03,5592.65 3684.16,5592.65 3865.24,5773.73 3902.64,5773.73 3916.64,5787.73
  L1-Top Layer (GTL) w11: 3916.64,5787.73 R98.1@3944.31,5787.73
OUT8_A_N: C115.2 R107.2 R183.1 | length 4295.1
  L1-Top Layer (GTL) w8: v11(3000.79,5708.54) 3001.03,5708.78 3021.72,5708.78 3074.4,5656.1 3092.9,5656.1 3093.1,5655.9 3096.45,5655.9 3108.35,5644 R107.2@3110.31,5644 R107.2@3112.31,5644
  L1-Top Layer (GTL) w11: v6(1747.5,8723.67) C115.2@1747.5,8780 ; R183.1@2984.13,5725.2 v11(3000.79,5708.54)
  L6-Mid-Layer 5 (G4) w5: v6(1747.5,8723.67) 1747.5,8645.5 1975.5,8417.5 1975.5,8248.4 ; 1975.5,8295.25 1975.5,8248.4 ; v11(3000.79,5708.54) 2521,6188.33 2521,6942 1975.5,7487.5 1975.5,7995.1 ccw(c1945.35,7995.1) 1945.35,8025.25 1757.05,8025.25 cw(c1757.05,8099.4) 1682.91,8099.4 1682.91,8144.1 cw(c1757.05,8144.1) 1757.05,8218.25 1945.35,8218.25 ccw(c1945.35,8248.4) 1975.5,8248.4
OUT8_A_P: C113.2 R104.2 R181.1 | length 4248.1
  L1-Top Layer (GTL) w8: v11(3031.9,5739.65) 3031.9,5719.85 3077.8,5673.96 3088,5673.96 3094.04,5680 R104.2@3111.31,5680
  L1-Top Layer (GTL) w11: v6(2247.5,8723.67) C113.2@2247.5,8780 ; R181.1@3015.24,5756.31 v11(3031.9,5739.65)
  L6-Mid-Layer 5 (G4) w5: v6(2247.5,8723.67) 2247.5,8640 2190,8588 2184.16,8582.17 ccw(c2197.78,8568.56) 2184.16,8554.94 2187.1,8552.01 cw(c2173.49,8538.4) 2187.1,8524.78 2175.43,8513.12 cw(c2161.82,8526.73) 2148.21,8513.12 2145.27,8516.05 ccw(c2131.66,8502.44) 2118.05,8516.05 2108.5,8506.5 2054.15,8452.15 2019.5,8417.5 2019.5,8329.65 2019.5,8295.25 2019.5,8248.4 cw(c1945.35,8248.4) 1945.35,8174.25 1757.05,8174.25 ccw(c1757.05,8144.1) 1726.9,8144.1 1726.9,8099.4 ccw(c1757.05,8099.4) 1757.05,8069.25 1945.35,8069.25 cw(c1945.35,7995.1) 2019.5,7995.1 2019.5,7505.73 2565,6960.22 2565,6206.55 v11(3031.9,5739.65)
OUT8_N: R107.1 U1.52 | length 246.9
  L1-Top Layer (GTL) w8: R107.1@3152.68,5644 3167,5644 3176.39,5654.39 3191.61,5654.39 3205,5640 3205,5579.37 3248.94,5535.43 U1.52@3309.92,5535.43
OUT8_P: R104.1 U1.51 | length 246.9
  L1-Top Layer (GTL) w8: R104.1@3151.11,5680 3167.5,5680 3174.5,5671 3197,5671 3221,5647 3221,5586 3251.88,5555.12 U1.51@3309.92,5555.12
OUT9_A_N: C116.2 R108.2 R184.1 | length 4229.9
  L1-Top Layer (GTL) w8: v11(2915.75,5684.8) 2915.75,5665 2983.75,5597 ; 2983.96,5597 3016,5597 3028,5609 R108.2@3045.31,5609
  L1-Top Layer (GTL) w11: v6(1247.5,8723.67) C116.2@1247.5,8780 ; R184.1@2899.09,5701.46 v11(2915.75,5684.8)
  L6-Mid-Layer 5 (G4) w5: v6(1247.5,8723.67) 1247.5,8645.5 1148.5,8546.5 1144.79,8542.79 ccw(c1153.45,8534.13) 1144.79,8525.47 1152.2,8518.06 cw(c1143.53,8509.39) 1152.2,8500.73 1144.77,8493.31 cw(c1136.11,8501.97) 1127.45,8493.31 1120.04,8500.72 ccw(c1111.38,8492.05) 1102.71,8500.72 1098.5,8496.5 1019.5,8417.5 1019.5,8098.73 2180,6938.22 2180,6420.55 v11(2915.75,5684.8)
OUT9_A_P: C114.2 R106.2 R182.1 | length 4230.7
  L1-Top Layer (GTL) w8: v11(2884.64,5653.69) 2904.44,5653.69 2977.12,5581 3016.21,5581 ; 3016,5581 3027,5570 R106.2@3045.31,5570
  L1-Top Layer (GTL) w11: v6(747.5,8723.67) C114.2@747.5,8780 ; R182.1@2867.98,5670.35 v11(2884.64,5653.69)
  L6-Mid-Layer 5 (G4) w5: v6(747.5,8723.67) 747.5,8645.5 975.5,8417.5 975.5,8080.5 2136,6920 2136,6402.32 v11(2884.64,5653.69)
OUT9_N: R108.1 U1.53 | length 265.4
  L1-Top Layer (GTL) w8: R108.1@3084.68,5609 3099,5609 3111,5597 3152.63,5597 3235.72,5513.91 3292.27,5513.91 3294.11,5515.75 U1.53@3309.92,5515.75
OUT9_P: R106.1 U1.54 | length 265.4
  L1-Top Layer (GTL) w8: R106.1@3084.27,5570 3100,5570 3111,5581 3146,5581 3229.09,5497.91 3292.27,5497.91 3294.11,5496.06 U1.54@3309.92,5496.06
OUT10_A_N: C119.2 R114.2 R187.1 | length 4386.4
  L1-Top Layer (GTL) w8: 2913.39,5424.85 2927.39,5434.85 2927.43,5434.8 3020.8,5434.8 R187.1@3021,5435 3066,5435 3073,5428 R114.2@3106.31,5428 ; R114.2@3106,5427.69 R114.2@3106.31,5428 ; R114.2@3106.91,5428 R114.2@3106.31,5428
  L1-Top Layer (GTL) w11: 384,7612.5 515.5,7612.5 735.5,7840.5 841.28,7840.5 918.91,7762.86 982.32,7699.45 982.32,7673.84 966.7,7658.22 966.7,7595.3 1044.5,7517.5 1107.42,7517.5 1123.04,7533.12 1148.65,7533.12 1913,6768.77 1913,5977.77 2465.92,5424.85 2913.39,5424.85
OUT10_A_P: C117.2 R110.2 R185.1 | length 4383.7
  L1-Top Layer (GTL) w8: 2913.39,5468.85 2927.39,5456.85 2991.21,5457 2991.72,5457.51 3064.49,5457.51 3065,5457 3075,5467 R110.2@3104.72,5467
  L1-Top Layer (GTL) w11: 384,8112.5 515.5,8112.5 743.5,7884.5 859.5,7884.5 950.02,7793.98 1026.32,7717.68 1026.32,7655.61 1010.7,7639.99 1010.7,7614.38 1063.58,7561.5 1089.19,7561.5 1104.81,7577.12 1166.88,7577.12 1957,6787 1957,5996 2484.15,5468.85 2913.39,5468.85
OUT10_N: R114.1 U1.57 | length 170.2
  L1-Top Layer (GTL) w8: R114.1@3144.98,5428 3163.15,5428 3174,5438.85 3292.27,5438.85 3294.11,5437.01 U1.57@3309.92,5437.01
OUT10_P: R110.1 U1.56 | length 170.2
  L1-Top Layer (GTL) w8: R110.1@3145.51,5467 3161.85,5467 3174,5454.85 3292.27,5454.85 3294.11,5456.69 U1.56@3309.92,5456.69
OUT11_A_N: C120.2 R116.2 R188.1 | length 4283.9
  L1-Top Layer (GTL) w11: 384,7112.5 515.5,7112.5 743.5,6884.5 870.5,6884.5 965.14,6789.86 ; 965,6790 1000.89,6754.11 ccw(c1023.69,6776.92) 1046.49,6754.11 1155.23,6862.85 cw(c1209.15,6808.94) 1263.07,6862.85 1295.95,6829.97 cw(c1242.03,6776.06) 1318.28,6776.06 cw(c1242.03,6776.06) 1295.95,6722.14 1001.75,6427.94 ccw(c1024.55,6405.14) 1001.75,6382.33 1034.63,6349.45 ccw(c1057.43,6372.26) 1080.24,6349.45 1188.98,6458.19 cw(c1242.89,6404.27) 1296.81,6458.19 2392.51,5362.49 2893.27,5362.49 2994,5362.49 2997.49,5359 R116.2@3032,5359
OUT11_A_P: C118.2 R112.2 R186.1 | length 4283.9
  L1-Top Layer (GTL) w11: 384,6612.5 515.5,6612.5 743.5,6840.5 852.28,6840.5 934.02,6758.75 ; 933.89,6758.89 969.77,6723 ccw(c1023.69,6776.92) 1077.61,6723 1186.35,6831.74 cw(c1209.15,6808.94) 1231.95,6831.74 1264.83,6798.86 cw(c1242.03,6776.06) 1274.28,6776.06 cw(c1242.03,6776.06) 1264.83,6753.25 970.64,6459.05 ccw(c1024.55,6405.14) 970.64,6351.22 1003.52,6318.34 ccw(c1057.43,6372.26) 1111.35,6318.34 1220.09,6427.08 cw(c1242.89,6404.27) 1265.7,6427.08 2374.28,5318.49 2893.27,5318.49 2994,5318.49 2997.51,5322 R112.2@3031.99,5322
OUT11_N: R116.1 U1.58 | length 271.5
  L1-Top Layer (GTL) w8: R116.1@3071.01,5359 3104.49,5359 3115,5348.49 3126.49,5348.49 3194.48,5415.48 3292.27,5415.48 3294.11,5417.32 U1.58@3309.92,5417.32
OUT11_P: R112.1 U1.59 | length 271.5
  L1-Top Layer (GTL) w8: R112.1@3071,5322 3104.51,5322 3115,5332.49 3133.12,5332.49 3201.11,5399.48 3292.27,5399.48 3294.11,5397.64 U1.59@3309.92,5397.64
OUT_XO: R43.1 Y1.5 | length 64.6
  L1-Top Layer (GTL) w10: R43.1@3870.18,3284.21 Y1.5@3934.78,3284.21
PUR: R147.1 R149.2 S6.1 S6.2 U8.63 | length 1550.1
  L1-Top Layer (GTL) w11: S6.1@496.38,473.07 S6.1@505.87,463.58 S6.1@507.02,463.58 ; S6.1@506.36,462.93 S6.1@507.02,463.58 ; R147.1@604,663.5 527.23,663.5 514.5,650.77 514.5,610 514.5,471.07 S6.1@507.02,463.58 ; v3(935,835) 864.13,764.13 S6.2@864.13,463.58 S6.1@507.02,463.58 ; v7@1358.68,789.69 U8.63@1408.08,789.69
  L8-Bottom Layer (GBL) w11: v3(935,835) 937,833 1231,833 1274.67,789.33 v7(1358.32,789.33)
R_IN0_N: R29.1 R30.2 R31.1 R32.2 | length 179.4
  L1-Top Layer (GTL) w11: R31.1@3750.15,5833.65 3809.23,5892.72 3841.73,5925.22 R30.2@3877,5960.49
R_IN0_P: R26.2 R27.1 R28.2 R29.2 | length 179.4
  L1-Top Layer (GTL) w11: R27.1@3789.11,5794.68 3848.19,5853.76 3881.07,5886.64 R26.2@3915.96,5921.53
R_IN1_N: R36.1 R37.2 R38.1 R39.2 | length 153
  L1-Top Layer (GTL) w11: R38.1@3663.53,5906.31 3699.61,5942.39 3733.11,5975.89 R37.2@3771.69,6014.47
R_IN1_P: R33.2 R34.1 R35.2 R36.2 | length 153
  L1-Top Layer (GTL) w11: R34.1@3623.53,5946.31 3659.61,5982.39 R35.2@3693.81,6016.61 3730.69,6053.47 R33.2@3731.69,6054.47
SCLK: R61.2 U5.1 | length 69.1
  L1-Top Layer (GTL) w11: U5.1@1471.28,2424.3 1471.28,2445.28 1486.91,2460.91 R61.2@1486.91,2486.9
SMA_IN0_N: J5.1 R30.1 | length 4373.5
  L1-Top Layer (GTL) w11: R30.1@3905.16,5991.65 3917.4,6003.89 3928.25,6003.89 5975.5,8051.14 5975.5,8278.05 ccw(c5943.25,8278.05) 5943.25,8310.3 5843.05,8310.3 cw(c5843.05,8386.55) 5766.8,8386.55 5766.8,8433.05 cw(c5843.05,8433.05) 5843.05,8509.3 5943.25,8509.3 ccw(c5943.25,8541.55) 5975.5,8541.55 5975.5,8608 5866.75,8716.75 5846.92,8736.58 ccw(c5841.99,8731.64) 5837.05,8736.58 cw(c5826.91,8746.73) 5816.76,8736.58 5808.06,8745.28 cw(c5818.21,8755.42) 5808.06,8765.57 ccw(c5803.13,8770.5) 5808.06,8775.44 5798.5,8785 5747.5,8834 J5.1@5747.5,9057.57
SMA_IN0_P: J4.1 R26.1 | length 4382.9
  L1-Top Layer (GTL) w11: R26.1@3948.61,5951.18 3960.85,5963.42 3960.85,5974.27 6019.5,8032.92 6019.5,8278.05 ccw(c5943.25,8278.05) 5943.25,8354.3 5843.05,8354.3 cw(c5843.05,8386.55) 5810.8,8386.55 5810.8,8433.05 cw(c5843.05,8433.05) 5843.05,8465.3 5943.25,8465.3 ccw(c5943.25,8541.55) 6019.5,8541.55 6019.5,8608 6247.5,8836 J4.1@6247.5,9057.57
SMA_IN1_N: J7.1 R37.1 | length 4322.5
  L1-Top Layer (GTL) w11: R37.1@3801.03,6040.81 3816.14,6055.92 3816.14,6068.8 4189.07,6441.72 4189.07,6487.36 ; 4189,6487.36 4189,6906.5 5006.42,7723.91 5019.31,7736.8 5019.31,7982.62 ccw(c4943.06,7982.62) 4943.06,8058.87 4840,8058.87 cw(c4840,8091.12) 4807.75,8091.12 4807.75,8137.62 cw(c4840,8137.62) 4840,8169.87 5154.61,8169.87 ccw(c5154.61,8246.12) 5230.86,8246.12 5230.86,8292.62 ccw(c5154.61,8292.62) 5154.61,8368.87 5051.56,8368.87 cw(c5051.56,8401.12) 5019.31,8401.12 5019.31,8454.5 5019.31,8493 5019.31,8607.8 5247.5,8836 J7.1@5247.5,9057.57
SMA_IN1_P: J6.1 R33.1 | length 4311.1
  L1-Top Layer (GTL) w11: R33.1@3757.03,6082.81 3772.14,6097.92 3782.95,6097.92 4145,6459.98 4145,6924.72 4975.31,7755.03 4975.31,7982.62 ccw(c4943.06,7982.62) 4943.06,8014.87 4840,8014.87 cw(c4840,8091.12) 4763.75,8091.12 4763.75,8137.62 cw(c4840,8137.62) 4840,8213.87 5154.61,8213.87 ccw(c5154.61,8246.12) 5186.86,8246.12 5186.86,8292.62 ccw(c5154.61,8292.62) 5154.61,8324.87 5051.56,8324.87 cw(c5051.56,8401.12) 4975.31,8401.12 4975.31,8454.5 4975.31,8493 4975.31,8608.2 4745,8772 J6.1@4747.5,9057.57
SMA_O0_N: J11.1 R82.2 R128.2 | length 217.6
  L1-Top Layer (GTL) w11: J11.1@103.43,3612.5 254,3612.5 R128.2@321,3612.5
SMA_O0_P: J9.1 R78.2 R132.2 | length 227.9
  L1-Top Layer (GTL) w11: J9.1@103.43,4112.5 254,4112.5 R132.2@331.31,4112.5
SMA_O1_N: C100.1 J12.1 R85.2 | length 217.6
  L1-Top Layer (GTL) w11: J12.1@103.43,3112.5 254,3112.5 C100.1@321,3112.5
SMA_O1_P: C98.1 J10.1 R79.2 | length 217.6
  L1-Top Layer (GTL) w11: J10.1@103.43,2612.5 254,2612.5 C98.1@321,2612.5
SMA_O2_N: C103.1 J15.1 R90.2 | length 219.6
  L1-Top Layer (GTL) w11: C103.1@6677,3112.5 6744,3112.5 J15.1@6896.57,3112.5
SMA_O2_P: C101.1 J13.1 R86.2 | length 219.6
  L1-Top Layer (GTL) w11: C101.1@6677,2612.5 6744,2612.5 J13.1@6896.57,2612.5
SMA_O3_N: C104.1 J16.1 R92.2 | length 227.9
  L1-Top Layer (GTL) w11: C104.1@6668.63,3612.5 6744,3612.5 J16.1@6896.57,3612.5
SMA_O3_P: C102.1 J14.1 R88.2 | length 227.9
  L1-Top Layer (GTL) w11: C102.1@6668.63,4112.5 6744,4112.5 J14.1@6896.57,4112.5
SMA_O4_N: C107.1 J19.1 R99.2 | length 219.6
  L1-Top Layer (GTL) w11: C107.1@6677,5612.5 6744,5612.5 J19.1@6896.57,5612.5
SMA_O4_P: C105.1 J17.1 R94.2 | length 219.6
  L1-Top Layer (GTL) w11: C105.1@6677,6112.5 6744,6112.5 J17.1@6896.57,6112.5
SMA_O5_N: C108.1 J20.1 R101.2 | length 219.6
  L1-Top Layer (GTL) w11: C108.1@6677,5112.5 6744,5112.5 J20.1@6896.57,5112.5
SMA_O5_P: C106.1 J18.1 R96.2 | length 219.6
  L1-Top Layer (GTL) w11: C106.1@6677,4612.5 6744,4612.5 J18.1@6896.57,4612.5
SMA_O6_N: C111.1 J23.1 R109.2 | length 219.6
  L1-Top Layer (GTL) w11: C111.1@6677,7112.5 6744,7112.5 J23.1@6896.57,7112.5
SMA_O6_P: C109.1 J21.1 R103.2 | length 219.6
  L1-Top Layer (GTL) w11: C109.1@6677,6612.5 6744,6612.5 J21.1@6896.57,6612.5
SMA_O7_N: C112.1 J24.1 R111.2 | length 219.6
  L1-Top Layer (GTL) w11: C112.1@6677,7612.5 6744,7612.5 J24.1@6896.57,7612.5
SMA_O7_P: C110.1 J22.1 R105.2 | length 219.6
  L1-Top Layer (GTL) w11: C110.1@6677,8112.5 6744,8112.5 J22.1@6896.57,8112.5
SMA_O8_N: C115.1 J27.1 R117.2 | length 217.6
  L1-Top Layer (GTL) w11: C115.1@1747.5,8840 1747.5,8907 J27.1@1747.5,9057.57
SMA_O8_P: C113.1 J25.1 R113.2 | length 217.6
  L1-Top Layer (GTL) w11: C113.1@2247.5,8840 2247.5,8907 J25.1@2247.5,9057.57
SMA_O9_N: C116.1 J28.1 R119.2 | length 217.6
  L1-Top Layer (GTL) w11: C116.1@1247.5,8840 1247.5,8907 J28.1@1247.5,9057.57
SMA_O9_P: C114.1 J26.1 R115.2 | length 217.6
  L1-Top Layer (GTL) w11: C114.1@747.5,8840 747.5,8907 J26.1@747.5,9057.57
SMA_O10_N: C119.1 J31.1 R125.2 | length 217.6
  L1-Top Layer (GTL) w11: J31.1@103.43,7612.5 254,7612.5 C119.1@321,7612.5
SMA_O10_P: C117.1 J29.1 R121.2 | length 217.6
  L1-Top Layer (GTL) w11: J29.1@103.43,8112.5 254,8112.5 C117.1@321,8112.5
SMA_O11_N: C120.1 J32.1 R127.2 | length 217.6
  L1-Top Layer (GTL) w11: J32.1@103.43,7112.5 254,7112.5 C120.1@321,7112.5
SMA_O11_P: C118.1 J30.1 R122.2 | length 217.6
  L1-Top Layer (GTL) w11: J30.1@103.43,6612.5 254,6612.5 C118.1@321,6612.5
SMA_XO_P: C70.1 J8.1 | length 211.7
  L1-Top Layer (GTL) w11: J8.1@3479,2967.4 C70.1@3479,3179.05
U2A_3V3: C97.1 C130.1 C142.2 C143.2 C144.2 R57.2 R58.2 R59.2 R60.2 R165.1 R166.2 R212.2 TP41.1 U6.1 U8.11 U8.18 U8.50 | length 4978
  L1-Top Layer (GTL) w8: C130.1@1031.51,1149 C130.1@1039,1141.51
  L1-Top Layer (GTL) w10: U8.50@1682.55,906.61 1682.55,954.77 v3(1690.82,963.04) 1682.71,971.15 C144.2@1682.71,1010.35
  L1-Top Layer (GTL) w11: U6.1@965.78,1149 C130.1@1031.51,1149 ; U8.11@1682.55,377.09 U8.11@1682.71,376.93 ; C142.2@1682.71,283.35 C142.2@1687.71,278.35 ; C143.2@1820.35,280.71 C143.2@1822.71,278.35
  L1-Top Layer (GTL) w12: C142.2@1682.71,283.35 U8.11@1682.71,376.93 ; C143.2@1820.35,280.71 U8.18@1820.35,377.09
  L1-Top Layer (GTL) w20: C130.1@1039,1141.51 1168.52,1141.51 TP41.1@1180.98,1153.97 ; R60.2@1259.5,2085 1216,2085 1169.5,2038.5 R59.2@1169.5,2010 1169.5,1959.5 1064,1854 1064,1395 1180.98,1278.02 TP41.1@1180.98,1153.97 ; v3(1508,1244) 1415,1244 1324.97,1153.97 TP41.1@1180.98,1153.97 ; R58.2@1682.97,1178.52 v3(1682.97,1238.28) ; v3@1684.13,1237.12 v3(1866.51,1237.12) R57.2@1866.51,1177.36 ; C142.2@1687.71,278.35 1689.21,276.85 v7@1722.71,276.85 ; v7(1784.71,276.85) 1821.21,276.85 C143.2@1822.71,278.35 ; v3(1949.05,157) R166.2@2029.5,157
  L1-Top Layer (GTL) w30: v7(1034.71,275.85) 1088.72,275.85 R165.1@1089.72,276.85
  L8-Bottom Layer (GBL) w20: v7@1035.71,276.85 v7(1724.71,276.85) ; v3(1508,1244) 1513.72,1238.28 v3(1682.97,1238.28) ; v3(1866.51,1237.12) 1866.51,1200.08 1836.9,1170.47 1836.9,1094.1 1705.84,963.04 1747,921.88 1747,538 1680.28,471.28 1680.28,353.72 1724.71,309.29 v7(1724.71,276.85) ; v3(1949.05,157) 1829.2,276.85 v7(1784.71,276.85) v7(1724.71,276.85)
  L8-Bottom Layer (GBL) w25: R212.2@1491.5,1473 1491.5,1260.5 v3(1508,1244) ; v3(1690.82,963.04) 1705.84,963.04
U2A_I2CPU: U5.2 U8.42 | length 2414.9
  L1-Top Layer (GTL) w11: v3(1294,1063) 1294,1023 1461,856 1479,856 1523,812 1803,812 1840.03,849.03 U8.42@1840.03,906.61 ; v7(1425.41,2401.9) 1440.41,2386.9 U5.2@1471.28,2386.9
  L8-Bottom Layer (GBL) w11: v3(1294,1063) 1294,1247 1257,1284 1257,1358 1083,1532 1083,2142 1342.9,2401.9 v7(1425.41,2401.9)
U2A_SCLBRD: U8.38
U2A_SDABRD: U8.37
U2AADC0: R161.2 | length 4.2
  L1-Top Layer (GTL) w11: R161.2@1272.71,215.35 R161.2@1275.71,212.35
U2AADC1: R162.2
U2AGPIO0: J42.20 JP5.A01 R57.1 R155.1 | length 1715.7
  L1-Top Layer (GTL) w12: v3(1228.36,1554.64) JP5.A01@1228.36,1665.92 ; R155.1@1802.71,1073.35 1803.71,1074.35 v7(1803.71,1127.85) R57.1@1803.71,1177.16
  L8-Bottom Layer (GBL) w12: J42.20@1429,1973.04 1378,1973.04 1378,1844 1369,1835 1296,1835 1280,1819 1280,1580 1253.72,1580 v3(1228.36,1554.64) 1292,1491 1292,1288 1500,1080 1755.86,1080 v7(1803.71,1127.85)
U2AGPIO1: J42.19 JP5.A02 R58.1 R156.1 | length 1187.5
  L1-Top Layer (GTL) w12: v3(1326.6,1552.4) 1326.6,1664.16 JP5.A02@1327.99,1665.55 ; R156.1@1742.71,1073.35 1745.71,1076.35 v7(1745.71,1123.85) R58.1@1745.71,1178.26
  L8-Bottom Layer (GBL) w12: J42.19@1429,1702.96 1389.96,1702.96 1379,1692 1379,1587 1363.86,1571.86 1349.58,1571.86 1330.12,1552.4 v3(1326.6,1552.4) 1326.6,1305.4 1458,1174 1695.56,1174 v7(1745.71,1123.85)
U2AGPIO2: J42.18 JP5.A04 R154.2 | length 1537.6
  L1-Top Layer (GTL) w11: JP5.A04@1528.36,1665.92 1530,1664.28 1529,1663.28 v9(1529,1549) 1529,1390.28 1530,1389.28 1528.36,1387.64 1560,1356 1828,1356 1934,1250 1934,1150 1908.85,1124.85 1873.85,1124.85 1857.71,1108.71 R154.2@1857.71,1073.35 R154.2@1860.71,1076.35
  L8-Bottom Layer (GBL) w11: J42.18@1519,1911 1529,1921 J42.18@1529,1973.04 1564.96,1973.04 1579,1959 1579,1584 1544,1549 v9(1529,1549)
U2AGPIO3: J42.17 R76.1 R153.2 | length 5576.7
  L1-Top Layer (GTL) w10: v3(337.14,1579.72) R76.1@337.14,1641.22
  L1-Top Layer (GTL) w11: v9(1137,1402) 1198.05,1463.05 1401.75,1463.05 1435.71,1497.01 1435.71,1516.51 v9(1473.3,1554.1) ; R153.2@2094.21,691.85 v3(2150.85,691.85)
  L8-Bottom Layer (GBL) w11: v9(1137,1402) 514.86,1402 v3(337.14,1579.72) 128,1370.58 128,584 265,447 265,163 342,86 1975,86 2150.85,261.85 v3(2150.85,691.85) ; v9(1473.3,1554.1) 1476.94,1557.74 1476.94,1568.04 1477.6,1568.7 1477.6,1688.6 1491.96,1702.96 J42.17@1529,1702.96
U2AGPIO4: J42.14 JP5.A05 R157.2 | length 1106.2
  L1-Top Layer (GTL) w10: v3(1627.5,1556.8) 1627.5,1665.06 JP5.A05@1628.36,1665.92
  L1-Top Layer (GTL) w12: R157.2@1617.71,1073.35 1618.71,1074.35 v3(1618.71,1300.29)
  L8-Bottom Layer (GBL) w10: v3(1627.5,1556.8) 1631.56,1556.8 1638.13,1563.38 1654.72,1563.38 1679,1587.66 1679,1959 1693.04,1973.04 J42.14@1729,1973.04
  L8-Bottom Layer (GBL) w12: v3(1618.71,1300.29) 1618.71,1340.71 1649,1371 1649,1477.72 1627.5,1499.22 v3(1627.5,1556.8)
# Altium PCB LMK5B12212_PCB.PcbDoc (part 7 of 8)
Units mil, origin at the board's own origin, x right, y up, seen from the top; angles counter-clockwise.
Board outline 7000 x 9161 mil, 8 copper layers (L1-Top Layer (GTL), L2-GND Plane (GP1), L3-Mid-Layer 2 (G1), L4-Mid-Layer 3 (G2), L5-Mid-Layer 4 (G3), L6-Mid-Layer 5 (G4), L7-Mid-Layer 6 (G5), L8-Bottom Layer (GBL)), stack 61.2 mil thick; 469 components, 264 nets, 1268 pads, 1812 vias.

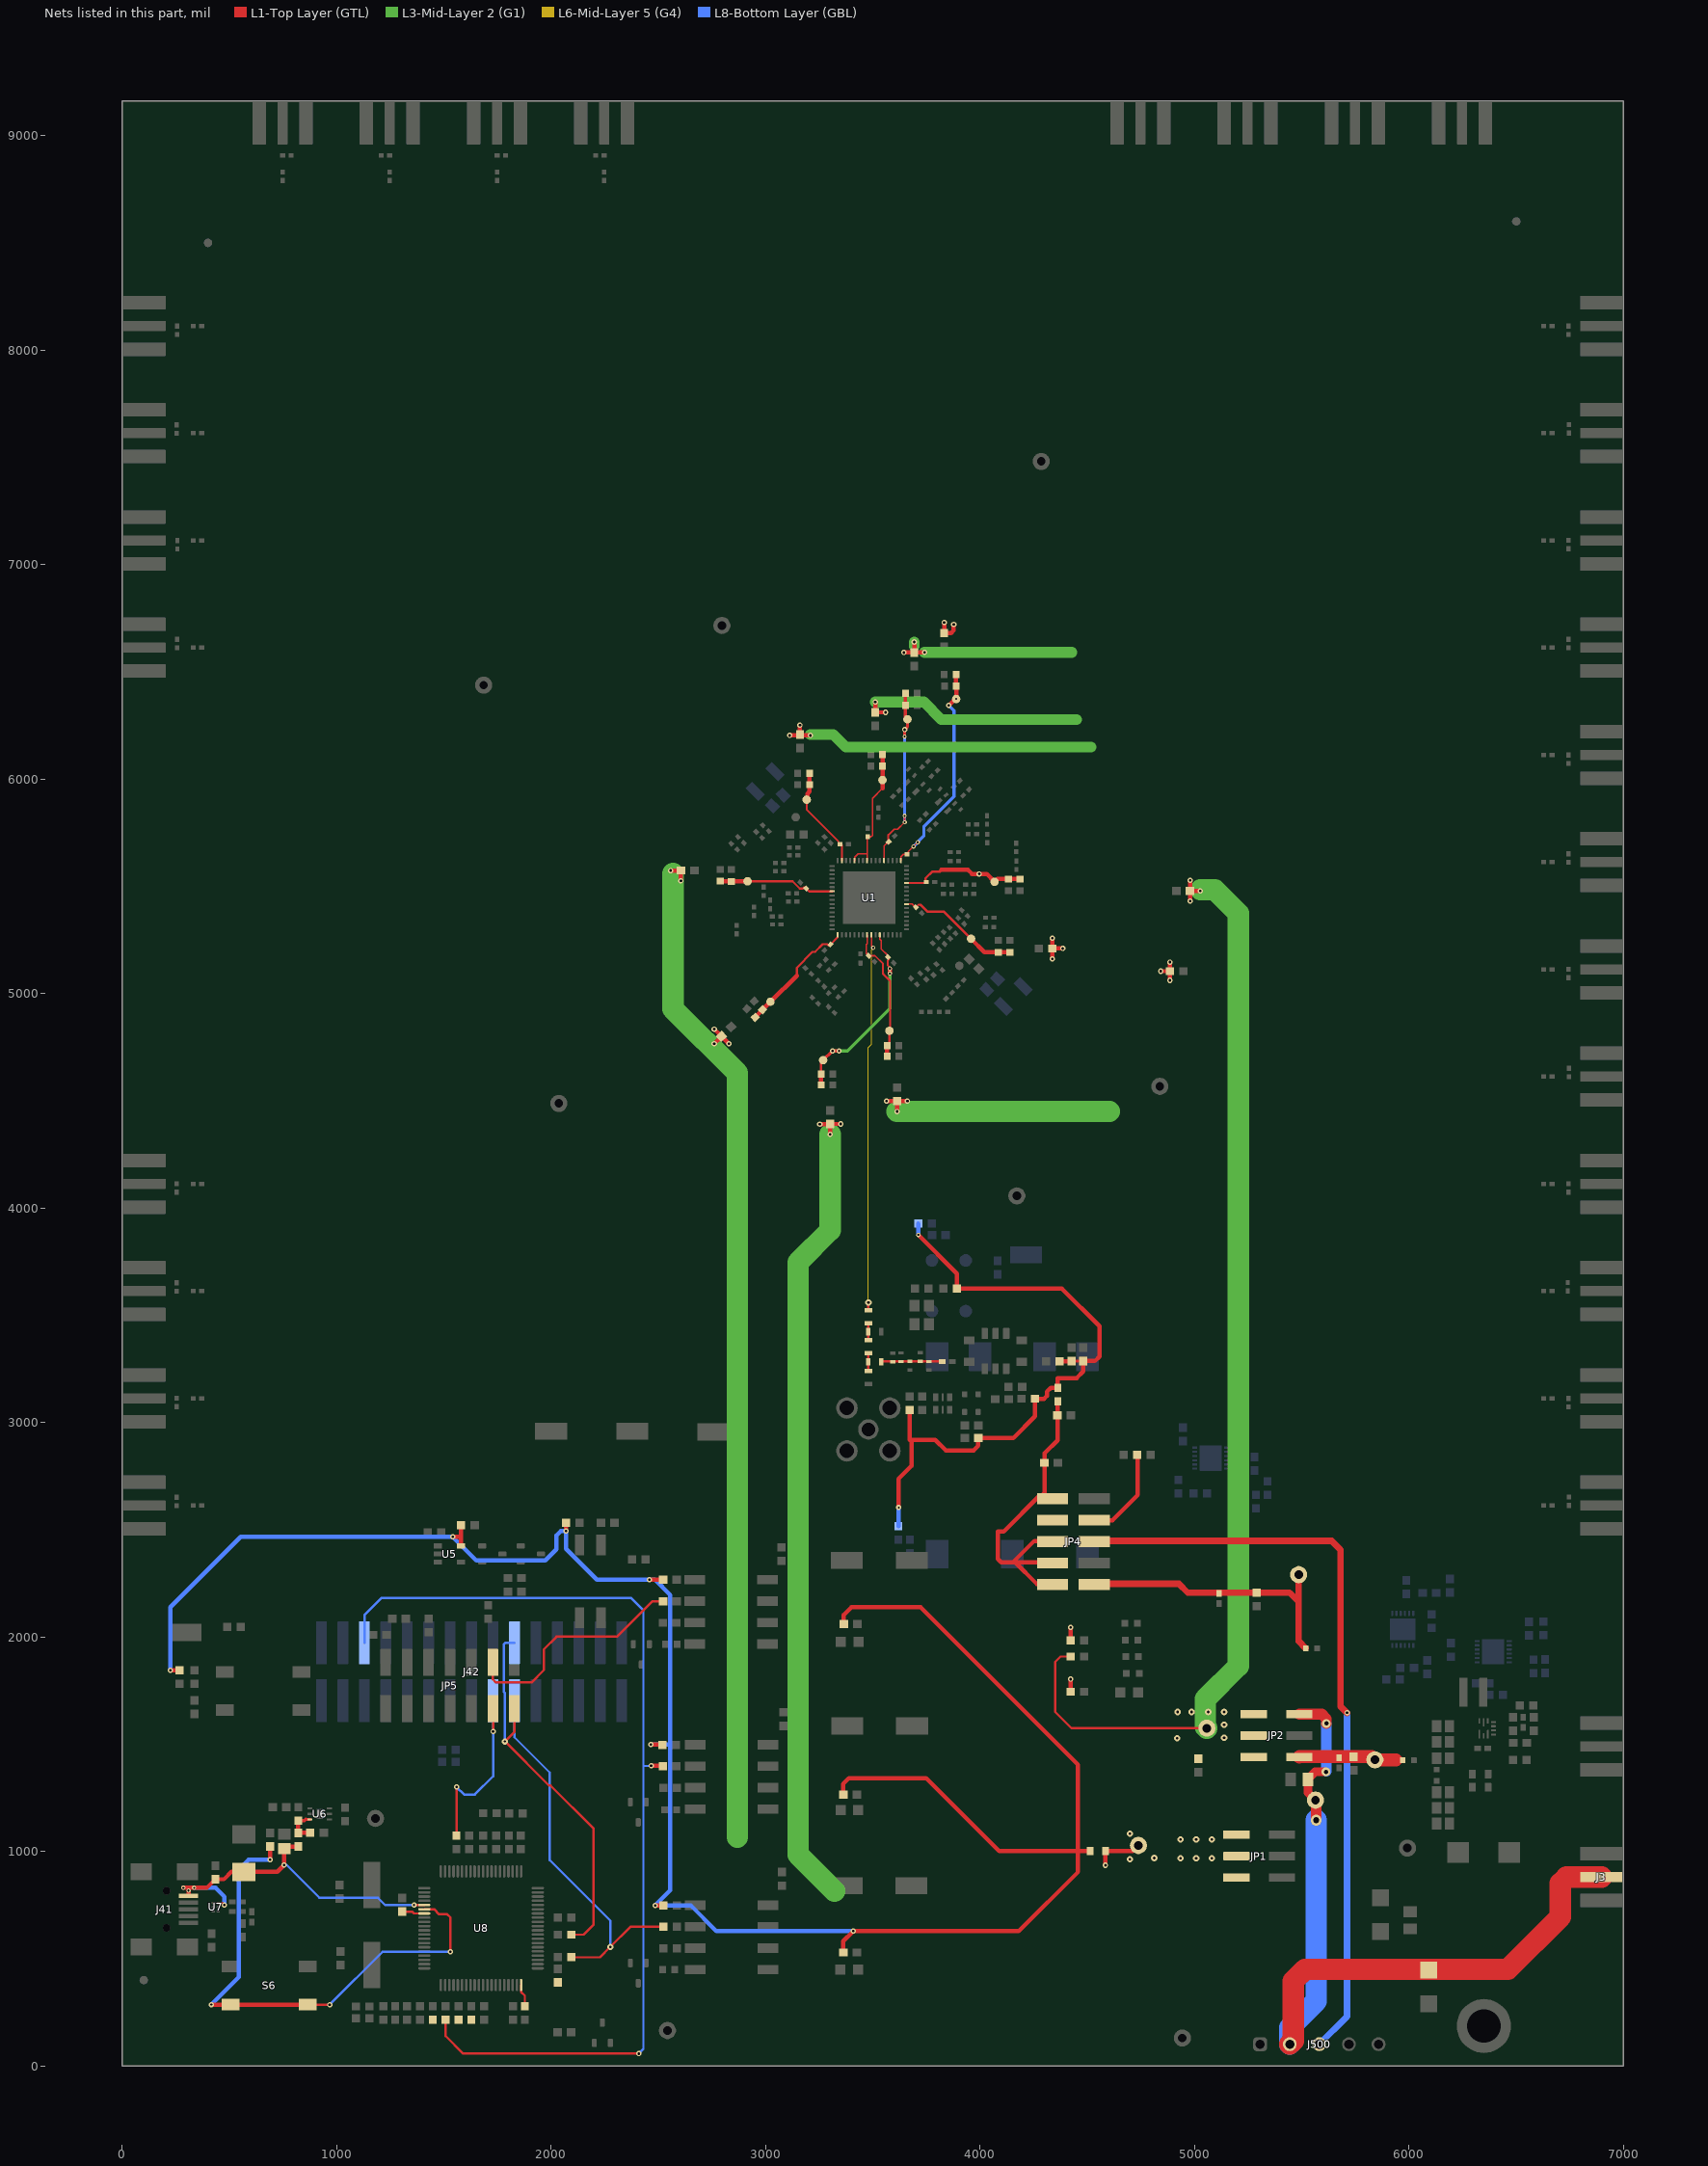
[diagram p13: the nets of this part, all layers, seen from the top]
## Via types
v1: diameter 20, hole 10, L1-Top Layer (GTL) to L8-Bottom Layer (GBL), tented top, 987 vias
v2: diameter 30, hole 12, L1-Top Layer (GTL) to L8-Bottom Layer (GBL), 407 vias
v3: diameter 25, hole 12, L1-Top Layer (GTL) to L8-Bottom Layer (GBL), tented top, 163 vias
v4: diameter 30, hole 12, L1-Top Layer (GTL) to L8-Bottom Layer (GBL), tented top, 52 vias
v5: diameter 19.68, hole 7.87, L1-Top Layer (GTL) to L8-Bottom Layer (GBL), 47 vias
v6: diameter 20, hole 10, L1-Top Layer (GTL) to L8-Bottom Layer (GBL), 39 vias
v7: diameter 25, hole 10, L1-Top Layer (GTL) to L8-Bottom Layer (GBL), tented top, 35 vias
v8: diameter 25, hole 12, L1-Top Layer (GTL) to L8-Bottom Layer (GBL), 23 vias
v9: diameter 30, hole 10, L1-Top Layer (GTL) to L8-Bottom Layer (GBL), 10 vias
v10: diameter 40, hole 20, L1-Top Layer (GTL) to L8-Bottom Layer (GBL), 10 vias
v11: diameter 18, hole 10, L1-Top Layer (GTL) to L8-Bottom Layer (GBL), tented top, 8 vias
v12: diameter 20, hole 10, L1-Top Layer (GTL) to L8-Bottom Layer (GBL), tented both sides, 6 vias
v13: diameter 39.37, hole 19.68, L1-Top Layer (GTL) to L8-Bottom Layer (GBL), tented top, 6 vias
v14: diameter 50, hole 28, L1-Top Layer (GTL) to L8-Bottom Layer (GBL), 4 vias
v15: diameter 23, hole 10, L1-Top Layer (GTL) to L8-Bottom Layer (GBL), tented top, 4 vias
v16: diameter 25, hole 10, L1-Top Layer (GTL) to L8-Bottom Layer (GBL), 4 vias
v17: diameter 25, hole 12, L1-Top Layer (GTL) to L8-Bottom Layer (GBL), tented both sides, 3 vias
v18: diameter 20/0/0/0/0/0/20 (per signal layer), hole 10, L1-Top Layer (GTL) to L8-Bottom Layer (GBL), tented top, 2 vias
v19: diameter 30, hole 12, L1-Top Layer (GTL) to L8-Bottom Layer (GBL), tented both sides, 1 vias
v20: diameter 25, hole 10, L1-Top Layer (GTL) to L8-Bottom Layer (GBL), tented both sides, 1 vias

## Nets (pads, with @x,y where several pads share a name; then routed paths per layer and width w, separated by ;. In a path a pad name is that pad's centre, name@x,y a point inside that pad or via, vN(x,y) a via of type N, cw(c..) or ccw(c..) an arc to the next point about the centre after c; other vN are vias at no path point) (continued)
U2AGPIO5: J42.13 JP5.A06 R158.2 | length 908.4
  L1-Top Layer (GTL) w11: JP5.A06@1728.36,1665.92 1729,1665.28 v3(1729,1559.6)
  L1-Top Layer (GTL) w12: R158.2@1557.71,1073.35 R158.2@1558.71,1074.35 ; R158.2@1557.71,1075.35 R158.2@1558.71,1074.35 ; v3(1558.71,1300.29) R158.2@1558.71,1074.35
  L8-Bottom Layer (GBL) w11: v3(1558.71,1300.29) 1594,1265 1644,1265 1729,1350 J42.13@1729,1702.96
U2AGPIO5/SOMI: JP5.B06 R71.2 | length 1091.3
  L1-Top Layer (GTL) w11: JP5.B06@1728.36,1880.88 1728.36,1801.64 1742,1788 1908,1788 1966,1846 1966,1942 2025,2001 2307,2001 2472.55,2166.55 R71.2@2521.71,2166.55
U2AGPIO6: J42.12 JP5.A07 R151.2 | length 1837.8
  L1-Top Layer (GTL) w10: R151.2@2094.21,611.85 R151.2@2098.21,615.85
  L1-Top Layer (GTL) w11: JP5.A07@1828.36,1665.92 1828.36,1556.56 v9(1784.3,1512.5) 1989.37,1307.43 1996.57,1307.43 2198,1106 2198,659 2150.85,611.85 R151.2@2094.21,611.85
  L8-Bottom Layer (GBL) w11: v9(1784.3,1512.5) 1784.3,1738.67 1779,1743.97 1779,1965 1787.04,1973.04 J42.12@1829,1973.04
U2AGPIO7: J42.11 R52.1 R152.2 | length 1820.8
  L1-Top Layer (GTL) w11: R152.2@2094.8,506.26 2227.26,506.26 v9(2276,555) 2369.55,648.55 R52.1@2523.52,648.55
  L8-Bottom Layer (GBL) w11: J42.11@1829,1702.96 1829,1532 1993,1368 1993,960 2276,677 v9(2276,555)
U2AGPIO8: J42.26 R64.1 R164.2 | length 4664.2
  L1-Top Layer (GTL) w11: R164.2@1507.71,215.35 1507.71,138.95 1589.66,57 v3(2408,57)
  L1-Top Layer (GTL) w20: v3(2466,1399) 2519.2,1399 R64.1@2521.08,1397.12
  L8-Bottom Layer (GBL) w10: 2431,1399 v3(2466,1399)
  L8-Bottom Layer (GBL) w11: J42.26@1129,1973.04 1129,2101 1210,2182 2372,2182 2430,2124 2430,79 v3(2408,57)
U2AGPIO9: R163.2
U2AGPIO10: R160.2
U2AGPIO11: R159.2 | length 2.8
  L1-Top Layer (GTL) w11: R159.2@1565.71,213.35 R159.2@1567.71,215.35
U2AGPIO12: R150.2
V18: C140.2 U8.67 | length 122.1
  L1-Top Layer (GTL) w11: C140.2@1317.21,707.85 C140.2@1305.71,719.35 1351,719.35 1359.61,710.75 U8.67@1407.95,710.75
VBUS: C131.1 C133.2 D11.1 FB13.1 J41.1 U7.6 U8.65 | length 1657.9
  L1-Top Layer (GTL) w11: U7.6@447.81,759.69 466.31,759.69 v7(476,750) ; v16(1360.4,750.12) U8.65@1407.95,750.12
  L1-Top Layer (GTL) w20: v1(285,830) 307.5,830 308.5,831 309,830.5 ; J41.1@308.36,792.99 309,793.63 v1(309,818) 309,830.5 ; FB13.1@820.5,1022.59 764.72,1022.59 C131.1@755.13,1013.01 v3(755.13,936.59) 723.18,904.64 D11.1@567.86,904.64 508.89,904.64 474.54,870.29 C133.2@434.1,870.29 393.81,830 v1(335,830) 309.5,830 309,830.5
  L8-Bottom Layer (GBL) w11: v3(755.13,936.59) 766.41,936.59 919,784 1192,784 1225.88,750.12 v16(1360.4,750.12)
  L8-Bottom Layer (GBL) w20: v1(335,830) 435,830 476,789 v7(476,750)
VBUS_FILT: C129.2 FB13.2 R145.1 U6.6 | length 170.1
  L1-Top Layer (GTL) w12: 855.5,1149.59 856.09,1149 U6.6@875.22,1149
  L1-Top Layer (GTL) w15: R145.1@820.5,1143.09 849,1143.09 855.5,1149.59
  L1-Top Layer (GTL) w20: R145.1@820.5,1143.09 820.5,1086.62 C129.2@876.46,1086.62
VCC_XO: C78.1 FB12.2 JP4.2 JP4.4 JP4.6 JP4.8 JP4.10 R15.1 | length 1605.3
  L1-Top Layer (GTL) w20: R15.1@4299.78,2811.59 4299.78,2672.8 4284.85,2657.87 4276.35,2657.87 4110.54,2492.06 4082.26,2492.06 4082.26,2364.24 4098.9,2347.6 4152.8,2347.6 ; R15.1@4300.76,2811.59 4300.76,2856.76 4360.76,2916.76 C78.1@4360.76,3032.57 4360.76,3097.67 FB12.2@4361.69,3098.59 ; JP4.2@4347.7,2247.6 4263.7,2247.6 4163.7,2347.6 ; JP4.4@4347.7,2347.6 4163.7,2347.6 ; JP4.6@4347.7,2447.6 4252.8,2447.6 4158.25,2353.05 4152.8,2347.6 ; 4152.8,2347.6 4163.7,2347.6
VCC_XO_FILT: C79.2 C80.1 FB12.1 R44.1 R206.1 R207.1 R208.2 R209.1 R210.1 R211.1 | length 3145.8
  L1-Top Layer (GTL) w12: C80.1@4426.5,3286.39 C79.2@4480.99,3286.39
  L1-Top Layer (GTL) w20: v7(3620.32,2603.43) 3620.32,2737.51 3679.59,2796.79 3679.59,2910.14 ; R211.1@3671,3057.5 3671,2918.73 3791,2918.73 3839.73,2870 3970,2870 3991.5,2891.5 R207.1@3991.5,2927 4154.28,2927 4255.86,3028.58 R44.1@4255.86,3110.68 4297.83,3110.68 4311.07,3123.92 4311.07,3143.29 4329.37,3161.59 FB12.1@4361.69,3161.59 4361.69,3207.31 4450.29,3207.31 4480.99,3238.01 C79.2@4480.99,3286.39 4535.16,3286.39 4556.26,3307.49 4556.26,3449.27 4380.69,3624.84 R208.2@3891.56,3624.84 3891.56,3694.44 v6(3711.5,3874.5) ; R206.1@4370.5,3285 4425.11,3285 C80.1@4426.24,3286.13 C80.1@4426.5,3286.39
  L8-Bottom Layer (GBL) w20: R210.1@3619.07,2516.5 v7@3619.07,2602.18 ; v6(3711.5,3874.5) R209.1@3711.5,3928
VCORE: C141.2 U8.20 | length 105.9
  L1-Top Layer (GTL) w11: U8.20@1859.72,377.09 1859.72,344.84 1877.05,327.51 C141.2@1877.05,278.35
VDD_APLL1: C59.1 C60.2 FB11.2 TP18.1 U1.47 | length 482.5
  L1-Top Layer (GTL) w8: TP18.1@3195.39,5907.81 TP18.1@3191.41,5903.83 3191.41,5858.09 3339.2,5710.3 3339.2,5701.24 3345.05,5695.4 C60.2@3347.01,5695.4 ; C60.2@3349.97,5698.35 3354.41,5693.91 3355.2,5693.91 U1.47@3355.2,5620.08
  L1-Top Layer (GTL) w20: TP18.1@3195.39,5907.81 3195.39,5931.39 3204.69,5940.69 FB11.2@3204.69,6025.89
VDD_APLL2: C53.1 C54.2 FB9.2 TP16.1 U1.23 | length 584
  L1-Top Layer (GTL) w8: U1.23@3656.38,5417.32 3682.99,5417.32 C54.2@3699.16,5401.15 ; C54.2@3700.16,5402.15 3712.11,5414.1 3721.9,5414.1
  L1-Top Layer (GTL) w11: 3721.9,5414.1 3753.94,5382.06 3830.76,5382.06 TP16.1@3957.71,5255.11
  L1-Top Layer (GTL) w20: TP16.1@3957.71,5255.11 4019.71,5193.11 FB9.2@4138.22,5193.11
VDD_DIG: C41.1 C42.2 FB5.2 TP12.1 U1.41 U1.44 | length 613.7
  L1-Top Layer (GTL) w8: U1.44@3414.25,5620.08 3414.82,5620.64 3414.82,5635.86 3430.16,5651.2 3473.31,5651.2 ; U1.41@3473.31,5620.08 3473.31,5651.2 ; 3544.7,5956.7 3498,5910 3498,5737.26 3492.2,5731.46 C42.2@3476.04,5731.46 3473.31,5728.73 3473.31,5651.2
  L1-Top Layer (GTL) w20: 3544.7,5956.7 TP12.1@3544.7,5995.31 FB5.2@3544.7,6113.87
VDD_IN0: C29.1 C30.2 FB1.2 TP8.1 U1.33 | length 1079.2
  L1-Top Layer (GTL) w7: U1.33@3630.79,5620.08 3630.79,5637.7 3642.28,5649.19 C30.2@3659.66,5649.19 3665,5654.53 3665,5661.13 v1(3708.87,5705)
  L1-Top Layer (GTL) w20: v3(3854.25,6343.27) TP8.1@3888.33,6377.35 ; C29.1@3887.43,6434.97 FB1.2@3887.43,6486.34 ; TP8.1@3888.73,6377.75 C29.1@3888.73,6433.67
  L8-Bottom Layer (GBL) w15: v1(3689.88,5686.01) 3737.67,5733.8 3737.67,5776.48 3878.86,5917.67 3878.86,6318.67 v3(3854.25,6343.27) ; v3@3858.25,6343.27 v3(3854.25,6343.27) ; v1(3888.33,6373.35) 3884.33,6373.35 v3(3854.25,6343.27)
VDD_IN1: C35.1 C36.2 FB3.2 TP10.1 U1.37 | length 893.4
  L1-Top Layer (GTL) w8: U1.37@3552.05,5620.08 3552.05,5688.28 3572,5708.23 3572,5739.53 3598.72,5766.25 3615.88,5766.25 3648,5798.37 v1(3648,5828)
  L1-Top Layer (GTL) w15: v1@3648.24,6198 v3(3648.24,6230.29) 3661.18,6243.23 TP10.1@3661.18,6278.63 3651.61,6288.2 C35.1@3651.61,6344.14 FB3.2@3651.61,6392.68
  L8-Bottom Layer (GBL) w15: v1(3648.24,5798.61) v3(3648.24,6230.29)
  other v1: 3648,6198
VDD_PLANE: C6.2 JP1.2 JP1.4 JP1.6 NT1.2 R11.2 R13.1 R16.2 R18.2 R20.2 R22.2 R25.2 R54.2 TP2.1 | length 5285.9
  L1-Top Layer (GTL) w20: v3(3111.56,6203.21) R25.2@3160.02,6203.21 ; v3(3160.02,6251.66) R25.2@3160.02,6203.21 ; v3(3208.47,6203.21) R25.2@3160.02,6203.21 ; v3(3511.08,6359.28) R18.2@3511.08,6310.83 v3(3559.53,6310.83) ; v3(3564.11,4498.42) 3612.56,4498.42 v3(3612.56,4449.96) ; R20.2@3612.65,4498.77 v3(3661.1,4498.77) ; v3(3644.73,6589.9) R16.2@3693.18,6589.9 ; R16.2@3692.17,6590.39 R16.2@3692.96,6590.39 ; v3(3692.96,6638.84) R16.2@3692.96,6590.39 ; v3(3740.62,6590.39) R16.2@3692.96,6590.39 ; v3(3832.36,6729.45) R11.2@3832.36,6681 3865,6681 3877,6693 v3(3877,6720.87) ; R22.2@4336.33,5210.12 v3(4336.33,5258.57) ; v3(4336.68,5161.57) 4336.68,5210.03 v3(4385.14,5210.03) ; R54.2@4421.86,1744.56 v3(4421.86,1803.14) ; R13.1@4421.86,1983.18 v3(4421.86,2044.56) ; v3(4584.65,935.35) NT1.2@4584.65,1001.42 4711.74,1001.42 TP2.1@4738.19,1027.87 ; v3(4842,5104) C6.2@4884.5,5104 ; v3(4884.5,5061.5) C6.2@4884.5,5104 ; v3(4884.5,5146.5) C6.2@4884.5,5104
  L3-Mid-Layer 2 (G1) w50: v3@3208.47,6207.21 3316.01,6207.21 3374.52,6148.7 4518,6148.7 ; v3(3511.08,6359.28) 3737.03,6359.28 3819.18,6277.13 4450,6277.13 ; 3692.96,6618.84 v3(3692.96,6638.84) ; v3@3740.62,6590.84 4427,6590.84
  L3-Mid-Layer 2 (G1) w100: v3(3612.56,4449.96) 4603,4449.96
  other v4: 4698.19,962.87 4934.33,968.5 5007.67,968.5 5081,968.5 4812,969 4934.17,1056.11 5007.51,1056.11 5080.84,1056.11 4698.19,1082.87
VDD_XO: C47.1 C48.2 FB7.2 TP14.1 U1.8 | length 637.5
  L1-Top Layer (GTL) w8: U1.8@3473.31,5273.62 3473.31,5232.16 3469.57,5228.42 3469.57,5186.89 C48.2@3480.34,5176.12 3509.84,5176.12 3547.05,5138.91 3547.05,5091.95
  L1-Top Layer (GTL) w11: 3547.05,5091.95 3580.54,5058.46 3580.54,4841.57 3577,4838.03 TP14.1@3577,4825.94 3577,4766.78 C47.1@3566.8,4756.58
  L1-Top Layer (GTL) w20: FB7.2@3566.8,4706.65 C47.1@3566.8,4756.58
VDD_XO_DCDC: C515.1 C516.1 JP4.1 L503.2 TP501.1 | length 1316.6
  L1-Top Layer (GTL) w30: JP4.1@4560.3,2247.6 4927,2247.6 4968.3,2206.3 5442.9,2206.3 5485.4,2163.8 ; TP501.1@5485.4,2290.5 5485.4,2163.8 ; L503.2@5518.33,1947.3 5485.4,1980.23 5485.4,2163.8
VDD_XO_LMK_OPT: JP4.7 R4.1 R23.1 | length 438.3
  L1-Top Layer (GTL) w20: JP4.7@4532.24,2544.3 4617.2,2544.3 4734.4,2661.5 R23.1@4734.4,2849.1
VDDGPIO: C89.2 NT1.1 R51.1 R56.2 R63.1 R67.2 R68.1 R70.1 R74.2 R75.1 U5.5 | length 10571.7
  L1-Top Layer (GTL) w20: v3(224.42,1844.22) R75.1@262.93,1844.22 ; v17(1540.41,2466.9) 1579.3,2466.9 ; U5.5@1579.54,2424.3 C89.2@1579.54,2520.22 ; v3(2068.77,2493.21) R68.1@2068.77,2531.71 ; v3@2458,2266.55 R70.1@2522.95,2266.55 ; v3(2464,1498) 2516.1,1498 R63.1@2518.28,1495.82 ; v3(2485.01,748.55) R51.1@2523.52,748.55 ; R56.2@3362.01,529.08 3362.01,581.01 v3(3409,628) 4180,628 4456.49,904.49 4456.49,1001.42 ; R67.2@3362.01,1265.08 3362.01,1315.01 3389,1342 3748,1342 4088.58,1001.42 4456.49,1001.42 ; R74.2@3364.52,2059.81 3364.52,2103.52 3399,2138 3723,2138 4456.49,1404.51 4456.49,1001.42 ; NT1.1@4513.79,1001.42 4456.49,1001.42
  L8-Bottom Layer (GBL) w20: v3(224.42,1844.22) 224.42,2138.42 552.9,2466.9 v17(1540.41,2466.9) 1650.31,2357 1972,2357 2024,2409 2024,2473 2044.21,2493.21 v3(2068.77,2493.21) 2068.77,2410.23 2212.45,2266.55 2484.44,2266.55 2555,2195.99 2555,818.54 v3(2485.01,748.55) 2650.45,748.55 2771,628 v3(3409,628) ; v3(2464,1498) 2551.65,1498 2553.82,1495.82
  other v3: 2458,2267
VDDO_0_1: C32.1 C33.2 FB2.2 TP9.1 U1.1 | length 566
  L1-Top Layer (GTL) w10: 3146,5083 3146,5119.61 3218.76,5194.52 3230.92,5194.52 3266.3,5229.9 3286.37,5229.9 3292.5,5223.77 3297.13,5223.77 C33.2@3297.68,5224.32 ; C33.2@3302.41,5229.05 3335.51,5262.15 U1.1@3335.51,5273.62
  L1-Top Layer (GTL) w20: FB2.2@2950.95,4889.24 C32.1@2985.79,4924.08 ; C32.1@2985.79,4924.94 TP9.1@3019.75,4958.9 ; TP9.1@3022.58,4961.73 3146,5083
VDDO_2_3: C38.1 C39.2 FB4.2 TP11.1 U1.11 | length 953.8
  L1-Top Layer (GTL) w8: U1.11@3532.36,5273.62 3532.36,5254.03 3538.94,5247.45 3538.94,5207.3 3569.82,5176.42 C39.2@3569.82,5165.93 ; C39.2@3570.07,5165.38 3574.29,5165.38 3574.85,5164.82 3574.85,5158.78 3569.72,5153.65 3569.72,5129.53 3579.15,5120.1 v1(3579.15,5116.85)
  L1-Top Layer (GTL) w11: C38.1@3258.53,4623.46 3258.53,4679.61 TP11.1@3268.02,4689.1
  L1-Top Layer (GTL) w15: TP11.1@3268.02,4689.1 v3(3311.21,4732.29) v15(3342,4732.29)
  L1-Top Layer (GTL) w20: FB4.2@3258.53,4573.78 C38.1@3258.53,4623.46 ; v1(3579.15,5093) v1(3579.15,5116.85)
  L3-Mid-Layer 2 (G1) w15: v3(3311.21,4732.29) 3381.39,4732.29 3579.15,4930.05 v1(3579.15,5093) v1(3579.15,5116.85)
VDDO_4_TO_7: C44.1 C45.2 FB6.2 TP13.1 U1.28 | length 595.7
  L1-Top Layer (GTL) w8: U1.28@3656.38,5515.75 C45.2@3745.1,5515.75 ; v3@3997.12,5557.76 v3@3997.96,5557.76
  L1-Top Layer (GTL) w11: C45.2@3745.1,5515.75 3745.1,5536.48 3777.71,5569.09 3810.6,5569.09
  L1-Top Layer (GTL) w15: 3810.6,5569.09 3818.64,5577.13
  L1-Top Layer (GTL) w20: 3818.64,5577.13 3942.72,5577.13 3962.09,5557.76 3995.49,5557.76 v3(3995.92,5557.76) v3@3997.12,5557.76 ; v3@3997.96,5557.76 4030.46,5557.76 TP13.1@4067.45,5520.77 4080.27,5533.59 C44.1@4133,5533.59 FB6.2@4185.81,5533.59
VDDO_8_TO_11: C50.1 C51.2 FB8.2 TP15.1 U1.55 | length 535.2
  L1-Top Layer (GTL) w10: FB8.2@2792.53,5523.34 FB8.2@2792.69,5523.18 ; TP15.1@2915.38,5523.18 3124.98,5523.18 3159.11,5489.05 3172.94,5489.05 3179.07,5495.18 3183.69,5495.18 C51.2@3184.25,5494.62 ; C51.2@3188.98,5489.89 3202.49,5476.38 U1.55@3309.92,5476.38
  L1-Top Layer (GTL) w20: FB8.2@2792.69,5523.18 C50.1@2840.69,5523.18 TP15.1@2915.38,5523.18
VDDO_DCDC: C513.1 C514.1 JP2.1 L502.2 TP4.1 | length 459.1
  L1-Top Layer (GTL) w60: JP2.1@5488.3,1440 5488.3,1441.93 5826.37,1441.93 TP4.1@5841.1,1427.2 5939.41,1427.2
VDDO_PLANE: C21.2 JP2.2 JP2.4 JP2.6 R12.2 R14.1 R17.2 R19.2 R21.2 TP5.1 | length 13953.6
  L1-Top Layer (GTL) w10: R14.1@4421.86,1908.44 4374.43,1908.44 4349.89,1883.9 4349.89,1650.19 4425.49,1574.59 TP5.1@5057.36,1574.59
  L1-Top Layer (GTL) w20: v3(2556.55,5573.42) R21.2@2605,5573.42 v3(2605,5524.97) ; v3(2760.23,4765.68) R12.2@2794.49,4799.94 ; v3(2760.23,4834.21) R12.2@2794.49,4799.94 ; v3(2828.75,4765.68) R12.2@2794.49,4799.94 ; v3(3252.49,4391.32) 3300.94,4391.32 v3(3300.94,4342.86) ; R17.2@3301.03,4391.67 v3(3349.48,4391.67) ; v3(4978.74,5430.34) R19.2@4978.74,5478.79 v3(5027.19,5478.79) ; R19.2@4979,5479 v3(4979,5527.45)
  L3-Mid-Layer 2 (G1) w100: 2567.59,5558.97 2567.59,4929.38 2867.75,4629.22 2867.75,1066.46 ; v3(3300.94,4342.86) 3300.94,3895.99 3151,3746.05 3151,985.3 3321.47,814.83 ; v3@5027.19,5483.79 5094.21,5483.79 5203.86,5374.14 5203.86,1864.65 5050,1710.79 5050,1581.95 TP5.1@5057.36,1574.59
  other v4: 4918,1527 5138.09,1530.05 5138.09,1590.18 4921,1650.31 4986.43,1650.31 5063.87,1650.31 5138.09,1650.31
VIN2: C27.1 D2.1 J3.1 J500.2 JP2.5 TP7.1 | length 3811.8
  L1-Top Layer (GTL) w5: TP7.1@5563.8,1239.2 TP7.1@5567.32,1235.68
  L1-Top Layer (GTL) w40: TP7.1@5563.8,1239.2 5528.12,1274.88 C27.1@5528.12,1336.34 5562.38,1370.6 v10(5612.3,1370.6)
  L1-Top Layer (GTL) w50: JP2.5@5488.3,1640 5593.7,1640 5614.7,1619 v10(5614.7,1596.3) ; v14(5567.32,1145.88) TP7.1@5567.32,1235.68
  L1-Top Layer (GTL) w100: J500.2@5443.7,101.2 5460,117.5 5460,395 5515,450 6460.11,450 6705.62,695.51 6705.62,851.06 6734.56,880 J3.1@6896.57,880 J3.1@6897.17,880
  L8-Bottom Layer (GBL) w50: v10@5614.7,1373 v10(5614.7,1596.3)
  L8-Bottom Layer (GBL) w100: J500.2@5443.7,101.2 5443.7,178.7 5567.32,302.32 v14(5567.32,1145.88)
VIN3: J500.3 JP4.5 | length 3508.7
  L1-Top Layer (GTL) w30: JP4.5@4560.3,2447.6 5639.4,2447.6 5680,2407 5680,1677 v8(5711,1646)
  L8-Bottom Layer (GBL) w30: J500.3@5581.7,101.2 5711,230.5 v8(5711,1646)
VUSB: C134.2 S6.3 S6.4 U8.66 | length 2383.6
  L1-Top Layer (GTL) w11: S6.4@865.1,285.45 v3(967.14,285.45) ; U8.66@1407.95,730.43 1454.13,730.43 1477.71,706.85 1515.15,706.85 1530,692 v3(1530,532)
  L1-Top Layer (GTL) w20: v16(415.7,285.89) S6.3@505.34,285.89 ; S6.3@530,285 S6.4@850,285 ; v16(689.47,961.41) C134.2@689.47,1022.72
  L8-Bottom Layer (GBL) w11: v3(967.14,285.45) 1213.69,532 v3(1530,532)
  L8-Bottom Layer (GBL) w20: v16(415.7,285.89) 544,414.19 544,916.14 589.27,961.41 v16(689.47,961.41)
XO1_P: R40.1 R41.2 R42.2 | length 79.6
  L1-Top Layer (GTL) w11: R41.2@3479,3383.4 R42.2@3479,3423 R40.1@3479,3463
XO2_P: C70.2 C71.1 R41.1 | length 84.3
  L1-Top Layer (GTL) w11: C70.2@3479,3239.05 R41.1@3479,3323.4
XO3: C71.2 R43.2 R46.1 R47.1 R48.1 R49.1 R50.1 | length 286.9
  L1-Top Layer (GTL) w11: C71.2@3539,3282.4 C71.2@3540.81,3284.21 ; C71.2@3539,3284.21 C71.2@3540.81,3284.21 ; C71.2@3541.1,3284.5 C71.2@3540.81,3284.21 ; R43.2@3822.94,3284.21 3720.85,3284.21 3631.08,3284.21 C71.2@3540.81,3284.21
XO_P: R40.2 U1.9 | length 1763.3
  L1-Top Layer (GTL) w7: U1.9@3493.18,5273.62 3493.18,5221.24 v18(3501.36,5213.06)
  L1-Top Layer (GTL) w11: R40.2@3479,3523 v4(3479,3559)
  L6-Mid-Layer 5 (G4) w5: v4(3479,3559) 3479,4749 3493.24,4763.24 3493.24,5204.94 v18(3501.36,5213.06)
pads on no net: D8.2 FID1.1 FID2.1 FID3.1 FID4.1 FID5.1 FID6.1 J41.4 J41.10 J41.11 J42.1 J42.2 J42.3 J42.5 J42.7 J42.9 J42.10 J42.21 J42.22 J42.23 J42.24 J42.25 J42.29 J42.30 MH1.1 SH1.0 SH2.0 SH4.0 SH5.0 SH6.0 U1.6 U1.42 U1.43 U1.45 U1.46 U1.60 U1.61 U1.62 U1.63 U4.2 U4.5 U6.2 U6.5 U7.2 U7.5 U8.5 U8.6 U8.7 U8.8 U8.12 U8.13 U8.16 U8.17 U8.22 U8.24 U8.25 U8.26 U8.27 U8.28 U8.30 U8.31 U8.32 U8.34 U8.35 U8.36 U8.39 U8.40 U8.41 U8.43 U8.44 U8.48 U8.53 U8.54 U8.55 U8.56 U8.71 U8.72 U8.73 U8.74 U8.75 U8.77 U8.78 U8.79 U8.80 U500.5 Y1.1 Y1.2 Y1.3 Y1.6 Y1.7 Y1.10 Y5.1 Y5.2 Y5.5 Y5.6
copper on no net:
  other v13: 6349,88.56 6264.61,137.28 6433.39,137.28 6264.61,234.72 6433.39,234.72 6349,283.44

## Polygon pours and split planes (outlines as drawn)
GND on L8-Bottom Layer (GBL) "L8-BOTTOM_LAYER_(GBL)_GND_P026" (solid, remove dead copper, pour order 26): 16,9145 6982,9145 6982,20 6895,20 16,20
GND on L8-Bottom Layer (GBL) "L8-BOTTOM_LAYER_(GBL)_GND_P010" (solid, pour order 10): 3469.7,5245.81 3470.28,5246.39 3522.13,5246.39 3522.13,5237.74 3560.73,5199.14 3560.73,3516.13 3541.72,3497.12 3412.66,3497.12 3385.58,3524.2 3402.29,3540.91 3402.29,5225.64 3424.19,5247.54 3457.6,5247.54 3458.55,5246.59 3469.95,5246.59
GND on L3-Mid-Layer 2 (G1) "L3-MID-LAYER_2_(G1)_GND_P028" (solid, remove dead copper, pour order 28): 16,9145 6982,9145 6982,20 6895,20 16,20
VDD_PLANE on L3-Mid-Layer 2 (G1) "L3-MID-LAYER_2_(G1)_VDD_PLANE_P002" (solid, pour order 2): 5056,858 4426,858 4311,973 4311,6103 4298,6116 4298,6694 3792.9,6694 3792.9,6770.66 4298,6764 4383,6849 4846,6849 4859,6849 4908,6813 4908,1295 5011,1209 5140.5,1110 5140.5,942.5
VDDO_PLANE on L3-Mid-Layer 2 (G1) "L3-MID-LAYER_2_(G1)_VDDO_PLANE_P000" (solid, pour order 0): 1939.1,1280.49 1962.55,1257.04 3786.97,1257.04 4294,964 4417.9,842.1 5095.48,851.64 5176.71,932.87 5176.71,1123 4948.63,1288.64 4889.12,1369 4889.12,1669.98 4889.12,1819.84 4996.99,1927.71 5592.62,1927.71 5372.19,860.54 5129,347.18 5095.48,347.18 2276.78,347.18 1922.21,701.75 1922.21,1225.43
GND on L7-Mid-Layer 6 (G5) "L7-MID-LAYER_6_(G5)_GND_P024" (solid, remove dead copper, pour order 24): 16,9145 6982,9145 6982,20 6895,20 16,20
GND on L4-Mid-Layer 3 (G2) "L4-MID-LAYER_3_(G2)_GND_P018" (solid, remove dead copper, pour order 18): 16,9145 6982,9145 6982,20 6895,20 16,20
GND on L5-Mid-Layer 4 (G3) "L5-MID-LAYER_4_(G3)_GND_P020" (solid, remove dead copper, pour order 20): 16,9145 6982,9145 6982,20 6895,20 16,20
GND on L6-Mid-Layer 5 (G4) "L6-MID-LAYER_5_(G4)_GND_P022" (solid, remove dead copper, pour order 22): 16,9145 6982,9145 6982,20 6895,20 16,20
GND on L1-Top Layer (GTL) "L1-TOP_LAYER_(GTL)_GND_P016" (solid, remove dead copper, pour order 16): 16,9145 6982.2,9145 6982.2,20.8 16,20.8
GND on L2-GND Plane (GP1) (split plane): 6979.9,8165 6790,8165 6790,8060 6979.9,8060 6979.9,7665 6790,7665 6790,7560 6979.9,7560 6979.9,7165 6790,7165 6790,7060 6979.9,7060 6979.9,6665 6790,6665 6790,6560 6979.9,6560 6979.9,6165 6790,6165 6790,6060 6979.9,6060 6979.9,5665 6790,5665 6790,5560 6979.9,5560 6979.9,5165 6790,5165 6790,5060 6979.9,5060 6979.9,4665 6790,4665 6790,4560 6979.9,4560 6979.9,4165 6790,4165 6790,4060 6979.9,4060 6979.9,3665 6790,3665 6790,3560 6979.9,3560 6979.9,3165 6790,3165 6790,3060 6979.9,3060 6979.9,2665 6790,2665 6790,2560 6979.9,2560 6979.9,20.1 20.1,20.1 20.1,2560 210,2560 210,2665 20.1,2665 20.1,3060 210,3060 210,3165 20.1,3165 20.1,3560 210,3560 210,3665 20.1,3665 20.1,4060 210,4060 210,4165 20.1,4165 20.1,6560 210,6560 210,6665 20.1,6665 20.1,7060 210,7060 210,7165 20.1,7165 20.1,7560 210,7560 210,7665 20.1,7665 20.1,8060 210,8060 210,8165 20.1,8165 20.1,9140.9 695,9140.9 695,8951 800,8951 800,9140.9 1195,9140.9 1195,8951 1300,8951 1300,9140.9 1695,9140.9 1695,8951 1800,8951 1800,9140.9 2195,9140.9 2195,8951 2300,8951 2300,9140.9 4695,9140.9 4695,8951 4800,8951 4800,9140.9 5195,9140.9 5195,8951 5300,8951 5300,9140.9 5695,9140.9 5695,8951 5800,8951 5800,9140.9 6195,9140.9 6195,8951 6300,8951 6300,9140.9 6979.9,9140.9

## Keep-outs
Keep-Out Layer:
  text ".Layer_Name" at 577,-1758.49 h60

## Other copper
L1-Top Layer (GTL):
  rectangle net +12V: 6345.8,1478.8 6375.4,1515.7
  rectangle net GND: 6169.5,1351.9 6310.9,1627.4
  rectangle net GND: 6167.6,1085.3 6335.4,1315.1
  region net GND: 6183,8971 6183,9139 6165,9139 6165,8971
  region net GND: 6330,8971 6330,9139 6312,9139 6312,8971
  region net GND: 5683,8971 5683,9139 5665,9139 5665,8971
  region net GND: 5830,8971 5830,9139 5812,9139 5812,8971
  region net GND: 5183,8971 5183,9139 5165,9139 5165,8971
  region net GND: 5330,8971 5330,9139 5312,9139 5312,8971
  region net GND: 4683,8971 4683,9139 4665,9139 4665,8971
  region net GND: 4830,8971 4830,9139 4812,9139 4812,8971
  region net GND: 2183,8971 2183,9139 2165,9139 2165,8971
  region net GND: 2330,8971 2330,9139 2312,9139 2312,8971
  region net GND: 1830,8971 1830,9139 1812,9139 1812,8971
  region net GND: 1683,8971 1683,9139 1665,9139 1665,8971
  region net GND: 1330,8971 1330,9139 1312,9139 1312,8971
  region net GND: 1183,8971 1183,9139 1165,9139 1165,8971
  region net GND: 830,8971 830,9139 812,9139 812,8971
  region net GND: 683,8971 683,9139 665,9139 665,8971
  region net GND: 190,8195 22,8195 22,8177 190,8177
  region net GND: 190,8048 22,8048 22,8030 190,8030
  region net GND: 190,7695 22,7695 22,7677 190,7677
  region net GND: 190,7548 22,7548 22,7530 190,7530
  region net GND: 190,7195 22,7195 22,7177 190,7177
  region net GND: 190,7048 22,7048 22,7030 190,7030
  region net GND: 190,6695 22,6695 22,6677 190,6677
  region net GND: 190,6548 22,6548 22,6530 190,6530
  region net GND: 190,4195 22,4195 22,4177 190,4177
  region net GND: 190,4048 22,4048 22,4030 190,4030
  region net GND: 190,3695 22,3695 22,3677 190,3677
  region net GND: 190,3548 22,3548 22,3530 190,3530
  region net GND: 190,3195 22,3195 22,3177 190,3177
  region net GND: 190,3048 22,3048 22,3030 190,3030
  region net GND: 190,2695 22,2695 22,2677 190,2677
  region net GND: 190,2548 22,2548 22,2530 190,2530
  rectangle net GND: 6810,2677 6978,2695
  rectangle net GND: 6810,2530 6978,2548
  rectangle net GND: 6810,3177 6978,3195
  rectangle net GND: 6810,3030 6978,3048
  rectangle net GND: 6810,3677 6978,3695
  rectangle net GND: 6810,3530 6978,3548
  rectangle net GND: 6810,4177 6978,4195
  rectangle net GND: 6810,4030 6978,4048
  rectangle net GND: 6810,4677 6978,4695
  rectangle net GND: 6810,4530 6978,4548
  rectangle net GND: 6810,5177 6978,5195
  rectangle net GND: 6810,5030 6978,5048
  rectangle net GND: 6810,5677 6978,5695
  rectangle net GND: 6810,5530 6978,5548
  rectangle net GND: 6810,6177 6978,6195
  rectangle net GND: 6810,6030 6978,6048
  rectangle net GND: 6810,6677 6978,6695
  rectangle net GND: 6810,6530 6978,6548
  rectangle net GND: 6810,7177 6978,7195
  rectangle net GND: 6810,7030 6978,7048
  rectangle net GND: 6810,7677 6978,7695
  rectangle net GND: 6810,7530 6978,7548
  rectangle net GND: 6810,8030 6978,8048
  rectangle net GND: 6810,8177 6978,8195
  rectangle net GND: 976,1057.5 986,1128
  region net GND: 986,1118 986,1128 915.5,1128 915.5,1118
  rectangle net GND: 934.46,1086.62 944.46,1125.38
  rectangle net GND: 915.5,1118 925.5,1243
  region net VDDGPIO: 4528.19,1046 4407,1046 4407,939 4528.19,939
  region net GND: 5171.24,1372.03 5061.24,1372.03 5061.24,1307.03 5171.24,1307.03
  region net VDD_PLANE: 5121.85,951.11 5121.85,1071.11 4808.84,1071.11 4808.84,951.11
  region net VDD_PLANE: 4824,1098 4678.19,1098 4678.19,947.87 4824,947.87
  rectangle net VDDO_PLANE: 4897.76,1416.84 5010.03,1671.09
  rectangle net VDDO_PLANE: 4982.7,1410.43 5300.5,1677
  rectangle net VCC_XO: 3990.9,2206.8 4376.5,2682.8
  region net LDO3_IN: 6116.1,892.8 6116.1,634.9 6184.07,634.9 6184.07,892.8
  rectangle net VDD_PLANE: 5035.4,825.2 5215.8,1118.4
  rectangle net GND: 6198.6,1305.2 6334.8,1395.9
  rectangle net GND: 6240.4,1376.4 6334.3,1458.1
  rectangle net GND: 6113.6,918.5 6335.8,1086.45
  rectangle net GND: 6300.8,1455.9 6333.7,1515.4
  rectangle net GND: 6293.2,1512.4 6333.1,1583.3
  rectangle net NetC504_1: 6461.6,1538.3 6544.2,1595.1
  rectangle net +12V: 6384.5,1393.2 6506.6,1456.6
  rectangle net +12V: 6357.8,1447.1 6438.3,1501.2
  rectangle net NetC501_1: 6165.4,1635.5 6205.5,1837.3
  rectangle net NetC501_1: 6098.8,1635.5 6165.4,1807.3
  rectangle net NetC504_1: 6030.1,1099.6 6158.4,1343.1
  rectangle net NetR500_1: 6523.7,1408.6 6611.1,1460.6
  rectangle net NetL501_1: 6300.5,1669.4 6398.7,1836.8
  rectangle net GND: 6610.6,1581.6 6641.7,1699.6
  rectangle net +12V: 6428.4,1454.3 6456.12,1474.9
  rectangle net +12V: 6345.7,1017.5 6608.6,1398.5
  rectangle net +12V: 6345.7,945.5 6535.9,1017.5
  rectangle net +12V: 6526.5,990.1 6580.5,1017.5
  rectangle net +12V: 6533.7,970 6560.4,993.7
  pour cut-out: 7.28,8045.58 7.33,8045.52 7.33,8047.82 15.09,8055.58 16,8055.58 16,8041.8 12.63,8045.17 7.33,8045.17
  region net NetC501_1: 6323,1636 6323,1649.1 6315.57,1660.6 6292.5,1660.6 6292.5,1837.4 6205.5,1837.3 6205.5,1636
  region net GND: 6559.9,1584.1 6562.9,1584.1 6641.9,1584.1 6641.9,1534.2 6577,1469.3 6523.8,1469.3 6523.8,1527.4 6523.8,1529 6559.9,1529
  pour cut-out: 1232.71,966.85 1092.71,966.85 1092.71,346.85 1232.71,346.85
  pour cut-out: 49.33,977.57 386.64,977.57 386.64,482.43 385.07,484 50,484 49,483
  text ".Layer_Name" at 326,-1754.49 h60
L3-Mid-Layer 2 (G1):
  region net VDDO_PLANE: 5057,5403 5057,5559.89 4949.42,5559.89 4949.42,5403
  rectangle net VDD_PLANE: 3479.57,6284.54 3587,6395.68
  rectangle net VDD_PLANE: 3093.99,6175 3234.63,6260.55
  rectangle net VDD_PLANE: 3546.24,4418.92 3681.22,4518.4
  region net VDD_PLANE: 4415.86,5123.23 4415.86,5280.12 4308.28,5280.12 4308.28,5123.23
  rectangle net VDD_PLANE: 3627.9,6555.98 3758.8,6667.12
  region net VDDO_PLANE: 2524.4,5608.78 2524.4,5501.35 2635.54,5501.35 2635.54,5608.78
  region net VDDO_PLANE: 2790.48,4686.93 2859.74,4756.2 2758.64,4857.3 2689.38,4788.04
  rectangle net VDDO_PLANE: 3234.71,4312.18 3369.69,4411.66
  pour cut-out: 153 vertices and 0 holes, not listed, extent -200,-200 7200,9361
  pour cut-out: 4016.89,5353.45 4016.89,5309.45 3980.89,5309.45 3980.89,5353.45
  pour cut-out: 3920.84,5508.22 3920.84,5464.22 3884.84,5464.22 3884.84,5508.22
  pour cut-out: 2871.91,5666.42 2903.02,5697.53 2928.48,5672.07 2897.37,5640.96
  pour cut-out: 2988.06,5721.27 3019.17,5752.38 3044.63,5726.92 3013.52,5695.81
  text ".Layer_Name" at 326,-1754.49 h60
L4-Mid-Layer 3 (G2):
  pour cut-out: 695,9261 695,8951 800,8951 800,9261 1195,9261 1195,8951 1300,8951 1300,9261 1695,9261 1695,8951 1800,8951 1800,9261 2195,9261 2195,8951 2300,8951 2300,9261 2695,9261 2800,9261 3195,9261 3300,9261 3695,9261 3800,9261 4195,9261 4300,9261 4695,9261 4695,8951 4800,8951 4800,9261 5195,9261 5195,8951 5300,8951 5300,9261 5695,9261 5695,8951 5800,8951 5800,9261 6195,9261 6195,8951 6300,8951 6300,9261 7100,9261 7100,2665 6790,2665 6790,2560 7100,2560 7100,3165 6790,3165 6790,3060 7100,3060 7100,3665 6790,3665 6790,3560 7100,3560 7100,4165 6790,4165 6790,4060 7100,4060 7100,4665 6790,4665 6790,4560 7100,4560 7100,5165 6790,5165 6790,5060 7100,5060 7100,5665 6790,5665 6790,5560 7100,5560 7100,6165 6790,6165 6790,6060 7100,6060 7100,6665 6790,6665 6790,6560 7100,6560 7100,7165 6790,7165 6790,7060 7100,7060 7100,7665 6790,7665 6790,7560 7100,7560 7100,8165 6790,8165 6790,8060 7100,8060 7100,-100 -100,-100 -100,8060 210,8060 210,8165 -100,8165 -100,7560 210,7560 210,7665 -100,7665 -100,7060 210,7060 210,7165 -100,7165 -100,6560 210,6560 210,6665 -100,6665 -100,6060 -100,6165 -100,5560 -100,5665 -100,5060 -100,5165 -100,4560 -100,4665 -100,4060 210,4060 210,4165 -100,4165 -100,3560 210,3560 210,3665 -100,3665 -100,3060 210,3060 210,3165 -100,3165 -100,2560 210,2560 210,2665 -100,2665 -200,9361 -200,-200 7200,-200 7200,9361 -200,9361
  pour cut-out: 2988.06,5721.27 3019.17,5752.38 3044.63,5726.92 3013.52,5695.81
  pour cut-out: 2871.91,5666.42 2903.02,5697.53 2928.48,5672.07 2897.37,5640.96
  pour cut-out: 3920.84,5508.22 3920.84,5464.22 3884.84,5464.22 3884.84,5508.22
  pour cut-out: 4016.89,5353.45 4016.89,5309.45 3980.89,5309.45 3980.89,5353.45
  text ".Layer_Name" at 321,-1754.49 h60
L5-Mid-Layer 4 (G3):
  pour cut-out: 2988.06,5721.27 3019.17,5752.38 3044.63,5726.92 3013.52,5695.81
  pour cut-out: 2871.91,5666.42 2903.02,5697.53 2928.48,5672.07 2897.37,5640.96
  pour cut-out: 3920.84,5508.22 3920.84,5464.22 3884.84,5464.22 3884.84,5508.22
  pour cut-out: 4016.89,5353.45 4016.89,5309.45 3980.89,5309.45 3980.89,5353.45
  text ".Layer_Name" at 321,-1754.49 h60
L6-Mid-Layer 5 (G4):
  pour cut-out: 4016.89,5353.45 4016.89,5309.45 3980.89,5309.45 3980.89,5353.45
  pour cut-out: 3920.84,5508.22 3920.84,5464.22 3884.84,5464.22 3884.84,5508.22
  pour cut-out: 2871.91,5666.42 2903.02,5697.53 2928.48,5672.07 2897.37,5640.96
  pour cut-out: 2988.06,5721.27 3019.17,5752.38 3044.63,5726.92 3013.52,5695.81
L7-Mid-Layer 6 (G5):
  pour cut-out: 2988.06,5721.27 3019.17,5752.38 3044.63,5726.92 3013.52,5695.81
  pour cut-out: 2871.91,5666.42 2903.02,5697.53 2928.48,5672.07 2897.37,5640.96
  pour cut-out: 3920.84,5508.22 3920.84,5464.22 3884.84,5464.22 3884.84,5508.22
  pour cut-out: 4016.89,5353.45 4016.89,5309.45 3980.89,5309.45 3980.89,5353.45
L8-Bottom Layer (GBL):
  rectangle net LDO3_IN: 6485.2,1937.4 6526.2,2099.4
  rectangle net VBUS: 255,801 372,849
  rectangle net LDO2: 6240.2,1937.4 6295.2,1985.4
  region net LDO3_IN: 5968.2,2127.4 5968.2,2168.4 5880.2,2168.4 5880.2,2127.4
  region net LDO1: 5966.2,1893.4 5966.2,1941.4 5865.2,1941.4 5865.2,1893.4
  rectangle net LDO3: 4920,2838 4981,2942
  rectangle net LDO3_IN: 5166,2836 5228,2966
  text ".Layer_Name" at 321,-1754.49 h60
L2-GND Plane (GP1) (plane layer: these items are gaps in the copper):
  region: 3044.67,5727.19 3019.22,5752.65 2988.1,5721.54 3013.56,5696.08
  region: 2928.52,5672.34 2903.06,5697.8 2871.95,5666.68 2897.41,5641.23
  region: 4016.73,5353.67 3980.73,5353.67 3980.73,5309.67 4016.73,5309.67
  rectangle: 3885,5464 3921,5508
  pour cut-out: 3779.16,5891.79 3809.16,5921.79 3873.57,5857.38 3843.57,5827.38
  pour cut-out: 3631.8,5979.2 3661.8,6009.2 3726.2,5944.8 3696.2,5914.8
  pour cut-out: 3666.71,5927.74 3686.21,5908.24 3633.82,5855.85 3614.32,5875.35
  pour cut-out: 3624.01,5969.16 3643.51,5949.66 3591.12,5897.28 3571.62,5916.78
  pour cut-out: 3759.21,6105.24 3778.71,6085.74 3726.32,6033.35 3706.82,6052.85
  pour cut-out: 3803.21,6063.24 3822.71,6043.74 3770.32,5991.35 3750.82,6010.85
  pour cut-out: 3907.34,6014.08 3926.84,5994.58 3874.45,5942.19 3854.95,5961.69
  pour cut-out: 3950.79,5973.61 3970.29,5954.11 3917.9,5901.72 3898.4,5921.22
  pour cut-out: 3794.4,5813.9 3813.9,5794.4 3761.51,5742.01 3742.01,5761.51
  pour cut-out: 3749.04,5859.04 3768.54,5839.54 3716.15,5787.15 3696.65,5806.65
  pour cut-out: 391,8131.5 391,8095.5 312,8095.5 312,8131.5
  pour cut-out: 390,7632 390,7595 313,7595 313,7632
  pour cut-out: 390,7130.5 390,7095.5 312,7095.5 312,7130.5
  pour cut-out: 389,6632 389,6593 313,6593 313,6632
  pour cut-out: 389,4132 389,4093 313,4093 313,4132
  pour cut-out: 390.5,3632 390.5,3592 311.5,3592 311.5,3632
  pour cut-out: 389,3132 389,3093 313,3093 313,3132
  pour cut-out: 389,2632 389,2593 313,2593 313,2632
  pour cut-out: 6606,2593 6606,2632 6685,2632 6685,2593
  pour cut-out: 6607,3092 6607,3132 6685,3132 6685,3092
  pour cut-out: 6608,3593 6608,3633 6686,3633 6686,3593
  pour cut-out: 6608,4093 6608,4133 6686,4133 6686,4093
  pour cut-out: 6608.04,4592 6608.04,4633.5 6686,4633.5 6686,4592
  pour cut-out: 6608,5093 6608,5133 6685,5133 6685,5093
  pour cut-out: 6609,5591 6609,5633 6685,5633 6685,5591
  pour cut-out: 6608,6092 6608,6133 6685,6133 6685,6092
  pour cut-out: 6608,6592 6608,6632 6686,6632 6686,6592
  pour cut-out: 6606,7092 6606,7132 6686,7132 6686,7092
  pour cut-out: 6608,7593 6608,7632 6685,7632 6685,7593
  pour cut-out: 6609,8092 6609,8133 6685,8133 6685,8092
  pour cut-out: 2267,8771 2228,8771 2228,8848 2267,8848
  pour cut-out: 1768,8771 1727,8771 1727,8849 1768,8849
  pour cut-out: 1267,8771 1228,8771 1228,8848 1267,8848
  pour cut-out: 766,8770 729.5,8770 729.5,8848 766,8848
  pour cut-out: 695,9261 695,8951 800,8951 800,9261 1195,9261 1195,8951 1300,8951 1300,9261 1695,9261 1695,8951 1800,8951 1800,9261 2195,9261 2195,8951 2300,8951 2300,9261 2695,9261 2800,9261 3195,9261 3300,9261 3695,9261 3800,9261 4195,9261 4300,9261 4695,9261 4695,8951 4800,8951 4800,9261 5195,9261 5195,8951 5300,8951 5300,9261 5695,9261 5695,8951 5800,8951 5800,9261 6195,9261 6195,8951 6300,8951 6300,9261 7100,9261 7100,2665 6790,2665 6790,2560 7100,2560 7100,3165 6790,3165 6790,3060 7100,3060 7100,3665 6790,3665 6790,3560 7100,3560 7100,4165 6790,4165 6790,4060 7100,4060 7100,4665 6790,4665 6790,4560 7100,4560 7100,5165 6790,5165 6790,5060 7100,5060 7100,5665 6790,5665 6790,5560 7100,5560 7100,6165 6790,6165 6790,6060 7100,6060 7100,6665 6790,6665 6790,6560 7100,6560 7100,7165 6790,7165 6790,7060 7100,7060 7100,7665 6790,7665 6790,7560 7100,7560 7100,8165 6790,8165 6790,8060 7100,8060 7100,-100 -100,-100 -100,8060 210,8060 210,8165 -100,8165 -100,7560 210,7560 210,7665 -100,7665 -100,7060 210,7060 210,7165 -100,7165 -100,6560 210,6560 210,6665 -100,6665 -100,6060 -100,6165 -100,5560 -100,5665 -100,5060 -100,5165 -100,4560 -100,4665 -100,4060 210,4060 210,4165 -100,4165 -100,3560 210,3560 210,3665 -100,3665 -100,3060 210,3060 210,3165 -100,3165 -100,2560 210,2560 210,2665 -100,2665 -200,9361 -200,-200 7200,-200 7200,9361 -200,9361

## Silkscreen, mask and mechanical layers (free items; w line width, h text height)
Top Overlay:
  region: 3844.77,1188.55 3844.77,1428.55 4766.21,1428.55 4766.21,1188.55
  lines w10: 1190.12,1393.2 1202.12,1381.2 1354.12,1381.2 1366.05,1393.13 ; 1504.2,1393.9 1516.03,1382.07 1866.1,1382.07 ; 1866.6,1383.2 1877.3,1393.9 ; 1961.4,1693.4 1976.4,1678.4 ; 1961.4,1853.4 1976.4,1868.4 ; 1976.4,1758.4 1976.4,1678.4 ; 1976.4,1788.4 1976.4,1868.4 ; 1991.4,1693.4 1976.4,1678.4 ; 1991.4,1853.4 1976.4,1868.4 ; 5459,2811.9 5461.2,2445.5 ; 5812.7,2224.8 5813.3,2416.3 ; 6072.4,2006.8 6073,2198.3
  text "Default DC  / coupled" at 243.7,3793.4 h72.83
  text "XO_P" at 3074.8,2938.87 h100
  text "APLL1 LDO" at 4475.8,2937.7 h40
  text "APLL2 LDO" at 4766.5,2937.7 h40
  text "GND" at 4616.07,2667.88 h55
  text "LDO3 INPUT" at 5137.3,2658.5 h55
  text "LMK LDO to XO" at 4616.07,2570.56 h55
  text "I2C Address" at 2059,2479 h65
  text "VIN3 DIRECT" at 4616.07,2473.24 h55
  text "XO VDD" at 4020.2,2451.1 h55
  text "Power DUT directly: / VIN1 (VDD) = 3.3 V (1 A) / VIN2 (VDDO) = 3.3 V (1 A) / VIN3 (XO_VDD) = 3.3 V (1A) / VIN4 not used." at 5473,2447.6 h80
  text "LDO       to XO" at 4616.07,2386 h55
  text "GPIO2" at 2733.12,2365.21 h70
  text "DC/DC to XO" at 4616.07,2278.6 h55
  text "VDD" at 3105.27,2248.13 h65
  text "Power DUT with LDO: / VIN1 = 3.6 V to 5 V (2 A) / VIN2, VIN3, VIN4 not used." at 5834,2213.5 h80
  text "USB2ANY" at 3105.27,2150.6 h65
  text "GND" at 3105.27,2052.15 h65
  text "Power DUT with DCDC: / VIN4 = 10 V to 15 V (1 A) / VIN1, VIN2, VIN3 not used." at 6087.3,1995.7 h80
  text "LED" at 3105.27,1953.13 h65
  text "DUT" at 2034.46,1786.11 h50 r90
  text "MCU" at 2034.24,1671.11 h50 r90
  text "VIN2 DIRECT" at 5492.2,1667 h55
  text "GPIO1" at 2748.52,1594.74 h70
  text "LDO    to VDDO" at 5489.1,1567.6 h55
  text "VDDO" at 5725.1,1491.8 h55
  text "to" at 5665.4,1486.5 h55
  text "DC/DC" at 5499.1,1478 h55
  text "USER NOTE:" at 3838,1473 h100
  text "VDD" at 3105.27,1469.13 h65
  text "SDA" at 1243,1395.3 h65 r90
  text "SCL" at 1345.7,1395.3 h65 r90
  text "GND" at 1440.7,1395.3 h65 r90
  text "SCK" at 1552.2,1394.2 h65 r90
  text "MISO" at 1750,1394.2 h65 r90
  text "SCS" at 1848.9,1394.2 h65 r90
  text "MOSI" at 1677.2,1392.5 h65 r90
  text "USB2ANY" at 3105.27,1376.6 h65
  text "I2C" at 1235.7,1296.18 h100
  text "SPI" at 1640.7,1296.27 h100
  text "GND" at 3105.27,1278.15 h65
  text "LED" at 3105.27,1179.13 h65
  text "VIN1 DIRECT" at 4816.7,1090.4 h55
  text "LDO to VDD" at 4841.9,994.5 h55
  text "DC/DC to VDD" at 4792.7,865 h55
  text "GPIO0" at 2760.92,845.74 h70
  text "VDD" at 3105.27,724.13 h65
  text "USB2ANY" at 3105.27,626.6 h65
  text "GND" at 3105.27,528.15 h65
  text "LED" at 3105.27,429.13 h65
  text "PWR" at 4962.4,362.5 h100
  text "VIN4" at 5744.7,302 h75 r90
  text "VIN3" at 5610.5,300.3 h75 r90
  text "VIN1" at 5340.5,298.6 h75 r90
  text "VIN2" at 5478.1,298.6 h75 r90
  text "GND" at 5889.1,296.9 h75 r90
  text ".Layer_Name" at 324,-1754 h100
Bottom Overlay:
  text ".Layer_Name" at 577,-1758.49 h50
Top Paste:
  text ".Layer_Name" at 577,-1758.49 h60
Bottom Paste:
  text ".Layer_Name" at 321,-1754.49 h60
Top Solder:
  circle w30: c3194,4708 r1
  circle w30: c3495,4839 r1
  circle w30: c4052,5003 r1
  circle w30: c4078,5447 r1
  circle w30: c3614,6032 r1
  circle w30: c3395,6066 r1
  circle w30: c3111,5924 r1
  circle w30: c3050,5854 r1
  circle w30: c2739.9,5666.3 r1
  circle w30: c2827,4962 r1
  circle w30: c3738,6246 r1
  circle w30: c3966,6408 r1
  circle w30: c4103,5394 r1
  circle w30: c4080,5121 r1
  text ".Layer_Name" at 577,-1758.49 h60
Bottom Solder:
  region: 3335,5300 3631,5300 3631,5593 3335,5593
  text ".Layer_Name" at 321,-1754.49 h60
Drill Guide:
  text ".Layer_Name" at 321,-1754.49 h60
  text ".Layer_Name" at 577,-1758.49 h60
M1 Board Outline:
  the board outline again, w5
  text ".Layer_Name" at 577,-1758.49 h60
M3 3D STEP Top:
  text ".Layer_Name" at 321,-1754.49 h60
  text ".Layer_Name" at 577,-1758.49 h60
M4 3D STEP Bottom:
  text ".Layer_Name" at 321,-1754.49 h60
  text ".Layer_Name" at 577,-1758.49 h60
M5 Assembly Top:
  lines w10: -292,-1830.17 6308,-1830.17 ; -292,-1626.83 6310,-1626.83 ; -292,-1423.5 -292,-2033.5 3713,-2033.5 6310,-2033.5 6310,-1423.5 -291.5,-1423.5 -291.5,-2033.5 1284,-2033.5 ; 2173,-2033.5 2173,-1423.5 ; 3440,-1626.83 3440,-1423.5 ; 4280,-1626.83 4280,-1423.5 ; 4902,-2040 4902,-1837.17
  text "COMPONENTS MARKED 'DNP' SHOULD NOT BE POPULATED." at 1403.5,-1188.5 h60
  text "ASSEMBLY VARIANT:" at 1403,-1304 h60
  text ".VariantName" at 2439,-1304 h60
  text "PCB VIEWED FROM TOP SIDE" at -228.5,-1555.67 h60
  text "BOARD #:" at 2248,-1555.67 h60
  text ".PRJ_Number" at 2793.5,-1555.67 h60
  text "REV:" at 3638,-1555.67 h60
  text ".PCB_Rev" at 3929.5,-1555.67 h60
  text "SVN REV:" at 4476,-1555.67 h60
  text ".VersionControl_RevNumber" at 4982,-1555.67 h60
  text "TID #:" at 2248,-1759 h60
  text ".TID" at 2793.5,-1759 h60
  text "PLOT NAME =" at -228.5,-1964.34 h60
  text ".plot_File_Name" at 577,-1964.34 h60
  text "GENERATED    :" at 2250,-1964.34 h60
  text ".Print_Date" at 3119.5,-1964.34 h60
  text ".Print_Time" at 3848.5,-1964.34 h60
  text "TEXAS INSTRUMENTS" at 5113,-1964.34 h60
M6 Assembly Bottom:
  lines w10: -292.5,-1627.33 6309.5,-1627.33 ; -290.5,-1830.67 6309.5,-1830.67 ; 1115.5,-2040.5 1115.5,-1837.67 ; 1737.5,-1627.33 1737.5,-1424 ; 2577.5,-1627.33 2577.5,-1424 ; 3844.5,-2034 3844.5,-1424 ; 4733.5,-2034 6309,-2034 6309,-1424 -292.5,-1424 -292.5,-2034 2304.5,-2034 6309.5,-2034 6309.5,-1424
  text "COMPONENTS MARKED 'DNP' SHOULD NOT BE POPULATED." at 6352,-1188 h60
  text ".VariantName" at 5308,-1304 h60
  text "ASSEMBLY VARIANT:" at 6347,-1304 h60
  text ".VersionControl_RevNumber" at 1035.5,-1556.17 h60
  text "SVN REV:" at 1541.5,-1556.17 h60
  text ".PCB_Rev" at 2088,-1556.17 h60
  text "REV:" at 2379.5,-1556.17 h60
  text ".PRJ_Number" at 3224,-1556.17 h60
  text "BOARD #:" at 3769.5,-1556.17 h60
  text "PCB VIEWED FROM BOTTOM SIDE" at 6246,-1556.17 h60
  text "IGNORE ->" at 2289.85,-1754.49 h60
  text ".TID" at 3224,-1759.5 h60
  text "TID #:" at 3769.5,-1759.5 h60
  text "TEXAS INSTRUMENTS" at 904.5,-1964.84 h60
  text ".Print_Time" at 2169,-1964.84 h60
  text ".Print_Date" at 2898,-1964.84 h60
  text "GENERATED    :" at 3767.5,-1964.84 h60
  text ".plot_File_Name" at 5440.5,-1964.84 h60
  text "PLOT NAME =" at 6246,-1964.84 h60
M7 LPKF Text Top:
  text ".Layer_Name" at 321,-1754.49 h60
M9 Title Sheet:
  drawing of 56 lines, arcs and shapes, not listed
  text "1" at 886.34,12299.39 h70
  text "2" at 4212,12299.39 h70
  text "3" at 7542,12299.39 h70
  text "4" at 10877,12299.39 h70
  text "5" at 14202,12299.39 h70
  text "6" at 17537,12299.39 h70
  text "A" at -635,10521.39 h70
  text "B" at -635,6771.39 h70
  text "B" at 19065,6771.39 h70
  text "C" at -635,3021.39 h70
  text "C" at 19065,3021.39 h70
  text "D" at -635,-728.61 h70
  text "D" at 19065,-728.61 h70
  text "PROJECT TITLE:" at 15971,-813.61 h45
  text ".PRJ_Title" at 16021,-946.94 h70
  text "DESIGNED FOR:" at 15971,-1114.61 h45
  text ".PRJ_Customer" at 16021,-1254.61 h70
  text "FILE NAME:" at 15971,-1414.61 h45
  text ".PCB_File_Name_No_Path" at 16021,-1534.61 h70
  text "Texas Instruments (TI) and/or its licensors do not warrant the accuracy or completeness of this specification" at 11001.5,-1696.45 h45
  text "ENGINEER:" at 15971,-1704.61 h45
  text "LAYOUT BY:" at 17476,-1704.61 h45
  text ".Layer_Name" at 415,-1755 h60
  text "or any information contained therein. TI and/or its licensors do not warrant that this design will meet" at 10956.51,-1809.11 h45
  text ".PRJ_Engineer" at 16021,-1859.6 h70
  text ".PCB_Layout" at 17526.5,-1859.6 h70
  text "the specifications, will be suitable for your application or fit for any particular purpose, or will operate in" at 10956.51,-1921.78 h45
  text "ALTIUM DESIGNER VERSION:" at 17476,-2014.61 h45
  text "an implementation. TI and/or its licensors do not warrant that the design is production worthy. You should" at 10956.51,-2034.44 h45
  text "completely validate and test your design implementation to confirm the system functionality for your application." at 11001.5,-2147.11 h45
  text ".print_Scale" at 16021,-2147.94 h70
  text ".Application_BuildNumber" at 17526.5,-2147.94 h70
  text "1" at 886.34,-2400.61 h70
  text "2" at 4212,-2400.61 h70
  text "3" at 7542,-2400.61 h70
  text "4" at 10877,-2400.61 h70
  text "5" at 14202,-2400.61 h70
  text "6" at 17537,-2400.61 h70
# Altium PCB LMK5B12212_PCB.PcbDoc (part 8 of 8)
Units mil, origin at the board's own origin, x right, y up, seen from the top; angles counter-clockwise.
Board outline 7000 x 9161 mil, 8 copper layers (L1-Top Layer (GTL), L2-GND Plane (GP1), L3-Mid-Layer 2 (G1), L4-Mid-Layer 3 (G2), L5-Mid-Layer 4 (G3), L6-Mid-Layer 5 (G4), L7-Mid-Layer 6 (G5), L8-Bottom Layer (GBL)), stack 61.2 mil thick; 469 components, 264 nets, 1268 pads, 1812 vias.

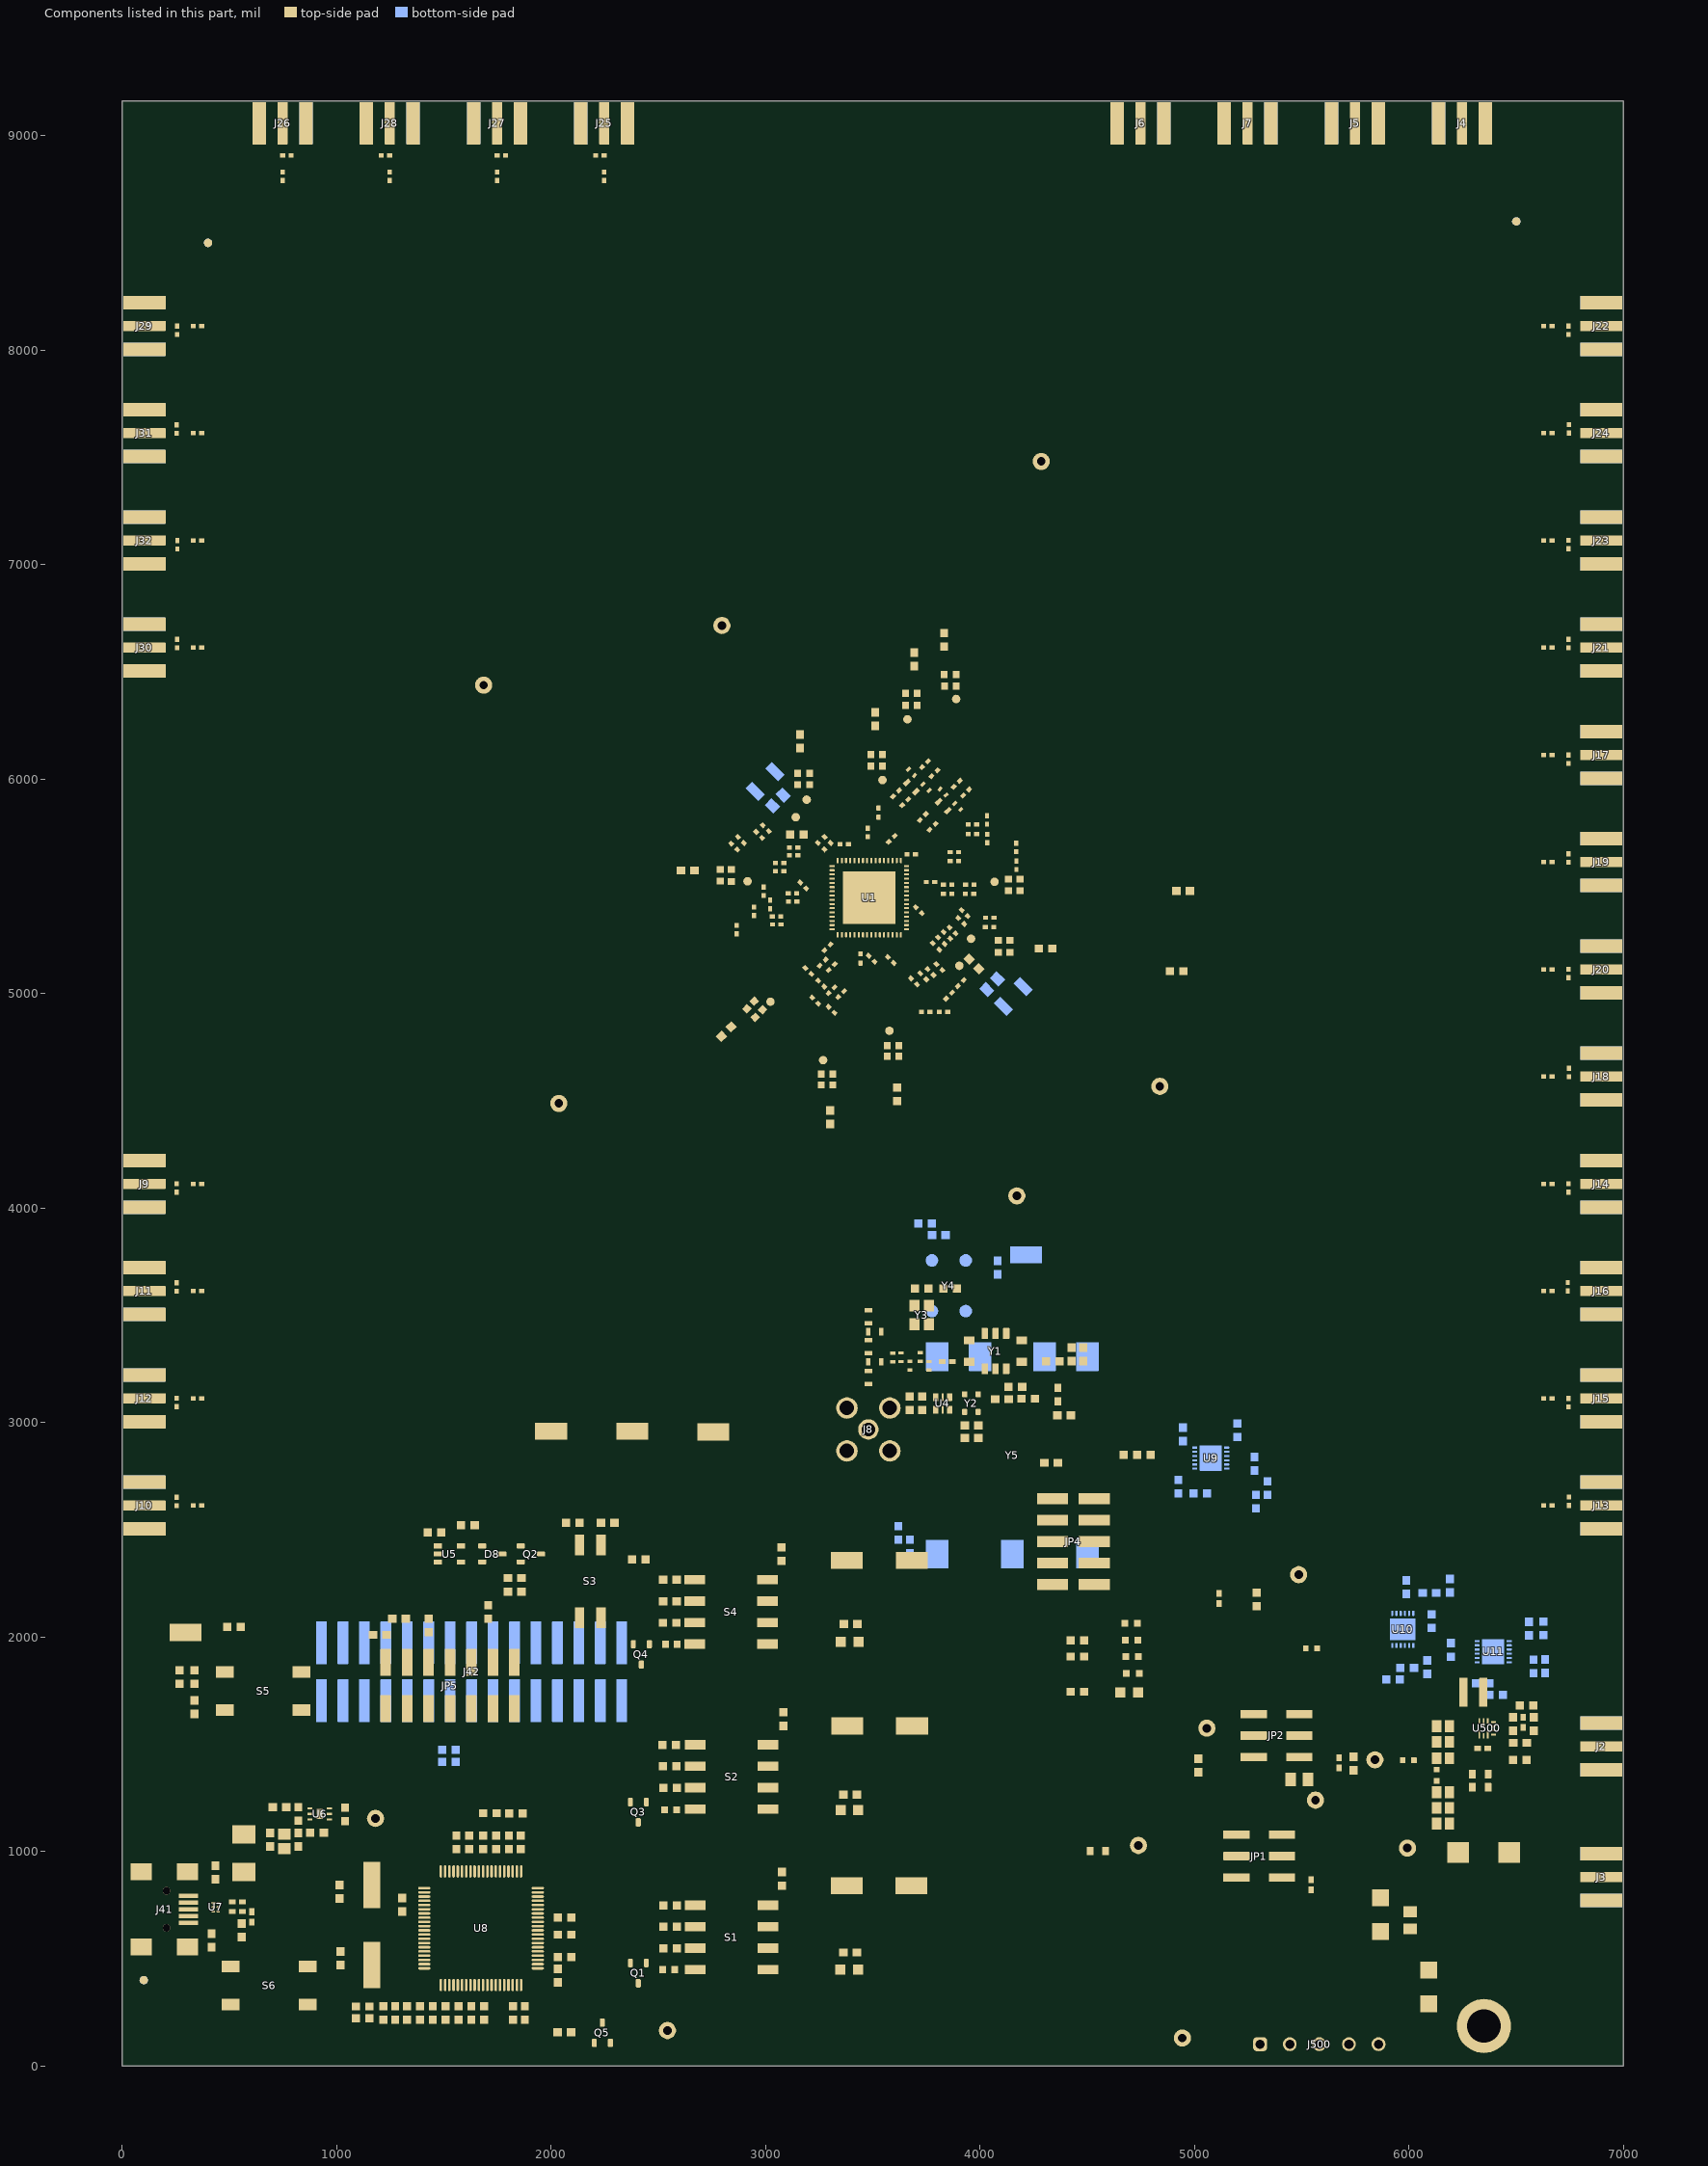
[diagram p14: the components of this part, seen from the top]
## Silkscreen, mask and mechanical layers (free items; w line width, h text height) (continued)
M10 Fab Notes:
  drawing of 203 lines, arcs and shapes, not listed
  text "C" at 16536.76,6898.2 h137.54
  text "o" at 16602.93,6898.2 h137.54
  text "n" at 16669.1,6898.2 h137.54
  text "t" at 16735.27,6898.2 h137.54
  text "r" at 16782.53,6898.2 h137.54
  text "o" at 16829.8,6898.2 h137.54
  text "l" at 16895.97,6898.2 h137.54
  text "l" at 16924.33,6898.2 h137.54
  text "e" at 16952.69,6898.2 h137.54
  text "d" at 17018.86,6898.2 h137.54
  text "I" at 17113.39,6898.2 h137.54
  text "m" at 17141.75,6898.2 h137.54
  text "p" at 17245.73,6898.2 h137.54
  text "e" at 17311.9,6898.2 h137.54
  text "d" at 17378.08,6898.2 h137.54
  text "a" at 17444.25,6898.2 h137.54
  text "n" at 17500.96,6898.2 h137.54
  text "c" at 17567.14,6898.2 h137.54
  text "e" at 17614.4,6898.2 h137.54
  text "L" at 15192.16,6690.23 h137.54
  text "a" at 15248.88,6690.23 h137.54
  text "y" at 15305.6,6690.23 h137.54
  text "e" at 15362.31,6690.23 h137.54
  text "r" at 15428.48,6690.23 h137.54
  text "S" at 15741.36,6690.23 h137.54
  text "i" at 15798.08,6690.23 h137.54
  text "n" at 15826.44,6690.23 h137.54
  text "g" at 15892.61,6690.23 h137.54
  text "l" at 15949.33,6690.23 h137.54
  text "e" at 15977.69,6690.23 h137.54
  text "-" at 16043.86,6690.23 h137.54
  text "E" at 16081.67,6690.23 h137.54
  text "n" at 16138.39,6690.23 h137.54
  text "d" at 16204.56,6690.23 h137.54
  text "e" at 16270.73,6690.23 h137.54
  text "d" at 16336.9,6690.23 h137.54
  text "Ω" at 16726.14,6690.23 h137.54
  text "+" at 17085.96,6690.23 h137.54
  text "/" at 17142.68,6690.23 h137.54
  text "-" at 17199.39,6690.23 h137.54
  text "%" at 17265.57,6690.23 h137.54
  text "R" at 17587.81,6690.23 h137.54
  text "e" at 17653.99,6690.23 h137.54
  text "f" at 17720.16,6690.23 h137.54
  text "e" at 17757.97,6690.23 h137.54
  text "r" at 17824.14,6690.23 h137.54
  text "e" at 17871.41,6690.23 h137.54
  text "n" at 17937.58,6690.23 h137.54
  text "c" at 18003.75,6690.23 h137.54
  text "e" at 18051.01,6690.23 h137.54
  text "L" at 18145.54,6690.23 h137.54
  text "a" at 18202.26,6690.23 h137.54
  text "y" at 18258.98,6690.23 h137.54
  text "e" at 18315.7,6690.23 h137.54
  text "r" at 18381.87,6690.23 h137.54
  text "s" at 18429.13,6690.23 h137.54
  text "L1" at 15303.79,6496.3 h137.54
  text "1" at 15881.4,6496.3 h137.54
  text "1" at 15947.57,6496.3 h137.54
  text "m" at 16013.74,6496.3 h137.54
  text "i" at 16108.27,6496.3 h137.54
  text "l" at 16146.08,6496.3 h137.54
  text "s" at 16183.89,6496.3 h137.54
  text "5" at 16705.2,6496.3 h137.54
  text "0" at 16771.37,6496.3 h137.54
  text "1" at 17150.24,6496.3 h137.54
  text "0" at 17216.41,6496.3 h137.54
  text "L2 (GP1)" at 17992.98,6496.3 h137.54
  text "100" at 16708.41,6293 h137.54
  text "1" at 17149.45,6293 h137.54
  text "0" at 17215.63,6293 h137.54
  text "L1" at 15297.79,6291.3 h137.54
  text "L2 (GP1)" at 17979.19,6280 h137.54
  text "Diff 100 ohms / 8 mil wide, 8 mil space" at 15730,6245 h100
  text "5" at 16698.41,6093 h137.54
  text "0" at 16764.58,6093 h137.54
  text "1" at 17149.45,6093 h137.54
  text "0" at 17215.63,6093 h137.54
  text "5" at 15900.78,6092 h137.54
  text "m" at 15966.95,6092 h137.54
  text "i" at 16061.48,6092 h137.54
  text "l" at 16099.29,6092 h137.54
  text "s" at 16137.11,6092 h137.54
  text "L5 and L7" at 17969.19,6080 h137.54
  text "L6" at 15285,6078 h137.54
  text "5" at 16694.22,5861 h137.54
  text "0" at 16760.39,5861 h137.54
  text "1" at 17145.26,5861 h137.54
  text "0" at 17211.43,5861 h137.54
  text "11" at 15896.59,5860 h137.54
  text "m" at 16022.76,5860 h137.54
  text "i" at 16117.29,5860 h137.54
  text "l" at 16155.1,5860 h137.54
  text "s" at 16192.91,5860 h137.54
  text "L7" at 17965,5848 h137.54
  text "L8" at 15280.81,5846 h137.54
  text "DESIGN INFORMATION" at 16758.02,5364 h60
  text "MIN. TRACK WIDTH:" at 16113.46,5184 h60
  text "5" at 17209.7,5184 h60
  text "MIL" at 17364.46,5184 h60
  text "MIN. CLEARANCE:" at 16113.46,5052 h60
  text "5" at 17149.7,5052 h60
  text "MIL" at 17364.46,5052 h60
  text "MIN. VIA PAD SIZE:" at 16113.46,4920 h60
  text "19.7" at 17130,4920 h60
  text "MIL" at 17364.46,4920 h60
  text "0.05mm (2MIL)" at 16808.46,4778.29 h60
  text "MINIMUM ANNULAR RING" at 15784.23,4774 h60
  text "EXTERNAL" at 17516.46,4774 h60
  text "PER" at 15984.23,4656 h60
  text "IPC-D-275 CLASS 2 LEVEL C" at 16204.23,4656 h60
  text "MIL, HOLES" at 17692.46,4543.71 h60
  text "+/-" at 17300,4543 h60
  text "+/-" at 18154,4543 h60
  text "REGISTRATION TOLERANCES:" at 15784.23,4538 h60
  text "METAL" at 16984,4538 h60
  text "5" at 17560.2,4538 h60
  text "3" at 18393.2,4538 h60
  text "MIL" at 18509.46,4538 h60
  text "+/-" at 18154,4425 h60
  text "HOLE SIZE TOLERANCE (UNLESS OTHERWISE SPECIFIED):" at 15784.23,4420 h60
  text "3" at 18393.2,4420 h60
  text "MIL" at 18509.46,4420 h60
  text "MATERIAL:" at 15709.46,4210.54 h60
  text "FR-4 High Tg" at 16695.9,4070.21 h60
  text "FR-408" at 16130.46,4061.64 h60
  text "OTHER" at 17618.46,4061.64 h60
  text "X" at 16541,4058 h60
  text "62 MIL (1.6mm) +/-10%" at 16450.56,3898.92 h60
  text "THICKNESS:" at 15784.23,3894.64 h60
  text "X" at 16322.4,3894.64 h60
  text "OTHER" at 17735.46,3894.64 h60
  text "TOLERANCE:" at 15784.23,3736.64 h60
  text "X" at 16623.53,3736.64 h60
  text "ANSI IPC-6012 TYPE 3 CLASS 2" at 16810.48,3736.64 h60
  text "OTHER +/-" at 16810.46,3580.64 h60
  text "BOW & TWIST:" at 15784.23,3423.64 h60
  text "X" at 16623.53,3423.64 h60
  text "ANSI IPC-6012 TYPE 3 CLASS 2" at 16810.48,3423.64 h60
  text "OTHER +/-" at 16810.46,3265.13 h60
  text "DRILLING:" at 15709.46,3126.64 h60
  text "REFERENCE:" at 15784.23,3009.64 h60
  text "X" at 16432.46,3009.64 h60
  text "AS SHOWN" at 16619.46,3009.64 h60
  text "X" at 17333.46,3009.64 h60
  text "NC_DRILL FILES" at 17470.46,3009.64 h60
  text "PTH COPPER THICKNESS:" at 15784.23,2851.64 h60
  text "X" at 16914.46,2851.64 h60
  text "20-30 um" at 17051.46,2851.64 h60
  text "OTHER" at 17768.46,2851.64 h60
  text "BOARD FINISH:" at 15709.46,2692.64 h60
  text "SILKSCREEN:" at 15864.68,2574.64 h60
  text "X" at 16813.46,2574.64 h60
  text "TOP" at 16939.46,2574.64 h60
  text "X" at 17323.46,2574.64 h60
  text "BOTTOM" at 17450.46,2574.64 h60
  text "SILKSCREEN COLOR:" at 15864.68,2407.64 h60
  text "X" at 16812.42,2407.64 h60
  text "WHITE" at 16939.46,2407.64 h60
  text "OTHER" at 17450.46,2407.64 h60
  text "X" at 16943.42,2248.44 h60
  text "GREEN" at 17070.46,2248.44 h60
  text "OTHER" at 17688.46,2248.44 h60
  text "SOLDER RESIST COLOR:" at 15864.68,2237.64 h60
  text "X" at 16943.42,2078.44 h60
  text "MATTE" at 17070.46,2078.44 h60
  text "SEMI-GLOSS" at 17688,2077.8 h60
  text "IMMERSION GOLD (ENIG)" at 16770.46,1889.92 h60
  text "ENEPIG" at 18108,1886.64 h60
  text "SURFACE FINISH:" at 15709.46,1885.64 h60
  text "X" at 16583.51,1885.64 h60
  text "IMM. TIN/SILVER OR EQUIV" at 16039,1728.64 h60
  text "OTHER" at 17470.46,1728.64 h60
  text "ARRAY/PANEL:" at 15709.46,1549.64 h60
  text "CUT AND TRIM PER M1 BOARD OUTLINE" at 16770.46,1545.35 h60
  text "N.C. ROUTE" at 16770.46,1393.64 h60
  text "V. SCORE" at 17636.46,1393.64 h60
  text "X" at 16585,1383 h60
  text "CERTIFICATION:" at 15709.46,1256.64 h60
  text "MATERIALS AND WORKMANSHIP FOR ALL PCBS" at 16434.46,1256.64 h60
  text "TO MEET OR EXCEED THE REQUIREMENTS OF:" at 16434.46,1158.64 h60
  text "X" at 16060.96,1022.13 h60
  text "ANSI IPC-A-600F CLASS ->" at 16199.96,1022.13 h60
  text "X" at 17839.02,1022.13 h60
  text "2" at 17957.96,1022.14 h60
  text "1" at 17642.96,1020.64 h60
  text "3" at 18311.96,1020.64 h60
  text "X" at 16875.02,862.64 h60
  text "RoHS" at 17011.96,862.64 h60
  text "OTHER" at 17656.36,862.64 h60
  text "PER ORDER" at 18053.42,862.64 h60
  text "ALL BOARDS MUST MEET OR EXCEED UL94-V0 REQUIREMENTS." at 15737,697 h60
  text "PCB MUST BEAR THE UL94V-0 UL REGISTERED MATERIAL ID NUMBER" at 15737,577 h60
  text "ADDITIONAL REQUIREMENTS:" at 15709.46,403.64 h60
  text "MICROSECTION:" at 15784.23,288.64 h60
  text "YES" at 16689.96,288.64 h60
  text "REQUIRED" at 17551.46,132.49 h60
  text "BARE BOARD ELEC. TEST:" at 15784.23,129.64 h60
  text "NONE" at 17089.96,129.64 h60
  text "X" at 17424.46,129.64 h60
  text "PER ORDER" at 18143.46,129.64 h60
  text ".Layer_Name" at 321,-1754.49 h60
M11 Gerber Information:
  lines w10: -292,-1830.17 6308,-1830.17 ; -292,-1626.83 6310,-1626.83 ; -292,-1423.5 -292,-2033.5 3713,-2033.5 6310,-2033.5 6310,-1423.5 -291.5,-1423.5 -291.5,-2033.5 1284,-2033.5 ; 2173,-2033.5 2173,-1423.5 ; 3440,-1626.83 3440,-1423.5 ; 4280,-1626.83 4280,-1423.5 ; 4902,-2040 4902,-1837.17
  text "ALL ARTWORK VIEWED FROM TOP SIDE" at -228.5,-1555.67 h60
  text "BOARD #:" at 2248,-1555.67 h60
  text ".PRJ_Number" at 2793.5,-1555.67 h60
  text "REV:" at 3638,-1555.67 h60
  text ".PCB_Rev" at 3929.5,-1555.67 h60
  text "SVN REV:" at 4476,-1555.67 h60
  text ".VersionControl_RevNumber" at 4982,-1555.67 h60
  text "LAYER NAME =" at -228.5,-1758.49 h60
  text "TID #:" at 2248,-1759 h60
  text ".TID" at 2793.5,-1759 h60
  text "PLOT NAME =" at -228.5,-1964.34 h60
  text ".plot_File_Name" at 577,-1964.34 h60
  text "GENERATED    :" at 2250,-1964.34 h60
  text ".Print_Date" at 3119.5,-1964.34 h60
  text ".Print_Time" at 3848.5,-1964.34 h60
  text "TEXAS INSTRUMENTS" at 5113,-1964.34 h60
M12 Stackup:
  drawing of 1140 lines, arcs and shapes, not listed
  text "Layer" at 8958.6,9372.56 h60
  text "Name" at 9368.51,9372.56 h60
  text "Material" at 10698.13,9372.56 h60
  text "Thickness" at 11557.9,9372.56 h60
  text "Constant" at 12207.73,9372.56 h60
  text "Board Layer Stack" at 12777.59,9372.56 h60
  text "Board Layer Stack" at 13897.27,9372.56 h60
  text "Top Overlay" at 9368.51,9252.56 h60
  text "Top Solder" at 9368.51,9132.56 h60
  text "Solder Resist" at 10698.13,9132.56 h60
  text "0.40mil" at 11557.9,9132.56 h60
  text "3.5" at 12207.73,9132.56 h60
  text "1" at 8958.6,9012.56 h60
  text "L1-Top Layer (GTL)" at 9368.51,9012.56 h60
  text "1.40mil" at 11557.9,9012.56 h60
  text "Dielectric1" at 9368.51,8892.56 h60
  text "FR-4" at 10698.13,8892.56 h60
  text "7.00mil" at 11557.9,8892.56 h60
  text "4.6" at 12207.73,8892.56 h60
  text "2" at 8958.6,8772.56 h60
  text "L2-GND Plane (GP1)" at 9368.51,8772.56 h60
  text "1.40mil" at 11557.9,8772.56 h60
  text "Dielectric2" at 9368.51,8652.56 h60
  text "FR-4" at 10698.13,8652.56 h60
  text "7.00mil" at 11557.9,8652.56 h60
  text "4.6" at 12207.73,8652.56 h60
  text "3" at 8958.6,8532.56 h60
  text "L3-Mid-Layer 2 (G1)" at 9368.51,8532.56 h60
  text "1.40mil" at 11557.9,8532.56 h60
  text "Dielectric3" at 9368.51,8412.56 h60
  text "FR-4" at 10698.13,8412.56 h60
  text "5.00mil" at 11557.9,8412.56 h60
  text "4.6" at 12207.73,8412.56 h60
  text "4" at 8958.6,8292.56 h60
  text "L4-Mid-Layer 3 (G2)" at 9368.51,8292.56 h60
  text "1.40mil" at 11557.9,8292.56 h60
  text "Dielectric4" at 9368.51,8172.56 h60
  text "FR-4" at 10698.13,8172.56 h60
  text "12.00mil" at 11557.9,8172.56 h60
  text "4.6" at 12207.73,8172.56 h60
  text "5" at 8958.6,8052.56 h60
  text "L5-Mid-Layer 4 (G3)" at 9368.51,8052.56 h60
  text "1.40mil" at 11557.9,8052.56 h60
  text "Dielectric5" at 9368.51,7932.56 h60
  text "FR-4" at 10698.13,7932.56 h60
  text "5.00mil" at 11557.9,7932.56 h60
  text "4.6" at 12207.73,7932.56 h60
  text "6" at 8958.6,7812.56 h60
  text "L6-Mid-Layer 5 (G4)" at 9368.51,7812.56 h60
  text "1.40mil" at 11557.9,7812.56 h60
  text "Dielectric6" at 9368.51,7692.56 h60
  text "FR-4" at 10698.13,7692.56 h60
  text "7.00mil" at 11557.9,7692.56 h60
  text "4.6" at 12207.73,7692.56 h60
  text "7" at 8958.6,7572.56 h60
  text "L7-Mid-Layer 6 (G5)" at 9368.51,7572.56 h60
  text "1.40mil" at 11557.9,7572.56 h60
  text "Dielectric7" at 9368.51,7452.56 h60
  text "FR-4" at 10698.13,7452.56 h60
  text "7.00mil" at 11557.9,7452.56 h60
  text "4.6" at 12207.73,7452.56 h60
  text "8" at 8958.6,7332.56 h60
  text "L8-Bottom Layer (GBL)" at 9368.51,7332.56 h60
  text "1.40mil" at 11557.9,7332.56 h60
  text "Bottom Solder" at 9368.51,7212.56 h60
  text "Solder Resist" at 10698.13,7212.56 h60
  text "0.40mil" at 11557.9,7212.56 h60
  text "3.5" at 12207.73,7212.56 h60
  text "Bottom Overlay" at 9368.51,7092.56 h60
  text ".Layer_Name" at 321,-1754.49 h60
M13 Component Bodies Top:
  text ".Layer_Name" at 321,-1754.49 h60
  text ".Layer_Name" at 577,-1758.49 h60
M14 Component Bodies Bottom:
  text ".Layer_Name" at 321,-1754.49 h60
  text ".Layer_Name" at 577,-1758.49 h60
M15 Courtyards Top:
  text ".Layer_Name" at 321,-1754.49 h60
  text ".Layer_Name" at 577,-1758.49 h60
M16 Courtyards Bottom:
  text ".Layer_Name" at 321,-1754.49 h60
  text ".Layer_Name" at 577,-1758.49 h60
Drill Drawing:
  circle w10: c7030.12,10661.33 r33.33
  lines w10: 6996.79,10178 6996.79,10194.67 7013.45,10211.33 6996.79,10228 6996.79,10244.67 7013.45,10244.67 7030.12,10228 7046.79,10244.67 7063.45,10244.67 7063.45,10228 7046.79,10211.33 7063.45,10194.67 7063.45,10178 7046.79,10178 7030.12,10194.67 7013.45,10178 6996.79,10178 ; 6996.79,10328 7030.12,10344.67 7063.45,10328 7046.79,10361.33 7063.45,10394.67 7030.12,10378 6996.79,10394.67 7013.45,10361.33 6996.79,10328 ; 6996.79,10478 7063.45,10478 7063.45,10544.67 6996.79,10544.67 6996.79,10478 ; 6996.79,10794.67 7013.45,10794.67 7013.45,10778 7046.79,10778 7046.79,10794.67 7063.45,10794.67 7063.45,10828 7046.79,10828 7046.79,10844.67 7013.45,10844.67 7013.45,10828 6996.79,10828 6996.79,10794.67 ; 6996.79,10928 7063.45,10928 7063.45,10994.67 6996.79,10994.67 6996.79,10928 ; 6996.79,11111.33 7030.12,11078 7063.45,11111.33 7030.12,11144.67 6996.79,11111.33 ; 6996.79,11228 7030.12,11244.67 7063.45,11228 7046.79,11261.33 7063.45,11294.67 7030.12,11278 6996.79,11294.67 7013.45,11261.33 6996.79,11228 ; 6996.79,11594.67 7063.45,11594.67 7030.12,11528 6996.79,11594.67 ; 6996.79,11678 6996.79,11694.67 7013.45,11711.33 6996.79,11728 6996.79,11744.67 7013.45,11744.67 7030.12,11728 7046.79,11744.67 7063.45,11744.67 7063.45,11728 7046.79,11711.33 7063.45,11694.67 7063.45,11678 7046.79,11678 7030.12,11694.67 7013.45,11678 6996.79,11678 ; 7010.12,10191.33 7010.12,10201.33 7020.12,10211.33 7010.12,10221.33 7010.12,10231.33 7020.12,10231.33 7030.12,10221.33 7040.12,10231.33 7050.12,10231.33 7050.12,10221.33 7040.12,10211.33 7050.12,10201.33 7050.12,10191.33 7040.12,10191.33 7030.12,10201.33 7020.12,10191.33 7010.12,10191.33 ; 7010.12,10341.33 7030.12,10351.33 7050.12,10341.33 7040.12,10361.33 7050.12,10381.33 7030.12,10371.33 7010.12,10381.33 7020.12,10361.33 7010.12,10341.33 ; 7010.12,10941.33 7050.12,10941.33 7050.12,10981.33 7010.12,10981.33 7010.12,10941.33
  lines w15: 6936.99,9983 18607.71,9983 ; 6936.99,11783 18607.71,11783 ; 7487.87,9833 7487.87,11933 ; 8137.69,9833 8137.69,11933 ; 9287.36,9833 9287.36,11933 ; 9793.23,9833 9793.23,11933 ; 10527.04,9833 10527.04,11933 ; 13056.25,9833 13056.25,11933 ; 13646.1,9833 13646.1,11933 ; 14391.9,9833 14391.9,11933 ; 15041.73,9833 15041.73,11933 ; 15895.49,9833 15895.49,11933 ; 17229.1,9833 17229.1,11933 ; 6936.99,9833 18607.71,9833 18607.71,11933 6936.99,11933 6936.99,9833
  text "Symbol" at 7026.99,11828 h72
  text "Count" at 7532.87,11828 h72
  text "Hole Size" at 8182.69,11828 h72
  text "Plated" at 9332.36,11828 h72
  text "Hole Type" at 9838.23,11828 h72
  text "Drill Layer Pair" at 10572.04,11828 h72
  text "Via/Pad" at 13101.25,11828 h72
  text "Pad Shape" at 13691.1,11828 h72
  text "Template" at 14436.9,11828 h72
  text "Description" at 15086.73,11828 h72
  text "Hole Tolerance (+)" at 15940.49,11828 h72
  text "Hole Tolerance (-)" at 17274.1,11828 h72
  text "1" at 7532.87,11678 h60
  text "62.00mil (1.575mm)" at 8182.69,11678 h60
  text "PTH" at 9332.36,11678 h60
  text "Round" at 9838.23,11678 h60
  text "L1-Top Layer (GTL) - L8-Bottom Layer (GBL)" at 10572.04,11678 h60
  text "Pad" at 13101.25,11678 h60
  text "Rounded" at 13691.1,11678 h60
  text "c241h157" at 14436.9,11678 h60
  text "1" at 7532.87,11528 h60
  text "157.00mil (3.988mm)" at 8182.69,11528 h60
  text "PTH" at 9332.36,11528 h60
  text "Round" at 9838.23,11528 h60
  text "L1-Top Layer (GTL) - L8-Bottom Layer (GBL)" at 10572.04,11528 h60
  text "Pad" at 13101.25,11528 h60
  text "Rounded" at 13691.1,11528 h60
  text "c640h399" at 14436.9,11528 h60
  text "2" at 7532.87,11378 h60
  text "35.43mil (0.900mm)" at 8182.69,11378 h60
  text "NPTH" at 9332.36,11378 h60
  text "Round" at 9838.23,11378 h60
  text "L1-Top Layer (GTL) - L8-Bottom Layer (GBL)" at 10572.04,11378 h60
  text "Pad" at 13101.25,11378 h60
  text "Rounded" at 13691.1,11378 h60
  text "c90hn90" at 14436.9,11378 h60
  text "B" at 6997.9,11368.01 h66.67
  text "4" at 7532.87,11228 h60
  text "28.00mil (0.711mm)" at 8182.69,11228 h60
  text "PTH" at 9332.36,11228 h60
  text "Round" at 9838.23,11228 h60
  text "L1-Top Layer (GTL) - L8-Bottom Layer (GBL)" at 10572.04,11228 h60
  text "Via" at 13101.25,11228 h60
  text "Rounded" at 13691.1,11228 h60
  text "v127h71" at 14436.9,11228 h60
  text "4" at 7532.87,11078 h60
  text "67.00mil (1.702mm)" at 8182.69,11078 h60
  text "PTH" at 9332.36,11078 h60
  text "Round" at 9838.23,11078 h60
  text "L1-Top Layer (GTL) - L8-Bottom Layer (GBL)" at 10572.04,11078 h60
  text "Pad" at 13101.25,11078 h60
  text "Rounded" at 13691.1,11078 h60
  text "c254h170" at 14436.9,11078 h60
  text "5" at 7532.87,10928 h60
  text "43.00mil (1.092mm)" at 8182.69,10928 h60
  text "PTH" at 9332.36,10928 h60
  text "Round" at 9838.23,10928 h60
  text "L1-Top Layer (GTL) - L8-Bottom Layer (GBL)" at 10572.04,10928 h60
  text "Pad" at 13101.25,10928 h60
  text "(Mixed)" at 13691.1,10928 h60
  text "(Mixed)" at 14436.9,10928 h60
  text "5.00mil (0.127mm)" at 15940.49,10928 h60
  text "5.00mil (0.127mm)" at 17274.1,10928 h60
  text "6" at 7532.87,10778 h60
  text "19.69mil (0.500mm)" at 8182.69,10778 h60
  text "PTH" at 9332.36,10778 h60
  text "Round" at 9838.23,10778 h60
  text "L1-Top Layer (GTL) - L8-Bottom Layer (GBL)" at 10572.04,10778 h60
  text "Via" at 13101.25,10778 h60
  text "Rounded" at 13691.1,10778 h60
  text "v100h50m0" at 14436.9,10778 h60
  text "10" at 7532.87,10628 h60
  text "20.00mil (0.508mm)" at 8182.69,10628 h60
  text "PTH" at 9332.36,10628 h60
  text "Round" at 9838.23,10628 h60
  text "L1-Top Layer (GTL) - L8-Bottom Layer (GBL)" at 10572.04,10628 h60
  text "Via" at 13101.25,10628 h60
  text "Rounded" at 13691.1,10628 h60
  text "v102h51" at 14436.9,10628 h60
  text "15" at 7532.87,10478 h60
  text "40.00mil (1.016mm)" at 8182.69,10478 h60
  text "PTH" at 9332.36,10478 h60
  text "Round" at 9838.23,10478 h60
  text "L1-Top Layer (GTL) - L8-Bottom Layer (GBL)" at 10572.04,10478 h60
  text "Pad" at 13101.25,10478 h60
  text "Rounded" at 13691.1,10478 h60
  text "c203h102" at 14436.9,10478 h60
  text "47" at 7532.87,10328 h60
  text "7.87mil (0.200mm)" at 8182.69,10328 h60
  text "PTH" at 9332.36,10328 h60
  text "Round" at 9838.23,10328 h60
  text "L1-Top Layer (GTL) - L8-Bottom Layer (GBL)" at 10572.04,10328 h60
  text "Via" at 13101.25,10328 h60
  text "Rounded" at 13691.1,10328 h60
  text "(Mixed)" at 14436.9,10328 h60
  text "649" at 7532.87,10178 h60
  text "12.00mil (0.305mm)" at 8182.69,10178 h60
  text "PTH" at 9332.36,10178 h60
  text "Round" at 9838.23,10178 h60
  text "L1-Top Layer (GTL) - L8-Bottom Layer (GBL)" at 10572.04,10178 h60
  text "Via" at 13101.25,10178 h60
  text "Rounded" at 13691.1,10178 h60
  text "(Mixed)" at 14436.9,10178 h60
  text "1096" at 7532.87,10028 h60
  text "10.00mil (0.254mm)" at 8182.69,10028 h60
  text "PTH" at 9332.36,10028 h60
  text "Round" at 9838.23,10028 h60
  text "L1-Top Layer (GTL) - L8-Bottom Layer (GBL)" at 10572.04,10028 h60
  text "Via" at 13101.25,10028 h60
  text "Rounded" at 13691.1,10028 h60
  text "(Mixed)" at 14436.9,10028 h60
  text "C" at 6997.9,10018.01 h66.67
  text "1840 Total" at 7532.87,9878 h60
  text ".Layer_Name" at 321,-1754.49 h60
M18 Embedded Assembly:
  text ".Layer_Name" at 577,-1758.49 h60

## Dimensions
7000,9161 to 7000,0 on M2 Board Dimensions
